VERSION 5.8 ;
BUSBITCHARS "[]" ;
DIVIDERCHAR "/" ;
UNITS
    DATABASE MICRONS 1000 ;
END UNITS

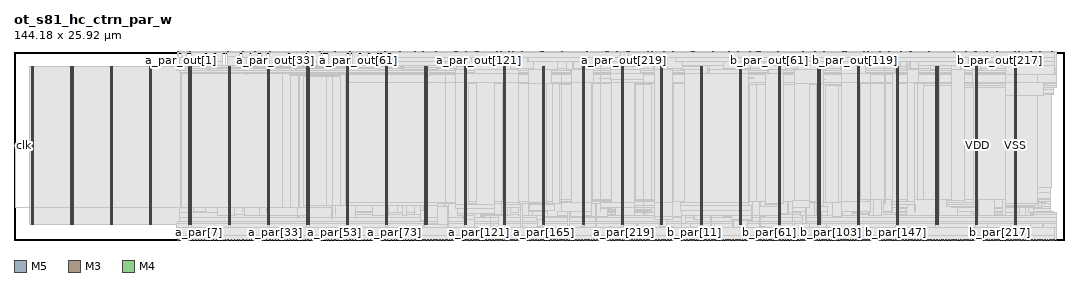
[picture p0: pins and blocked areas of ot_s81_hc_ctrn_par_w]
MACRO ot_s81_hc_ctrn_par_w
  FOREIGN ot_s81_hc_ctrn_par_w 0 0 ;
  CLASS BLOCK ;
  SIZE 144.18 BY 25.92 ;
  PIN a_par[0]
    DIRECTION INPUT ;
    USE SIGNAL ;
    PORT
      LAYER M5 ;
        RECT  22.512 0 22.536 0.084 ;
    END
  END a_par[0]
  PIN a_par[100]
    DIRECTION INPUT ;
    USE SIGNAL ;
    PORT
      LAYER M5 ;
        RECT  59.568 0 59.592 0.084 ;
    END
  END a_par[100]
  PIN a_par[101]
    DIRECTION INPUT ;
    USE SIGNAL ;
    PORT
      LAYER M3 ;
        RECT  59.796 0 59.814 0.038 ;
    END
  END a_par[101]
  PIN a_par[102]
    DIRECTION INPUT ;
    USE SIGNAL ;
    PORT
      LAYER M5 ;
        RECT  60.048 0 60.072 0.084 ;
    END
  END a_par[102]
  PIN a_par[103]
    DIRECTION INPUT ;
    USE SIGNAL ;
    PORT
      LAYER M3 ;
        RECT  60.192 0 60.21 0.038 ;
    END
  END a_par[103]
  PIN a_par[104]
    DIRECTION INPUT ;
    USE SIGNAL ;
    PORT
      LAYER M5 ;
        RECT  60.432 0 60.456 0.084 ;
    END
  END a_par[104]
  PIN a_par[105]
    DIRECTION INPUT ;
    USE SIGNAL ;
    PORT
      LAYER M3 ;
        RECT  60.552 0 60.57 0.038 ;
    END
  END a_par[105]
  PIN a_par[106]
    DIRECTION INPUT ;
    USE SIGNAL ;
    PORT
      LAYER M5 ;
        RECT  60.816 0 60.84 0.084 ;
    END
  END a_par[106]
  PIN a_par[107]
    DIRECTION INPUT ;
    USE SIGNAL ;
    PORT
      LAYER M3 ;
        RECT  61.056 0 61.074 0.038 ;
    END
  END a_par[107]
  PIN a_par[108]
    DIRECTION INPUT ;
    USE SIGNAL ;
    PORT
      LAYER M5 ;
        RECT  61.2 0 61.224 0.084 ;
    END
  END a_par[108]
  PIN a_par[109]
    DIRECTION INPUT ;
    USE SIGNAL ;
    PORT
      LAYER M3 ;
        RECT  61.416 0 61.434 0.038 ;
    END
  END a_par[109]
  PIN a_par[10]
    DIRECTION INPUT ;
    USE SIGNAL ;
    PORT
      LAYER M5 ;
        RECT  26.544 0 26.568 0.084 ;
    END
  END a_par[10]
  PIN a_par[110]
    DIRECTION INPUT ;
    USE SIGNAL ;
    PORT
      LAYER M5 ;
        RECT  61.584 0 61.608 0.084 ;
    END
  END a_par[110]
  PIN a_par[111]
    DIRECTION INPUT ;
    USE SIGNAL ;
    PORT
      LAYER M3 ;
        RECT  61.812 0 61.83 0.038 ;
    END
  END a_par[111]
  PIN a_par[112]
    DIRECTION INPUT ;
    USE SIGNAL ;
    PORT
      LAYER M5 ;
        RECT  62.064 0 62.088 0.084 ;
    END
  END a_par[112]
  PIN a_par[113]
    DIRECTION INPUT ;
    USE SIGNAL ;
    PORT
      LAYER M3 ;
        RECT  62.208 0 62.226 0.038 ;
    END
  END a_par[113]
  PIN a_par[114]
    DIRECTION INPUT ;
    USE SIGNAL ;
    PORT
      LAYER M5 ;
        RECT  62.448 0 62.472 0.084 ;
    END
  END a_par[114]
  PIN a_par[115]
    DIRECTION INPUT ;
    USE SIGNAL ;
    PORT
      LAYER M3 ;
        RECT  62.676 0 62.694 0.038 ;
    END
  END a_par[115]
  PIN a_par[116]
    DIRECTION INPUT ;
    USE SIGNAL ;
    PORT
      LAYER M5 ;
        RECT  62.832 0 62.856 0.084 ;
    END
  END a_par[116]
  PIN a_par[117]
    DIRECTION INPUT ;
    USE SIGNAL ;
    PORT
      LAYER M3 ;
        RECT  63.072 0 63.09 0.038 ;
    END
  END a_par[117]
  PIN a_par[118]
    DIRECTION INPUT ;
    USE SIGNAL ;
    PORT
      LAYER M5 ;
        RECT  63.216 0 63.24 0.084 ;
    END
  END a_par[118]
  PIN a_par[119]
    DIRECTION INPUT ;
    USE SIGNAL ;
    PORT
      LAYER M3 ;
        RECT  63.432 0 63.45 0.038 ;
    END
  END a_par[119]
  PIN a_par[11]
    DIRECTION INPUT ;
    USE SIGNAL ;
    PORT
      LAYER M3 ;
        RECT  26.964 0 26.982 0.038 ;
    END
  END a_par[11]
  PIN a_par[120]
    DIRECTION INPUT ;
    USE SIGNAL ;
    PORT
      LAYER M5 ;
        RECT  63.696 0 63.72 0.084 ;
    END
  END a_par[120]
  PIN a_par[121]
    DIRECTION INPUT ;
    USE SIGNAL ;
    PORT
      LAYER M3 ;
        RECT  63.828 0 63.846 0.038 ;
    END
  END a_par[121]
  PIN a_par[122]
    DIRECTION INPUT ;
    USE SIGNAL ;
    PORT
      LAYER M5 ;
        RECT  64.08 0 64.104 0.084 ;
    END
  END a_par[122]
  PIN a_par[123]
    DIRECTION INPUT ;
    USE SIGNAL ;
    PORT
      LAYER M3 ;
        RECT  64.224 0 64.242 0.038 ;
    END
  END a_par[123]
  PIN a_par[124]
    DIRECTION INPUT ;
    USE SIGNAL ;
    PORT
      LAYER M5 ;
        RECT  64.464 0 64.488 0.084 ;
    END
  END a_par[124]
  PIN a_par[125]
    DIRECTION INPUT ;
    USE SIGNAL ;
    PORT
      LAYER M3 ;
        RECT  64.692 0 64.71 0.038 ;
    END
  END a_par[125]
  PIN a_par[126]
    DIRECTION INPUT ;
    USE SIGNAL ;
    PORT
      LAYER M5 ;
        RECT  64.848 0 64.872 0.084 ;
    END
  END a_par[126]
  PIN a_par[127]
    DIRECTION INPUT ;
    USE SIGNAL ;
    PORT
      LAYER M3 ;
        RECT  65.088 0 65.106 0.038 ;
    END
  END a_par[127]
  PIN a_par[128]
    DIRECTION INPUT ;
    USE SIGNAL ;
    PORT
      LAYER M5 ;
        RECT  65.328 0 65.352 0.084 ;
    END
  END a_par[128]
  PIN a_par[129]
    DIRECTION INPUT ;
    USE SIGNAL ;
    PORT
      LAYER M3 ;
        RECT  65.448 0 65.466 0.038 ;
    END
  END a_par[129]
  PIN a_par[12]
    DIRECTION INPUT ;
    USE SIGNAL ;
    PORT
      LAYER M5 ;
        RECT  27.408 0 27.432 0.084 ;
    END
  END a_par[12]
  PIN a_par[130]
    DIRECTION INPUT ;
    USE SIGNAL ;
    PORT
      LAYER M5 ;
        RECT  65.712 0 65.736 0.084 ;
    END
  END a_par[130]
  PIN a_par[131]
    DIRECTION INPUT ;
    USE SIGNAL ;
    PORT
      LAYER M3 ;
        RECT  65.844 0 65.862 0.038 ;
    END
  END a_par[131]
  PIN a_par[132]
    DIRECTION INPUT ;
    USE SIGNAL ;
    PORT
      LAYER M5 ;
        RECT  66.096 0 66.12 0.084 ;
    END
  END a_par[132]
  PIN a_par[133]
    DIRECTION INPUT ;
    USE SIGNAL ;
    PORT
      LAYER M3 ;
        RECT  66.312 0 66.33 0.038 ;
    END
  END a_par[133]
  PIN a_par[134]
    DIRECTION INPUT ;
    USE SIGNAL ;
    PORT
      LAYER M5 ;
        RECT  66.48 0 66.504 0.084 ;
    END
  END a_par[134]
  PIN a_par[135]
    DIRECTION INPUT ;
    USE SIGNAL ;
    PORT
      LAYER M3 ;
        RECT  66.708 0 66.726 0.038 ;
    END
  END a_par[135]
  PIN a_par[136]
    DIRECTION INPUT ;
    USE SIGNAL ;
    PORT
      LAYER M5 ;
        RECT  66.864 0 66.888 0.084 ;
    END
  END a_par[136]
  PIN a_par[137]
    DIRECTION INPUT ;
    USE SIGNAL ;
    PORT
      LAYER M3 ;
        RECT  67.104 0 67.122 0.038 ;
    END
  END a_par[137]
  PIN a_par[138]
    DIRECTION INPUT ;
    USE SIGNAL ;
    PORT
      LAYER M5 ;
        RECT  67.344 0 67.368 0.084 ;
    END
  END a_par[138]
  PIN a_par[139]
    DIRECTION INPUT ;
    USE SIGNAL ;
    PORT
      LAYER M3 ;
        RECT  67.464 0 67.482 0.038 ;
    END
  END a_par[139]
  PIN a_par[13]
    DIRECTION INPUT ;
    USE SIGNAL ;
    PORT
      LAYER M3 ;
        RECT  27.828 0 27.846 0.038 ;
    END
  END a_par[13]
  PIN a_par[140]
    DIRECTION INPUT ;
    USE SIGNAL ;
    PORT
      LAYER M5 ;
        RECT  67.728 0 67.752 0.084 ;
    END
  END a_par[140]
  PIN a_par[141]
    DIRECTION INPUT ;
    USE SIGNAL ;
    PORT
      LAYER M3 ;
        RECT  67.968 0 67.986 0.038 ;
    END
  END a_par[141]
  PIN a_par[142]
    DIRECTION INPUT ;
    USE SIGNAL ;
    PORT
      LAYER M5 ;
        RECT  68.112 0 68.136 0.084 ;
    END
  END a_par[142]
  PIN a_par[143]
    DIRECTION INPUT ;
    USE SIGNAL ;
    PORT
      LAYER M3 ;
        RECT  68.328 0 68.346 0.038 ;
    END
  END a_par[143]
  PIN a_par[144]
    DIRECTION INPUT ;
    USE SIGNAL ;
    PORT
      LAYER M5 ;
        RECT  68.496 0 68.52 0.084 ;
    END
  END a_par[144]
  PIN a_par[145]
    DIRECTION INPUT ;
    USE SIGNAL ;
    PORT
      LAYER M3 ;
        RECT  68.724 0 68.742 0.038 ;
    END
  END a_par[145]
  PIN a_par[146]
    DIRECTION INPUT ;
    USE SIGNAL ;
    PORT
      LAYER M5 ;
        RECT  68.976 0 69 0.084 ;
    END
  END a_par[146]
  PIN a_par[147]
    DIRECTION INPUT ;
    USE SIGNAL ;
    PORT
      LAYER M3 ;
        RECT  69.12 0 69.138 0.038 ;
    END
  END a_par[147]
  PIN a_par[148]
    DIRECTION INPUT ;
    USE SIGNAL ;
    PORT
      LAYER M5 ;
        RECT  69.36 0 69.384 0.084 ;
    END
  END a_par[148]
  PIN a_par[149]
    DIRECTION INPUT ;
    USE SIGNAL ;
    PORT
      LAYER M3 ;
        RECT  69.588 0 69.606 0.038 ;
    END
  END a_par[149]
  PIN a_par[14]
    DIRECTION INPUT ;
    USE SIGNAL ;
    PORT
      LAYER M5 ;
        RECT  28.176 0 28.2 0.084 ;
    END
  END a_par[14]
  PIN a_par[150]
    DIRECTION INPUT ;
    USE SIGNAL ;
    PORT
      LAYER M5 ;
        RECT  69.744 0 69.768 0.084 ;
    END
  END a_par[150]
  PIN a_par[151]
    DIRECTION INPUT ;
    USE SIGNAL ;
    PORT
      LAYER M3 ;
        RECT  69.984 0 70.002 0.038 ;
    END
  END a_par[151]
  PIN a_par[152]
    DIRECTION INPUT ;
    USE SIGNAL ;
    PORT
      LAYER M5 ;
        RECT  70.128 0 70.152 0.084 ;
    END
  END a_par[152]
  PIN a_par[153]
    DIRECTION INPUT ;
    USE SIGNAL ;
    PORT
      LAYER M3 ;
        RECT  70.344 0 70.362 0.038 ;
    END
  END a_par[153]
  PIN a_par[154]
    DIRECTION INPUT ;
    USE SIGNAL ;
    PORT
      LAYER M5 ;
        RECT  70.608 0 70.632 0.084 ;
    END
  END a_par[154]
  PIN a_par[155]
    DIRECTION INPUT ;
    USE SIGNAL ;
    PORT
      LAYER M3 ;
        RECT  70.74 0 70.758 0.038 ;
    END
  END a_par[155]
  PIN a_par[156]
    DIRECTION INPUT ;
    USE SIGNAL ;
    PORT
      LAYER M5 ;
        RECT  70.992 0 71.016 0.084 ;
    END
  END a_par[156]
  PIN a_par[157]
    DIRECTION INPUT ;
    USE SIGNAL ;
    PORT
      LAYER M3 ;
        RECT  71.136 0 71.154 0.038 ;
    END
  END a_par[157]
  PIN a_par[158]
    DIRECTION INPUT ;
    USE SIGNAL ;
    PORT
      LAYER M5 ;
        RECT  71.376 0 71.4 0.084 ;
    END
  END a_par[158]
  PIN a_par[159]
    DIRECTION INPUT ;
    USE SIGNAL ;
    PORT
      LAYER M3 ;
        RECT  71.604 0 71.622 0.038 ;
    END
  END a_par[159]
  PIN a_par[15]
    DIRECTION INPUT ;
    USE SIGNAL ;
    PORT
      LAYER M3 ;
        RECT  28.584 0 28.602 0.038 ;
    END
  END a_par[15]
  PIN a_par[160]
    DIRECTION INPUT ;
    USE SIGNAL ;
    PORT
      LAYER M5 ;
        RECT  71.76 0 71.784 0.084 ;
    END
  END a_par[160]
  PIN a_par[161]
    DIRECTION INPUT ;
    USE SIGNAL ;
    PORT
      LAYER M3 ;
        RECT  72 0 72.018 0.038 ;
    END
  END a_par[161]
  PIN a_par[162]
    DIRECTION INPUT ;
    USE SIGNAL ;
    PORT
      LAYER M5 ;
        RECT  72.24 0 72.264 0.084 ;
    END
  END a_par[162]
  PIN a_par[163]
    DIRECTION INPUT ;
    USE SIGNAL ;
    PORT
      LAYER M3 ;
        RECT  72.36 0 72.378 0.038 ;
    END
  END a_par[163]
  PIN a_par[164]
    DIRECTION INPUT ;
    USE SIGNAL ;
    PORT
      LAYER M5 ;
        RECT  72.624 0 72.648 0.084 ;
    END
  END a_par[164]
  PIN a_par[165]
    DIRECTION INPUT ;
    USE SIGNAL ;
    PORT
      LAYER M3 ;
        RECT  72.756 0 72.774 0.038 ;
    END
  END a_par[165]
  PIN a_par[166]
    DIRECTION INPUT ;
    USE SIGNAL ;
    PORT
      LAYER M5 ;
        RECT  73.008 0 73.032 0.084 ;
    END
  END a_par[166]
  PIN a_par[167]
    DIRECTION INPUT ;
    USE SIGNAL ;
    PORT
      LAYER M3 ;
        RECT  73.224 0 73.242 0.038 ;
    END
  END a_par[167]
  PIN a_par[168]
    DIRECTION INPUT ;
    USE SIGNAL ;
    PORT
      LAYER M5 ;
        RECT  73.392 0 73.416 0.084 ;
    END
  END a_par[168]
  PIN a_par[169]
    DIRECTION INPUT ;
    USE SIGNAL ;
    PORT
      LAYER M3 ;
        RECT  73.62 0 73.638 0.038 ;
    END
  END a_par[169]
  PIN a_par[16]
    DIRECTION INPUT ;
    USE SIGNAL ;
    PORT
      LAYER M5 ;
        RECT  29.04 0 29.064 0.084 ;
    END
  END a_par[16]
  PIN a_par[170]
    DIRECTION INPUT ;
    USE SIGNAL ;
    PORT
      LAYER M5 ;
        RECT  73.776 0 73.8 0.084 ;
    END
  END a_par[170]
  PIN a_par[171]
    DIRECTION INPUT ;
    USE SIGNAL ;
    PORT
      LAYER M3 ;
        RECT  74.016 0 74.034 0.038 ;
    END
  END a_par[171]
  PIN a_par[172]
    DIRECTION INPUT ;
    USE SIGNAL ;
    PORT
      LAYER M5 ;
        RECT  74.256 0 74.28 0.084 ;
    END
  END a_par[172]
  PIN a_par[173]
    DIRECTION INPUT ;
    USE SIGNAL ;
    PORT
      LAYER M3 ;
        RECT  74.376 0 74.394 0.038 ;
    END
  END a_par[173]
  PIN a_par[174]
    DIRECTION INPUT ;
    USE SIGNAL ;
    PORT
      LAYER M5 ;
        RECT  74.64 0 74.664 0.084 ;
    END
  END a_par[174]
  PIN a_par[175]
    DIRECTION INPUT ;
    USE SIGNAL ;
    PORT
      LAYER M3 ;
        RECT  74.88 0 74.898 0.038 ;
    END
  END a_par[175]
  PIN a_par[176]
    DIRECTION INPUT ;
    USE SIGNAL ;
    PORT
      LAYER M5 ;
        RECT  75.024 0 75.048 0.084 ;
    END
  END a_par[176]
  PIN a_par[177]
    DIRECTION INPUT ;
    USE SIGNAL ;
    PORT
      LAYER M3 ;
        RECT  75.24 0 75.258 0.038 ;
    END
  END a_par[177]
  PIN a_par[178]
    DIRECTION INPUT ;
    USE SIGNAL ;
    PORT
      LAYER M5 ;
        RECT  75.408 0 75.432 0.084 ;
    END
  END a_par[178]
  PIN a_par[179]
    DIRECTION INPUT ;
    USE SIGNAL ;
    PORT
      LAYER M3 ;
        RECT  75.636 0 75.654 0.038 ;
    END
  END a_par[179]
  PIN a_par[17]
    DIRECTION INPUT ;
    USE SIGNAL ;
    PORT
      LAYER M3 ;
        RECT  29.376 0 29.394 0.038 ;
    END
  END a_par[17]
  PIN a_par[180]
    DIRECTION INPUT ;
    USE SIGNAL ;
    PORT
      LAYER M5 ;
        RECT  75.888 0 75.912 0.084 ;
    END
  END a_par[180]
  PIN a_par[181]
    DIRECTION INPUT ;
    USE SIGNAL ;
    PORT
      LAYER M3 ;
        RECT  76.032 0 76.05 0.038 ;
    END
  END a_par[181]
  PIN a_par[182]
    DIRECTION INPUT ;
    USE SIGNAL ;
    PORT
      LAYER M5 ;
        RECT  76.272 0 76.296 0.084 ;
    END
  END a_par[182]
  PIN a_par[183]
    DIRECTION INPUT ;
    USE SIGNAL ;
    PORT
      LAYER M3 ;
        RECT  76.392 0 76.41 0.038 ;
    END
  END a_par[183]
  PIN a_par[184]
    DIRECTION INPUT ;
    USE SIGNAL ;
    PORT
      LAYER M5 ;
        RECT  76.656 0 76.68 0.084 ;
    END
  END a_par[184]
  PIN a_par[185]
    DIRECTION INPUT ;
    USE SIGNAL ;
    PORT
      LAYER M3 ;
        RECT  76.896 0 76.914 0.038 ;
    END
  END a_par[185]
  PIN a_par[186]
    DIRECTION INPUT ;
    USE SIGNAL ;
    PORT
      LAYER M5 ;
        RECT  77.04 0 77.064 0.084 ;
    END
  END a_par[186]
  PIN a_par[187]
    DIRECTION INPUT ;
    USE SIGNAL ;
    PORT
      LAYER M3 ;
        RECT  77.256 0 77.274 0.038 ;
    END
  END a_par[187]
  PIN a_par[188]
    DIRECTION INPUT ;
    USE SIGNAL ;
    PORT
      LAYER M5 ;
        RECT  77.52 0 77.544 0.084 ;
    END
  END a_par[188]
  PIN a_par[189]
    DIRECTION INPUT ;
    USE SIGNAL ;
    PORT
      LAYER M3 ;
        RECT  77.652 0 77.67 0.038 ;
    END
  END a_par[189]
  PIN a_par[18]
    DIRECTION INPUT ;
    USE SIGNAL ;
    PORT
      LAYER M5 ;
        RECT  29.808 0 29.832 0.084 ;
    END
  END a_par[18]
  PIN a_par[190]
    DIRECTION INPUT ;
    USE SIGNAL ;
    PORT
      LAYER M5 ;
        RECT  77.904 0 77.928 0.084 ;
    END
  END a_par[190]
  PIN a_par[191]
    DIRECTION INPUT ;
    USE SIGNAL ;
    PORT
      LAYER M3 ;
        RECT  78.048 0 78.066 0.038 ;
    END
  END a_par[191]
  PIN a_par[192]
    DIRECTION INPUT ;
    USE SIGNAL ;
    PORT
      LAYER M5 ;
        RECT  78.288 0 78.312 0.084 ;
    END
  END a_par[192]
  PIN a_par[193]
    DIRECTION INPUT ;
    USE SIGNAL ;
    PORT
      LAYER M3 ;
        RECT  78.516 0 78.534 0.038 ;
    END
  END a_par[193]
  PIN a_par[194]
    DIRECTION INPUT ;
    USE SIGNAL ;
    PORT
      LAYER M5 ;
        RECT  78.672 0 78.696 0.084 ;
    END
  END a_par[194]
  PIN a_par[195]
    DIRECTION INPUT ;
    USE SIGNAL ;
    PORT
      LAYER M3 ;
        RECT  78.912 0 78.93 0.038 ;
    END
  END a_par[195]
  PIN a_par[196]
    DIRECTION INPUT ;
    USE SIGNAL ;
    PORT
      LAYER M5 ;
        RECT  79.056 0 79.08 0.084 ;
    END
  END a_par[196]
  PIN a_par[197]
    DIRECTION INPUT ;
    USE SIGNAL ;
    PORT
      LAYER M3 ;
        RECT  79.272 0 79.29 0.038 ;
    END
  END a_par[197]
  PIN a_par[198]
    DIRECTION INPUT ;
    USE SIGNAL ;
    PORT
      LAYER M5 ;
        RECT  79.536 0 79.56 0.084 ;
    END
  END a_par[198]
  PIN a_par[199]
    DIRECTION INPUT ;
    USE SIGNAL ;
    PORT
      LAYER M3 ;
        RECT  79.668 0 79.686 0.038 ;
    END
  END a_par[199]
  PIN a_par[19]
    DIRECTION INPUT ;
    USE SIGNAL ;
    PORT
      LAYER M3 ;
        RECT  30.24 0 30.258 0.038 ;
    END
  END a_par[19]
  PIN a_par[1]
    DIRECTION INPUT ;
    USE SIGNAL ;
    PORT
      LAYER M3 ;
        RECT  22.932 0 22.95 0.038 ;
    END
  END a_par[1]
  PIN a_par[200]
    DIRECTION INPUT ;
    USE SIGNAL ;
    PORT
      LAYER M5 ;
        RECT  79.92 0 79.944 0.084 ;
    END
  END a_par[200]
  PIN a_par[201]
    DIRECTION INPUT ;
    USE SIGNAL ;
    PORT
      LAYER M3 ;
        RECT  80.136 0 80.154 0.038 ;
    END
  END a_par[201]
  PIN a_par[202]
    DIRECTION INPUT ;
    USE SIGNAL ;
    PORT
      LAYER M5 ;
        RECT  80.304 0 80.328 0.084 ;
    END
  END a_par[202]
  PIN a_par[203]
    DIRECTION INPUT ;
    USE SIGNAL ;
    PORT
      LAYER M3 ;
        RECT  80.532 0 80.55 0.038 ;
    END
  END a_par[203]
  PIN a_par[204]
    DIRECTION INPUT ;
    USE SIGNAL ;
    PORT
      LAYER M5 ;
        RECT  80.688 0 80.712 0.084 ;
    END
  END a_par[204]
  PIN a_par[205]
    DIRECTION INPUT ;
    USE SIGNAL ;
    PORT
      LAYER M3 ;
        RECT  80.928 0 80.946 0.038 ;
    END
  END a_par[205]
  PIN a_par[206]
    DIRECTION INPUT ;
    USE SIGNAL ;
    PORT
      LAYER M5 ;
        RECT  81.168 0 81.192 0.084 ;
    END
  END a_par[206]
  PIN a_par[207]
    DIRECTION INPUT ;
    USE SIGNAL ;
    PORT
      LAYER M3 ;
        RECT  81.288 0 81.306 0.038 ;
    END
  END a_par[207]
  PIN a_par[208]
    DIRECTION INPUT ;
    USE SIGNAL ;
    PORT
      LAYER M5 ;
        RECT  81.552 0 81.576 0.084 ;
    END
  END a_par[208]
  PIN a_par[209]
    DIRECTION INPUT ;
    USE SIGNAL ;
    PORT
      LAYER M3 ;
        RECT  81.792 0 81.81 0.038 ;
    END
  END a_par[209]
  PIN a_par[20]
    DIRECTION INPUT ;
    USE SIGNAL ;
    PORT
      LAYER M5 ;
        RECT  30.672 0 30.696 0.084 ;
    END
  END a_par[20]
  PIN a_par[210]
    DIRECTION INPUT ;
    USE SIGNAL ;
    PORT
      LAYER M5 ;
        RECT  81.936 0 81.96 0.084 ;
    END
  END a_par[210]
  PIN a_par[211]
    DIRECTION INPUT ;
    USE SIGNAL ;
    PORT
      LAYER M3 ;
        RECT  82.152 0 82.17 0.038 ;
    END
  END a_par[211]
  PIN a_par[212]
    DIRECTION INPUT ;
    USE SIGNAL ;
    PORT
      LAYER M5 ;
        RECT  82.32 0 82.344 0.084 ;
    END
  END a_par[212]
  PIN a_par[213]
    DIRECTION INPUT ;
    USE SIGNAL ;
    PORT
      LAYER M3 ;
        RECT  82.548 0 82.566 0.038 ;
    END
  END a_par[213]
  PIN a_par[214]
    DIRECTION INPUT ;
    USE SIGNAL ;
    PORT
      LAYER M5 ;
        RECT  82.8 0 82.824 0.084 ;
    END
  END a_par[214]
  PIN a_par[215]
    DIRECTION INPUT ;
    USE SIGNAL ;
    PORT
      LAYER M3 ;
        RECT  82.944 0 82.962 0.038 ;
    END
  END a_par[215]
  PIN a_par[216]
    DIRECTION INPUT ;
    USE SIGNAL ;
    PORT
      LAYER M5 ;
        RECT  83.184 0 83.208 0.084 ;
    END
  END a_par[216]
  PIN a_par[217]
    DIRECTION INPUT ;
    USE SIGNAL ;
    PORT
      LAYER M3 ;
        RECT  83.304 0 83.322 0.038 ;
    END
  END a_par[217]
  PIN a_par[218]
    DIRECTION INPUT ;
    USE SIGNAL ;
    PORT
      LAYER M5 ;
        RECT  83.568 0 83.592 0.084 ;
    END
  END a_par[218]
  PIN a_par[219]
    DIRECTION INPUT ;
    USE SIGNAL ;
    PORT
      LAYER M3 ;
        RECT  83.808 0 83.826 0.038 ;
    END
  END a_par[219]
  PIN a_par[21]
    DIRECTION INPUT ;
    USE SIGNAL ;
    PORT
      LAYER M3 ;
        RECT  30.996 0 31.014 0.038 ;
    END
  END a_par[21]
  PIN a_par[220]
    DIRECTION INPUT ;
    USE SIGNAL ;
    PORT
      LAYER M5 ;
        RECT  83.952 0 83.976 0.084 ;
    END
  END a_par[220]
  PIN a_par[221]
    DIRECTION INPUT ;
    USE SIGNAL ;
    PORT
      LAYER M3 ;
        RECT  84.168 0 84.186 0.038 ;
    END
  END a_par[221]
  PIN a_par[222]
    DIRECTION INPUT ;
    USE SIGNAL ;
    PORT
      LAYER M5 ;
        RECT  84.432 0 84.456 0.084 ;
    END
  END a_par[222]
  PIN a_par[223]
    DIRECTION INPUT ;
    USE SIGNAL ;
    PORT
      LAYER M3 ;
        RECT  84.564 0 84.582 0.038 ;
    END
  END a_par[223]
  PIN a_par[224]
    DIRECTION INPUT ;
    USE SIGNAL ;
    PORT
      LAYER M5 ;
        RECT  84.816 0 84.84 0.084 ;
    END
  END a_par[224]
  PIN a_par[225]
    DIRECTION INPUT ;
    USE SIGNAL ;
    PORT
      LAYER M3 ;
        RECT  84.96 0 84.978 0.038 ;
    END
  END a_par[225]
  PIN a_par[226]
    DIRECTION INPUT ;
    USE SIGNAL ;
    PORT
      LAYER M5 ;
        RECT  85.2 0 85.224 0.084 ;
    END
  END a_par[226]
  PIN a_par[227]
    DIRECTION INPUT ;
    USE SIGNAL ;
    PORT
      LAYER M3 ;
        RECT  85.428 0 85.446 0.038 ;
    END
  END a_par[227]
  PIN a_par[228]
    DIRECTION INPUT ;
    USE SIGNAL ;
    PORT
      LAYER M5 ;
        RECT  85.584 0 85.608 0.084 ;
    END
  END a_par[228]
  PIN a_par[229]
    DIRECTION INPUT ;
    USE SIGNAL ;
    PORT
      LAYER M3 ;
        RECT  85.824 0 85.842 0.038 ;
    END
  END a_par[229]
  PIN a_par[22]
    DIRECTION INPUT ;
    USE SIGNAL ;
    PORT
      LAYER M5 ;
        RECT  31.44 0 31.464 0.084 ;
    END
  END a_par[22]
  PIN a_par[230]
    DIRECTION INPUT ;
    USE SIGNAL ;
    PORT
      LAYER M5 ;
        RECT  85.968 0 85.992 0.084 ;
    END
  END a_par[230]
  PIN a_par[231]
    DIRECTION INPUT ;
    USE SIGNAL ;
    PORT
      LAYER M3 ;
        RECT  86.184 0 86.202 0.038 ;
    END
  END a_par[231]
  PIN a_par[232]
    DIRECTION INPUT ;
    USE SIGNAL ;
    PORT
      LAYER M5 ;
        RECT  86.448 0 86.472 0.084 ;
    END
  END a_par[232]
  PIN a_par[233]
    DIRECTION INPUT ;
    USE SIGNAL ;
    PORT
      LAYER M3 ;
        RECT  86.58 0 86.598 0.038 ;
    END
  END a_par[233]
  PIN a_par[234]
    DIRECTION INPUT ;
    USE SIGNAL ;
    PORT
      LAYER M5 ;
        RECT  86.832 0 86.856 0.084 ;
    END
  END a_par[234]
  PIN a_par[235]
    DIRECTION INPUT ;
    USE SIGNAL ;
    PORT
      LAYER M3 ;
        RECT  87.048 0 87.066 0.038 ;
    END
  END a_par[235]
  PIN a_par[236]
    DIRECTION INPUT ;
    USE SIGNAL ;
    PORT
      LAYER M5 ;
        RECT  87.216 0 87.24 0.084 ;
    END
  END a_par[236]
  PIN a_par[237]
    DIRECTION INPUT ;
    USE SIGNAL ;
    PORT
      LAYER M3 ;
        RECT  87.444 0 87.462 0.038 ;
    END
  END a_par[237]
  PIN a_par[238]
    DIRECTION INPUT ;
    USE SIGNAL ;
    PORT
      LAYER M5 ;
        RECT  87.6 0 87.624 0.084 ;
    END
  END a_par[238]
  PIN a_par[239]
    DIRECTION INPUT ;
    USE SIGNAL ;
    PORT
      LAYER M3 ;
        RECT  87.84 0 87.858 0.038 ;
    END
  END a_par[239]
  PIN a_par[23]
    DIRECTION INPUT ;
    USE SIGNAL ;
    PORT
      LAYER M3 ;
        RECT  31.86 0 31.878 0.038 ;
    END
  END a_par[23]
  PIN a_par[240]
    DIRECTION INPUT ;
    USE SIGNAL ;
    PORT
      LAYER M5 ;
        RECT  88.08 0 88.104 0.084 ;
    END
  END a_par[240]
  PIN a_par[241]
    DIRECTION INPUT ;
    USE SIGNAL ;
    PORT
      LAYER M3 ;
        RECT  88.2 0 88.218 0.038 ;
    END
  END a_par[241]
  PIN a_par[242]
    DIRECTION INPUT ;
    USE SIGNAL ;
    PORT
      LAYER M5 ;
        RECT  88.464 0 88.488 0.084 ;
    END
  END a_par[242]
  PIN a_par[243]
    DIRECTION INPUT ;
    USE SIGNAL ;
    PORT
      LAYER M3 ;
        RECT  88.596 0 88.614 0.038 ;
    END
  END a_par[243]
  PIN a_par[244]
    DIRECTION INPUT ;
    USE SIGNAL ;
    PORT
      LAYER M5 ;
        RECT  88.848 0 88.872 0.084 ;
    END
  END a_par[244]
  PIN a_par[245]
    DIRECTION INPUT ;
    USE SIGNAL ;
    PORT
      LAYER M3 ;
        RECT  89.064 0 89.082 0.038 ;
    END
  END a_par[245]
  PIN a_par[246]
    DIRECTION INPUT ;
    USE SIGNAL ;
    PORT
      LAYER M5 ;
        RECT  89.232 0 89.256 0.084 ;
    END
  END a_par[246]
  PIN a_par[247]
    DIRECTION INPUT ;
    USE SIGNAL ;
    PORT
      LAYER M3 ;
        RECT  89.46 0 89.478 0.038 ;
    END
  END a_par[247]
  PIN a_par[248]
    DIRECTION INPUT ;
    USE SIGNAL ;
    PORT
      LAYER M5 ;
        RECT  89.712 0 89.736 0.084 ;
    END
  END a_par[248]
  PIN a_par[249]
    DIRECTION INPUT ;
    USE SIGNAL ;
    PORT
      LAYER M3 ;
        RECT  89.856 0 89.874 0.038 ;
    END
  END a_par[249]
  PIN a_par[24]
    DIRECTION INPUT ;
    USE SIGNAL ;
    PORT
      LAYER M5 ;
        RECT  32.304 0 32.328 0.084 ;
    END
  END a_par[24]
  PIN a_par[250]
    DIRECTION INPUT ;
    USE SIGNAL ;
    PORT
      LAYER M5 ;
        RECT  90.096 0 90.12 0.084 ;
    END
  END a_par[250]
  PIN a_par[251]
    DIRECTION INPUT ;
    USE SIGNAL ;
    PORT
      LAYER M3 ;
        RECT  90.216 0 90.234 0.038 ;
    END
  END a_par[251]
  PIN a_par[252]
    DIRECTION INPUT ;
    USE SIGNAL ;
    PORT
      LAYER M5 ;
        RECT  90.48 0 90.504 0.084 ;
    END
  END a_par[252]
  PIN a_par[253]
    DIRECTION INPUT ;
    USE SIGNAL ;
    PORT
      LAYER M3 ;
        RECT  90.72 0 90.738 0.038 ;
    END
  END a_par[253]
  PIN a_par[254]
    DIRECTION INPUT ;
    USE SIGNAL ;
    PORT
      LAYER M5 ;
        RECT  90.864 0 90.888 0.084 ;
    END
  END a_par[254]
  PIN a_par[255]
    DIRECTION INPUT ;
    USE SIGNAL ;
    PORT
      LAYER M3 ;
        RECT  91.08 0 91.098 0.038 ;
    END
  END a_par[255]
  PIN a_par[25]
    DIRECTION INPUT ;
    USE SIGNAL ;
    PORT
      LAYER M3 ;
        RECT  32.616 0 32.634 0.038 ;
    END
  END a_par[25]
  PIN a_par[26]
    DIRECTION INPUT ;
    USE SIGNAL ;
    PORT
      LAYER M5 ;
        RECT  33.072 0 33.096 0.084 ;
    END
  END a_par[26]
  PIN a_par[27]
    DIRECTION INPUT ;
    USE SIGNAL ;
    PORT
      LAYER M3 ;
        RECT  33.48 0 33.498 0.038 ;
    END
  END a_par[27]
  PIN a_par[28]
    DIRECTION INPUT ;
    USE SIGNAL ;
    PORT
      LAYER M5 ;
        RECT  33.936 0 33.96 0.084 ;
    END
  END a_par[28]
  PIN a_par[29]
    DIRECTION INPUT ;
    USE SIGNAL ;
    PORT
      LAYER M3 ;
        RECT  34.272 0 34.29 0.038 ;
    END
  END a_par[29]
  PIN a_par[2]
    DIRECTION INPUT ;
    USE SIGNAL ;
    PORT
      LAYER M5 ;
        RECT  23.28 0 23.304 0.084 ;
    END
  END a_par[2]
  PIN a_par[30]
    DIRECTION INPUT ;
    USE SIGNAL ;
    PORT
      LAYER M5 ;
        RECT  34.704 0 34.728 0.084 ;
    END
  END a_par[30]
  PIN a_par[31]
    DIRECTION INPUT ;
    USE SIGNAL ;
    PORT
      LAYER M3 ;
        RECT  35.136 0 35.154 0.038 ;
    END
  END a_par[31]
  PIN a_par[32]
    DIRECTION INPUT ;
    USE SIGNAL ;
    PORT
      LAYER M5 ;
        RECT  35.472 0 35.496 0.084 ;
    END
  END a_par[32]
  PIN a_par[33]
    DIRECTION INPUT ;
    USE SIGNAL ;
    PORT
      LAYER M3 ;
        RECT  35.892 0 35.91 0.038 ;
    END
  END a_par[33]
  PIN a_par[34]
    DIRECTION INPUT ;
    USE SIGNAL ;
    PORT
      LAYER M5 ;
        RECT  36.336 0 36.36 0.084 ;
    END
  END a_par[34]
  PIN a_par[35]
    DIRECTION INPUT ;
    USE SIGNAL ;
    PORT
      LAYER M3 ;
        RECT  36.756 0 36.774 0.038 ;
    END
  END a_par[35]
  PIN a_par[36]
    DIRECTION INPUT ;
    USE SIGNAL ;
    PORT
      LAYER M5 ;
        RECT  37.104 0 37.128 0.084 ;
    END
  END a_par[36]
  PIN a_par[37]
    DIRECTION INPUT ;
    USE SIGNAL ;
    PORT
      LAYER M3 ;
        RECT  37.512 0 37.53 0.038 ;
    END
  END a_par[37]
  PIN a_par[38]
    DIRECTION INPUT ;
    USE SIGNAL ;
    PORT
      LAYER M5 ;
        RECT  37.968 0 37.992 0.084 ;
    END
  END a_par[38]
  PIN a_par[39]
    DIRECTION INPUT ;
    USE SIGNAL ;
    PORT
      LAYER M3 ;
        RECT  38.376 0 38.394 0.038 ;
    END
  END a_par[39]
  PIN a_par[3]
    DIRECTION INPUT ;
    USE SIGNAL ;
    PORT
      LAYER M3 ;
        RECT  23.688 0 23.706 0.038 ;
    END
  END a_par[3]
  PIN a_par[40]
    DIRECTION INPUT ;
    USE SIGNAL ;
    PORT
      LAYER M5 ;
        RECT  38.736 0 38.76 0.084 ;
    END
  END a_par[40]
  PIN a_par[41]
    DIRECTION INPUT ;
    USE SIGNAL ;
    PORT
      LAYER M3 ;
        RECT  39.168 0 39.186 0.038 ;
    END
  END a_par[41]
  PIN a_par[42]
    DIRECTION INPUT ;
    USE SIGNAL ;
    PORT
      LAYER M5 ;
        RECT  39.6 0 39.624 0.084 ;
    END
  END a_par[42]
  PIN a_par[43]
    DIRECTION INPUT ;
    USE SIGNAL ;
    PORT
      LAYER M3 ;
        RECT  40.032 0 40.05 0.038 ;
    END
  END a_par[43]
  PIN a_par[44]
    DIRECTION INPUT ;
    USE SIGNAL ;
    PORT
      LAYER M5 ;
        RECT  40.368 0 40.392 0.084 ;
    END
  END a_par[44]
  PIN a_par[45]
    DIRECTION INPUT ;
    USE SIGNAL ;
    PORT
      LAYER M3 ;
        RECT  40.788 0 40.806 0.038 ;
    END
  END a_par[45]
  PIN a_par[46]
    DIRECTION INPUT ;
    USE SIGNAL ;
    PORT
      LAYER M5 ;
        RECT  41.232 0 41.256 0.084 ;
    END
  END a_par[46]
  PIN a_par[47]
    DIRECTION INPUT ;
    USE SIGNAL ;
    PORT
      LAYER M3 ;
        RECT  41.544 0 41.562 0.038 ;
    END
  END a_par[47]
  PIN a_par[48]
    DIRECTION INPUT ;
    USE SIGNAL ;
    PORT
      LAYER M5 ;
        RECT  42 0 42.024 0.084 ;
    END
  END a_par[48]
  PIN a_par[49]
    DIRECTION INPUT ;
    USE SIGNAL ;
    PORT
      LAYER M3 ;
        RECT  42.408 0 42.426 0.038 ;
    END
  END a_par[49]
  PIN a_par[4]
    DIRECTION INPUT ;
    USE SIGNAL ;
    PORT
      LAYER M5 ;
        RECT  24.144 0 24.168 0.084 ;
    END
  END a_par[4]
  PIN a_par[50]
    DIRECTION INPUT ;
    USE SIGNAL ;
    PORT
      LAYER M5 ;
        RECT  42.864 0 42.888 0.084 ;
    END
  END a_par[50]
  PIN a_par[51]
    DIRECTION INPUT ;
    USE SIGNAL ;
    PORT
      LAYER M3 ;
        RECT  43.2 0 43.218 0.038 ;
    END
  END a_par[51]
  PIN a_par[52]
    DIRECTION INPUT ;
    USE SIGNAL ;
    PORT
      LAYER M5 ;
        RECT  43.632 0 43.656 0.084 ;
    END
  END a_par[52]
  PIN a_par[53]
    DIRECTION INPUT ;
    USE SIGNAL ;
    PORT
      LAYER M3 ;
        RECT  44.064 0 44.082 0.038 ;
    END
  END a_par[53]
  PIN a_par[54]
    DIRECTION INPUT ;
    USE SIGNAL ;
    PORT
      LAYER M5 ;
        RECT  44.496 0 44.52 0.084 ;
    END
  END a_par[54]
  PIN a_par[55]
    DIRECTION INPUT ;
    USE SIGNAL ;
    PORT
      LAYER M3 ;
        RECT  44.82 0 44.838 0.038 ;
    END
  END a_par[55]
  PIN a_par[56]
    DIRECTION INPUT ;
    USE SIGNAL ;
    PORT
      LAYER M5 ;
        RECT  45.264 0 45.288 0.084 ;
    END
  END a_par[56]
  PIN a_par[57]
    DIRECTION INPUT ;
    USE SIGNAL ;
    PORT
      LAYER M3 ;
        RECT  45.684 0 45.702 0.038 ;
    END
  END a_par[57]
  PIN a_par[58]
    DIRECTION INPUT ;
    USE SIGNAL ;
    PORT
      LAYER M5 ;
        RECT  46.128 0 46.152 0.084 ;
    END
  END a_par[58]
  PIN a_par[59]
    DIRECTION INPUT ;
    USE SIGNAL ;
    PORT
      LAYER M3 ;
        RECT  46.44 0 46.458 0.038 ;
    END
  END a_par[59]
  PIN a_par[5]
    DIRECTION INPUT ;
    USE SIGNAL ;
    PORT
      LAYER M3 ;
        RECT  24.552 0 24.57 0.038 ;
    END
  END a_par[5]
  PIN a_par[60]
    DIRECTION INPUT ;
    USE SIGNAL ;
    PORT
      LAYER M5 ;
        RECT  46.896 0 46.92 0.084 ;
    END
  END a_par[60]
  PIN a_par[61]
    DIRECTION INPUT ;
    USE SIGNAL ;
    PORT
      LAYER M3 ;
        RECT  47.304 0 47.322 0.038 ;
    END
  END a_par[61]
  PIN a_par[62]
    DIRECTION INPUT ;
    USE SIGNAL ;
    PORT
      LAYER M5 ;
        RECT  47.664 0 47.688 0.084 ;
    END
  END a_par[62]
  PIN a_par[63]
    DIRECTION INPUT ;
    USE SIGNAL ;
    PORT
      LAYER M3 ;
        RECT  48.096 0 48.114 0.038 ;
    END
  END a_par[63]
  PIN a_par[64]
    DIRECTION INPUT ;
    USE SIGNAL ;
    PORT
      LAYER M5 ;
        RECT  48.528 0 48.552 0.084 ;
    END
  END a_par[64]
  PIN a_par[65]
    DIRECTION INPUT ;
    USE SIGNAL ;
    PORT
      LAYER M3 ;
        RECT  48.96 0 48.978 0.038 ;
    END
  END a_par[65]
  PIN a_par[66]
    DIRECTION INPUT ;
    USE SIGNAL ;
    PORT
      LAYER M5 ;
        RECT  49.296 0 49.32 0.084 ;
    END
  END a_par[66]
  PIN a_par[67]
    DIRECTION INPUT ;
    USE SIGNAL ;
    PORT
      LAYER M3 ;
        RECT  49.716 0 49.734 0.038 ;
    END
  END a_par[67]
  PIN a_par[68]
    DIRECTION INPUT ;
    USE SIGNAL ;
    PORT
      LAYER M5 ;
        RECT  50.16 0 50.184 0.084 ;
    END
  END a_par[68]
  PIN a_par[69]
    DIRECTION INPUT ;
    USE SIGNAL ;
    PORT
      LAYER M3 ;
        RECT  50.58 0 50.598 0.038 ;
    END
  END a_par[69]
  PIN a_par[6]
    DIRECTION INPUT ;
    USE SIGNAL ;
    PORT
      LAYER M5 ;
        RECT  24.912 0 24.936 0.084 ;
    END
  END a_par[6]
  PIN a_par[70]
    DIRECTION INPUT ;
    USE SIGNAL ;
    PORT
      LAYER M5 ;
        RECT  50.928 0 50.952 0.084 ;
    END
  END a_par[70]
  PIN a_par[71]
    DIRECTION INPUT ;
    USE SIGNAL ;
    PORT
      LAYER M3 ;
        RECT  51.336 0 51.354 0.038 ;
    END
  END a_par[71]
  PIN a_par[72]
    DIRECTION INPUT ;
    USE SIGNAL ;
    PORT
      LAYER M5 ;
        RECT  51.792 0 51.816 0.084 ;
    END
  END a_par[72]
  PIN a_par[73]
    DIRECTION INPUT ;
    USE SIGNAL ;
    PORT
      LAYER M3 ;
        RECT  52.2 0 52.218 0.038 ;
    END
  END a_par[73]
  PIN a_par[74]
    DIRECTION INPUT ;
    USE SIGNAL ;
    PORT
      LAYER M5 ;
        RECT  52.56 0 52.584 0.084 ;
    END
  END a_par[74]
  PIN a_par[75]
    DIRECTION INPUT ;
    USE SIGNAL ;
    PORT
      LAYER M3 ;
        RECT  52.992 0 53.01 0.038 ;
    END
  END a_par[75]
  PIN a_par[76]
    DIRECTION INPUT ;
    USE SIGNAL ;
    PORT
      LAYER M5 ;
        RECT  53.424 0 53.448 0.084 ;
    END
  END a_par[76]
  PIN a_par[77]
    DIRECTION INPUT ;
    USE SIGNAL ;
    PORT
      LAYER M3 ;
        RECT  53.748 0 53.766 0.038 ;
    END
  END a_par[77]
  PIN a_par[78]
    DIRECTION INPUT ;
    USE SIGNAL ;
    PORT
      LAYER M5 ;
        RECT  54.192 0 54.216 0.084 ;
    END
  END a_par[78]
  PIN a_par[79]
    DIRECTION INPUT ;
    USE SIGNAL ;
    PORT
      LAYER M3 ;
        RECT  54.612 0 54.63 0.038 ;
    END
  END a_par[79]
  PIN a_par[7]
    DIRECTION INPUT ;
    USE SIGNAL ;
    PORT
      LAYER M3 ;
        RECT  25.344 0 25.362 0.038 ;
    END
  END a_par[7]
  PIN a_par[80]
    DIRECTION INPUT ;
    USE SIGNAL ;
    PORT
      LAYER M5 ;
        RECT  55.056 0 55.08 0.084 ;
    END
  END a_par[80]
  PIN a_par[81]
    DIRECTION INPUT ;
    USE SIGNAL ;
    PORT
      LAYER M3 ;
        RECT  55.368 0 55.386 0.038 ;
    END
  END a_par[81]
  PIN a_par[82]
    DIRECTION INPUT ;
    USE SIGNAL ;
    PORT
      LAYER M5 ;
        RECT  55.824 0 55.848 0.084 ;
    END
  END a_par[82]
  PIN a_par[83]
    DIRECTION INPUT ;
    USE SIGNAL ;
    PORT
      LAYER M3 ;
        RECT  56.16 0 56.178 0.038 ;
    END
  END a_par[83]
  PIN a_par[84]
    DIRECTION INPUT ;
    USE SIGNAL ;
    PORT
      LAYER M5 ;
        RECT  56.304 0 56.328 0.084 ;
    END
  END a_par[84]
  PIN a_par[85]
    DIRECTION INPUT ;
    USE SIGNAL ;
    PORT
      LAYER M3 ;
        RECT  56.52 0 56.538 0.038 ;
    END
  END a_par[85]
  PIN a_par[86]
    DIRECTION INPUT ;
    USE SIGNAL ;
    PORT
      LAYER M5 ;
        RECT  56.784 0 56.808 0.084 ;
    END
  END a_par[86]
  PIN a_par[87]
    DIRECTION INPUT ;
    USE SIGNAL ;
    PORT
      LAYER M3 ;
        RECT  56.916 0 56.934 0.038 ;
    END
  END a_par[87]
  PIN a_par[88]
    DIRECTION INPUT ;
    USE SIGNAL ;
    PORT
      LAYER M5 ;
        RECT  57.168 0 57.192 0.084 ;
    END
  END a_par[88]
  PIN a_par[89]
    DIRECTION INPUT ;
    USE SIGNAL ;
    PORT
      LAYER M3 ;
        RECT  57.312 0 57.33 0.038 ;
    END
  END a_par[89]
  PIN a_par[8]
    DIRECTION INPUT ;
    USE SIGNAL ;
    PORT
      LAYER M5 ;
        RECT  25.776 0 25.8 0.084 ;
    END
  END a_par[8]
  PIN a_par[90]
    DIRECTION INPUT ;
    USE SIGNAL ;
    PORT
      LAYER M5 ;
        RECT  57.552 0 57.576 0.084 ;
    END
  END a_par[90]
  PIN a_par[91]
    DIRECTION INPUT ;
    USE SIGNAL ;
    PORT
      LAYER M3 ;
        RECT  57.78 0 57.798 0.038 ;
    END
  END a_par[91]
  PIN a_par[92]
    DIRECTION INPUT ;
    USE SIGNAL ;
    PORT
      LAYER M5 ;
        RECT  57.936 0 57.96 0.084 ;
    END
  END a_par[92]
  PIN a_par[93]
    DIRECTION INPUT ;
    USE SIGNAL ;
    PORT
      LAYER M3 ;
        RECT  58.176 0 58.194 0.038 ;
    END
  END a_par[93]
  PIN a_par[94]
    DIRECTION INPUT ;
    USE SIGNAL ;
    PORT
      LAYER M5 ;
        RECT  58.416 0 58.44 0.084 ;
    END
  END a_par[94]
  PIN a_par[95]
    DIRECTION INPUT ;
    USE SIGNAL ;
    PORT
      LAYER M3 ;
        RECT  58.536 0 58.554 0.038 ;
    END
  END a_par[95]
  PIN a_par[96]
    DIRECTION INPUT ;
    USE SIGNAL ;
    PORT
      LAYER M5 ;
        RECT  58.8 0 58.824 0.084 ;
    END
  END a_par[96]
  PIN a_par[97]
    DIRECTION INPUT ;
    USE SIGNAL ;
    PORT
      LAYER M3 ;
        RECT  58.932 0 58.95 0.038 ;
    END
  END a_par[97]
  PIN a_par[98]
    DIRECTION INPUT ;
    USE SIGNAL ;
    PORT
      LAYER M5 ;
        RECT  59.184 0 59.208 0.084 ;
    END
  END a_par[98]
  PIN a_par[99]
    DIRECTION INPUT ;
    USE SIGNAL ;
    PORT
      LAYER M3 ;
        RECT  59.4 0 59.418 0.038 ;
    END
  END a_par[99]
  PIN a_par[9]
    DIRECTION INPUT ;
    USE SIGNAL ;
    PORT
      LAYER M3 ;
        RECT  26.208 0 26.226 0.038 ;
    END
  END a_par[9]
  PIN a_par_out[0]
    DIRECTION OUTPUT ;
    USE SIGNAL ;
    PORT
      LAYER M5 ;
        RECT  22.512 25.836 22.536 25.92 ;
    END
  END a_par_out[0]
  PIN a_par_out[100]
    DIRECTION OUTPUT ;
    USE SIGNAL ;
    PORT
      LAYER M5 ;
        RECT  59.568 25.836 59.592 25.92 ;
    END
  END a_par_out[100]
  PIN a_par_out[101]
    DIRECTION OUTPUT ;
    USE SIGNAL ;
    PORT
      LAYER M3 ;
        RECT  59.796 25.882 59.814 25.92 ;
    END
  END a_par_out[101]
  PIN a_par_out[102]
    DIRECTION OUTPUT ;
    USE SIGNAL ;
    PORT
      LAYER M5 ;
        RECT  60.048 25.836 60.072 25.92 ;
    END
  END a_par_out[102]
  PIN a_par_out[103]
    DIRECTION OUTPUT ;
    USE SIGNAL ;
    PORT
      LAYER M3 ;
        RECT  60.192 25.882 60.21 25.92 ;
    END
  END a_par_out[103]
  PIN a_par_out[104]
    DIRECTION OUTPUT ;
    USE SIGNAL ;
    PORT
      LAYER M5 ;
        RECT  60.432 25.836 60.456 25.92 ;
    END
  END a_par_out[104]
  PIN a_par_out[105]
    DIRECTION OUTPUT ;
    USE SIGNAL ;
    PORT
      LAYER M3 ;
        RECT  60.552 25.882 60.57 25.92 ;
    END
  END a_par_out[105]
  PIN a_par_out[106]
    DIRECTION OUTPUT ;
    USE SIGNAL ;
    PORT
      LAYER M5 ;
        RECT  60.816 25.836 60.84 25.92 ;
    END
  END a_par_out[106]
  PIN a_par_out[107]
    DIRECTION OUTPUT ;
    USE SIGNAL ;
    PORT
      LAYER M3 ;
        RECT  61.056 25.882 61.074 25.92 ;
    END
  END a_par_out[107]
  PIN a_par_out[108]
    DIRECTION OUTPUT ;
    USE SIGNAL ;
    PORT
      LAYER M5 ;
        RECT  61.2 25.836 61.224 25.92 ;
    END
  END a_par_out[108]
  PIN a_par_out[109]
    DIRECTION OUTPUT ;
    USE SIGNAL ;
    PORT
      LAYER M3 ;
        RECT  61.416 25.882 61.434 25.92 ;
    END
  END a_par_out[109]
  PIN a_par_out[10]
    DIRECTION OUTPUT ;
    USE SIGNAL ;
    PORT
      LAYER M5 ;
        RECT  26.544 25.836 26.568 25.92 ;
    END
  END a_par_out[10]
  PIN a_par_out[110]
    DIRECTION OUTPUT ;
    USE SIGNAL ;
    PORT
      LAYER M5 ;
        RECT  61.584 25.836 61.608 25.92 ;
    END
  END a_par_out[110]
  PIN a_par_out[111]
    DIRECTION OUTPUT ;
    USE SIGNAL ;
    PORT
      LAYER M3 ;
        RECT  61.812 25.882 61.83 25.92 ;
    END
  END a_par_out[111]
  PIN a_par_out[112]
    DIRECTION OUTPUT ;
    USE SIGNAL ;
    PORT
      LAYER M5 ;
        RECT  62.064 25.836 62.088 25.92 ;
    END
  END a_par_out[112]
  PIN a_par_out[113]
    DIRECTION OUTPUT ;
    USE SIGNAL ;
    PORT
      LAYER M3 ;
        RECT  62.208 25.882 62.226 25.92 ;
    END
  END a_par_out[113]
  PIN a_par_out[114]
    DIRECTION OUTPUT ;
    USE SIGNAL ;
    PORT
      LAYER M5 ;
        RECT  62.448 25.836 62.472 25.92 ;
    END
  END a_par_out[114]
  PIN a_par_out[115]
    DIRECTION OUTPUT ;
    USE SIGNAL ;
    PORT
      LAYER M3 ;
        RECT  62.676 25.882 62.694 25.92 ;
    END
  END a_par_out[115]
  PIN a_par_out[116]
    DIRECTION OUTPUT ;
    USE SIGNAL ;
    PORT
      LAYER M5 ;
        RECT  62.832 25.836 62.856 25.92 ;
    END
  END a_par_out[116]
  PIN a_par_out[117]
    DIRECTION OUTPUT ;
    USE SIGNAL ;
    PORT
      LAYER M3 ;
        RECT  63.072 25.882 63.09 25.92 ;
    END
  END a_par_out[117]
  PIN a_par_out[118]
    DIRECTION OUTPUT ;
    USE SIGNAL ;
    PORT
      LAYER M5 ;
        RECT  63.216 25.836 63.24 25.92 ;
    END
  END a_par_out[118]
  PIN a_par_out[119]
    DIRECTION OUTPUT ;
    USE SIGNAL ;
    PORT
      LAYER M3 ;
        RECT  63.432 25.882 63.45 25.92 ;
    END
  END a_par_out[119]
  PIN a_par_out[11]
    DIRECTION OUTPUT ;
    USE SIGNAL ;
    PORT
      LAYER M3 ;
        RECT  26.964 25.882 26.982 25.92 ;
    END
  END a_par_out[11]
  PIN a_par_out[120]
    DIRECTION OUTPUT ;
    USE SIGNAL ;
    PORT
      LAYER M5 ;
        RECT  63.696 25.836 63.72 25.92 ;
    END
  END a_par_out[120]
  PIN a_par_out[121]
    DIRECTION OUTPUT ;
    USE SIGNAL ;
    PORT
      LAYER M3 ;
        RECT  63.828 25.882 63.846 25.92 ;
    END
  END a_par_out[121]
  PIN a_par_out[122]
    DIRECTION OUTPUT ;
    USE SIGNAL ;
    PORT
      LAYER M5 ;
        RECT  64.08 25.836 64.104 25.92 ;
    END
  END a_par_out[122]
  PIN a_par_out[123]
    DIRECTION OUTPUT ;
    USE SIGNAL ;
    PORT
      LAYER M3 ;
        RECT  64.224 25.882 64.242 25.92 ;
    END
  END a_par_out[123]
  PIN a_par_out[124]
    DIRECTION OUTPUT ;
    USE SIGNAL ;
    PORT
      LAYER M5 ;
        RECT  64.464 25.836 64.488 25.92 ;
    END
  END a_par_out[124]
  PIN a_par_out[125]
    DIRECTION OUTPUT ;
    USE SIGNAL ;
    PORT
      LAYER M3 ;
        RECT  64.692 25.882 64.71 25.92 ;
    END
  END a_par_out[125]
  PIN a_par_out[126]
    DIRECTION OUTPUT ;
    USE SIGNAL ;
    PORT
      LAYER M5 ;
        RECT  64.848 25.836 64.872 25.92 ;
    END
  END a_par_out[126]
  PIN a_par_out[127]
    DIRECTION OUTPUT ;
    USE SIGNAL ;
    PORT
      LAYER M3 ;
        RECT  65.088 25.882 65.106 25.92 ;
    END
  END a_par_out[127]
  PIN a_par_out[128]
    DIRECTION OUTPUT ;
    USE SIGNAL ;
    PORT
      LAYER M5 ;
        RECT  65.328 25.836 65.352 25.92 ;
    END
  END a_par_out[128]
  PIN a_par_out[129]
    DIRECTION OUTPUT ;
    USE SIGNAL ;
    PORT
      LAYER M3 ;
        RECT  65.448 25.882 65.466 25.92 ;
    END
  END a_par_out[129]
  PIN a_par_out[12]
    DIRECTION OUTPUT ;
    USE SIGNAL ;
    PORT
      LAYER M5 ;
        RECT  27.408 25.836 27.432 25.92 ;
    END
  END a_par_out[12]
  PIN a_par_out[130]
    DIRECTION OUTPUT ;
    USE SIGNAL ;
    PORT
      LAYER M5 ;
        RECT  65.712 25.836 65.736 25.92 ;
    END
  END a_par_out[130]
  PIN a_par_out[131]
    DIRECTION OUTPUT ;
    USE SIGNAL ;
    PORT
      LAYER M3 ;
        RECT  65.844 25.882 65.862 25.92 ;
    END
  END a_par_out[131]
  PIN a_par_out[132]
    DIRECTION OUTPUT ;
    USE SIGNAL ;
    PORT
      LAYER M5 ;
        RECT  66.096 25.836 66.12 25.92 ;
    END
  END a_par_out[132]
  PIN a_par_out[133]
    DIRECTION OUTPUT ;
    USE SIGNAL ;
    PORT
      LAYER M3 ;
        RECT  66.312 25.882 66.33 25.92 ;
    END
  END a_par_out[133]
  PIN a_par_out[134]
    DIRECTION OUTPUT ;
    USE SIGNAL ;
    PORT
      LAYER M5 ;
        RECT  66.48 25.836 66.504 25.92 ;
    END
  END a_par_out[134]
  PIN a_par_out[135]
    DIRECTION OUTPUT ;
    USE SIGNAL ;
    PORT
      LAYER M3 ;
        RECT  66.708 25.882 66.726 25.92 ;
    END
  END a_par_out[135]
  PIN a_par_out[136]
    DIRECTION OUTPUT ;
    USE SIGNAL ;
    PORT
      LAYER M5 ;
        RECT  66.864 25.836 66.888 25.92 ;
    END
  END a_par_out[136]
  PIN a_par_out[137]
    DIRECTION OUTPUT ;
    USE SIGNAL ;
    PORT
      LAYER M3 ;
        RECT  67.104 25.882 67.122 25.92 ;
    END
  END a_par_out[137]
  PIN a_par_out[138]
    DIRECTION OUTPUT ;
    USE SIGNAL ;
    PORT
      LAYER M5 ;
        RECT  67.344 25.836 67.368 25.92 ;
    END
  END a_par_out[138]
  PIN a_par_out[139]
    DIRECTION OUTPUT ;
    USE SIGNAL ;
    PORT
      LAYER M3 ;
        RECT  67.464 25.882 67.482 25.92 ;
    END
  END a_par_out[139]
  PIN a_par_out[13]
    DIRECTION OUTPUT ;
    USE SIGNAL ;
    PORT
      LAYER M3 ;
        RECT  27.828 25.882 27.846 25.92 ;
    END
  END a_par_out[13]
  PIN a_par_out[140]
    DIRECTION OUTPUT ;
    USE SIGNAL ;
    PORT
      LAYER M5 ;
        RECT  67.728 25.836 67.752 25.92 ;
    END
  END a_par_out[140]
  PIN a_par_out[141]
    DIRECTION OUTPUT ;
    USE SIGNAL ;
    PORT
      LAYER M3 ;
        RECT  67.968 25.882 67.986 25.92 ;
    END
  END a_par_out[141]
  PIN a_par_out[142]
    DIRECTION OUTPUT ;
    USE SIGNAL ;
    PORT
      LAYER M5 ;
        RECT  68.112 25.836 68.136 25.92 ;
    END
  END a_par_out[142]
  PIN a_par_out[143]
    DIRECTION OUTPUT ;
    USE SIGNAL ;
    PORT
      LAYER M3 ;
        RECT  68.328 25.882 68.346 25.92 ;
    END
  END a_par_out[143]
  PIN a_par_out[144]
    DIRECTION OUTPUT ;
    USE SIGNAL ;
    PORT
      LAYER M5 ;
        RECT  68.496 25.836 68.52 25.92 ;
    END
  END a_par_out[144]
  PIN a_par_out[145]
    DIRECTION OUTPUT ;
    USE SIGNAL ;
    PORT
      LAYER M3 ;
        RECT  68.724 25.882 68.742 25.92 ;
    END
  END a_par_out[145]
  PIN a_par_out[146]
    DIRECTION OUTPUT ;
    USE SIGNAL ;
    PORT
      LAYER M5 ;
        RECT  68.976 25.836 69 25.92 ;
    END
  END a_par_out[146]
  PIN a_par_out[147]
    DIRECTION OUTPUT ;
    USE SIGNAL ;
    PORT
      LAYER M3 ;
        RECT  69.12 25.882 69.138 25.92 ;
    END
  END a_par_out[147]
  PIN a_par_out[148]
    DIRECTION OUTPUT ;
    USE SIGNAL ;
    PORT
      LAYER M5 ;
        RECT  69.36 25.836 69.384 25.92 ;
    END
  END a_par_out[148]
  PIN a_par_out[149]
    DIRECTION OUTPUT ;
    USE SIGNAL ;
    PORT
      LAYER M3 ;
        RECT  69.588 25.882 69.606 25.92 ;
    END
  END a_par_out[149]
  PIN a_par_out[14]
    DIRECTION OUTPUT ;
    USE SIGNAL ;
    PORT
      LAYER M5 ;
        RECT  28.176 25.836 28.2 25.92 ;
    END
  END a_par_out[14]
  PIN a_par_out[150]
    DIRECTION OUTPUT ;
    USE SIGNAL ;
    PORT
      LAYER M5 ;
        RECT  69.744 25.836 69.768 25.92 ;
    END
  END a_par_out[150]
  PIN a_par_out[151]
    DIRECTION OUTPUT ;
    USE SIGNAL ;
    PORT
      LAYER M3 ;
        RECT  69.984 25.882 70.002 25.92 ;
    END
  END a_par_out[151]
  PIN a_par_out[152]
    DIRECTION OUTPUT ;
    USE SIGNAL ;
    PORT
      LAYER M5 ;
        RECT  70.128 25.836 70.152 25.92 ;
    END
  END a_par_out[152]
  PIN a_par_out[153]
    DIRECTION OUTPUT ;
    USE SIGNAL ;
    PORT
      LAYER M3 ;
        RECT  70.344 25.882 70.362 25.92 ;
    END
  END a_par_out[153]
  PIN a_par_out[154]
    DIRECTION OUTPUT ;
    USE SIGNAL ;
    PORT
      LAYER M5 ;
        RECT  70.608 25.836 70.632 25.92 ;
    END
  END a_par_out[154]
  PIN a_par_out[155]
    DIRECTION OUTPUT ;
    USE SIGNAL ;
    PORT
      LAYER M3 ;
        RECT  70.74 25.882 70.758 25.92 ;
    END
  END a_par_out[155]
  PIN a_par_out[156]
    DIRECTION OUTPUT ;
    USE SIGNAL ;
    PORT
      LAYER M5 ;
        RECT  70.992 25.836 71.016 25.92 ;
    END
  END a_par_out[156]
  PIN a_par_out[157]
    DIRECTION OUTPUT ;
    USE SIGNAL ;
    PORT
      LAYER M3 ;
        RECT  71.136 25.882 71.154 25.92 ;
    END
  END a_par_out[157]
  PIN a_par_out[158]
    DIRECTION OUTPUT ;
    USE SIGNAL ;
    PORT
      LAYER M5 ;
        RECT  71.376 25.836 71.4 25.92 ;
    END
  END a_par_out[158]
  PIN a_par_out[159]
    DIRECTION OUTPUT ;
    USE SIGNAL ;
    PORT
      LAYER M3 ;
        RECT  71.604 25.882 71.622 25.92 ;
    END
  END a_par_out[159]
  PIN a_par_out[15]
    DIRECTION OUTPUT ;
    USE SIGNAL ;
    PORT
      LAYER M3 ;
        RECT  28.584 25.882 28.602 25.92 ;
    END
  END a_par_out[15]
  PIN a_par_out[160]
    DIRECTION OUTPUT ;
    USE SIGNAL ;
    PORT
      LAYER M5 ;
        RECT  71.76 25.836 71.784 25.92 ;
    END
  END a_par_out[160]
  PIN a_par_out[161]
    DIRECTION OUTPUT ;
    USE SIGNAL ;
    PORT
      LAYER M3 ;
        RECT  72 25.882 72.018 25.92 ;
    END
  END a_par_out[161]
  PIN a_par_out[162]
    DIRECTION OUTPUT ;
    USE SIGNAL ;
    PORT
      LAYER M5 ;
        RECT  72.24 25.836 72.264 25.92 ;
    END
  END a_par_out[162]
  PIN a_par_out[163]
    DIRECTION OUTPUT ;
    USE SIGNAL ;
    PORT
      LAYER M3 ;
        RECT  72.36 25.882 72.378 25.92 ;
    END
  END a_par_out[163]
  PIN a_par_out[164]
    DIRECTION OUTPUT ;
    USE SIGNAL ;
    PORT
      LAYER M5 ;
        RECT  72.624 25.836 72.648 25.92 ;
    END
  END a_par_out[164]
  PIN a_par_out[165]
    DIRECTION OUTPUT ;
    USE SIGNAL ;
    PORT
      LAYER M3 ;
        RECT  72.756 25.882 72.774 25.92 ;
    END
  END a_par_out[165]
  PIN a_par_out[166]
    DIRECTION OUTPUT ;
    USE SIGNAL ;
    PORT
      LAYER M5 ;
        RECT  73.008 25.836 73.032 25.92 ;
    END
  END a_par_out[166]
  PIN a_par_out[167]
    DIRECTION OUTPUT ;
    USE SIGNAL ;
    PORT
      LAYER M3 ;
        RECT  73.224 25.882 73.242 25.92 ;
    END
  END a_par_out[167]
  PIN a_par_out[168]
    DIRECTION OUTPUT ;
    USE SIGNAL ;
    PORT
      LAYER M5 ;
        RECT  73.392 25.836 73.416 25.92 ;
    END
  END a_par_out[168]
  PIN a_par_out[169]
    DIRECTION OUTPUT ;
    USE SIGNAL ;
    PORT
      LAYER M3 ;
        RECT  73.62 25.882 73.638 25.92 ;
    END
  END a_par_out[169]
  PIN a_par_out[16]
    DIRECTION OUTPUT ;
    USE SIGNAL ;
    PORT
      LAYER M5 ;
        RECT  29.04 25.836 29.064 25.92 ;
    END
  END a_par_out[16]
  PIN a_par_out[170]
    DIRECTION OUTPUT ;
    USE SIGNAL ;
    PORT
      LAYER M5 ;
        RECT  73.776 25.836 73.8 25.92 ;
    END
  END a_par_out[170]
  PIN a_par_out[171]
    DIRECTION OUTPUT ;
    USE SIGNAL ;
    PORT
      LAYER M3 ;
        RECT  74.016 25.882 74.034 25.92 ;
    END
  END a_par_out[171]
  PIN a_par_out[172]
    DIRECTION OUTPUT ;
    USE SIGNAL ;
    PORT
      LAYER M5 ;
        RECT  74.256 25.836 74.28 25.92 ;
    END
  END a_par_out[172]
  PIN a_par_out[173]
    DIRECTION OUTPUT ;
    USE SIGNAL ;
    PORT
      LAYER M3 ;
        RECT  74.376 25.882 74.394 25.92 ;
    END
  END a_par_out[173]
  PIN a_par_out[174]
    DIRECTION OUTPUT ;
    USE SIGNAL ;
    PORT
      LAYER M5 ;
        RECT  74.64 25.836 74.664 25.92 ;
    END
  END a_par_out[174]
  PIN a_par_out[175]
    DIRECTION OUTPUT ;
    USE SIGNAL ;
    PORT
      LAYER M3 ;
        RECT  74.88 25.882 74.898 25.92 ;
    END
  END a_par_out[175]
  PIN a_par_out[176]
    DIRECTION OUTPUT ;
    USE SIGNAL ;
    PORT
      LAYER M5 ;
        RECT  75.024 25.836 75.048 25.92 ;
    END
  END a_par_out[176]
  PIN a_par_out[177]
    DIRECTION OUTPUT ;
    USE SIGNAL ;
    PORT
      LAYER M3 ;
        RECT  75.24 25.882 75.258 25.92 ;
    END
  END a_par_out[177]
  PIN a_par_out[178]
    DIRECTION OUTPUT ;
    USE SIGNAL ;
    PORT
      LAYER M5 ;
        RECT  75.408 25.836 75.432 25.92 ;
    END
  END a_par_out[178]
  PIN a_par_out[179]
    DIRECTION OUTPUT ;
    USE SIGNAL ;
    PORT
      LAYER M3 ;
        RECT  75.636 25.882 75.654 25.92 ;
    END
  END a_par_out[179]
  PIN a_par_out[17]
    DIRECTION OUTPUT ;
    USE SIGNAL ;
    PORT
      LAYER M3 ;
        RECT  29.376 25.882 29.394 25.92 ;
    END
  END a_par_out[17]
  PIN a_par_out[180]
    DIRECTION OUTPUT ;
    USE SIGNAL ;
    PORT
      LAYER M5 ;
        RECT  75.888 25.836 75.912 25.92 ;
    END
  END a_par_out[180]
  PIN a_par_out[181]
    DIRECTION OUTPUT ;
    USE SIGNAL ;
    PORT
      LAYER M3 ;
        RECT  76.032 25.882 76.05 25.92 ;
    END
  END a_par_out[181]
  PIN a_par_out[182]
    DIRECTION OUTPUT ;
    USE SIGNAL ;
    PORT
      LAYER M5 ;
        RECT  76.272 25.836 76.296 25.92 ;
    END
  END a_par_out[182]
  PIN a_par_out[183]
    DIRECTION OUTPUT ;
    USE SIGNAL ;
    PORT
      LAYER M3 ;
        RECT  76.392 25.882 76.41 25.92 ;
    END
  END a_par_out[183]
  PIN a_par_out[184]
    DIRECTION OUTPUT ;
    USE SIGNAL ;
    PORT
      LAYER M5 ;
        RECT  76.656 25.836 76.68 25.92 ;
    END
  END a_par_out[184]
  PIN a_par_out[185]
    DIRECTION OUTPUT ;
    USE SIGNAL ;
    PORT
      LAYER M3 ;
        RECT  76.896 25.882 76.914 25.92 ;
    END
  END a_par_out[185]
  PIN a_par_out[186]
    DIRECTION OUTPUT ;
    USE SIGNAL ;
    PORT
      LAYER M5 ;
        RECT  77.04 25.836 77.064 25.92 ;
    END
  END a_par_out[186]
  PIN a_par_out[187]
    DIRECTION OUTPUT ;
    USE SIGNAL ;
    PORT
      LAYER M3 ;
        RECT  77.256 25.882 77.274 25.92 ;
    END
  END a_par_out[187]
  PIN a_par_out[188]
    DIRECTION OUTPUT ;
    USE SIGNAL ;
    PORT
      LAYER M5 ;
        RECT  77.52 25.836 77.544 25.92 ;
    END
  END a_par_out[188]
  PIN a_par_out[189]
    DIRECTION OUTPUT ;
    USE SIGNAL ;
    PORT
      LAYER M3 ;
        RECT  77.652 25.882 77.67 25.92 ;
    END
  END a_par_out[189]
  PIN a_par_out[18]
    DIRECTION OUTPUT ;
    USE SIGNAL ;
    PORT
      LAYER M5 ;
        RECT  29.808 25.836 29.832 25.92 ;
    END
  END a_par_out[18]
  PIN a_par_out[190]
    DIRECTION OUTPUT ;
    USE SIGNAL ;
    PORT
      LAYER M5 ;
        RECT  77.904 25.836 77.928 25.92 ;
    END
  END a_par_out[190]
  PIN a_par_out[191]
    DIRECTION OUTPUT ;
    USE SIGNAL ;
    PORT
      LAYER M3 ;
        RECT  78.048 25.882 78.066 25.92 ;
    END
  END a_par_out[191]
  PIN a_par_out[192]
    DIRECTION OUTPUT ;
    USE SIGNAL ;
    PORT
      LAYER M5 ;
        RECT  78.288 25.836 78.312 25.92 ;
    END
  END a_par_out[192]
  PIN a_par_out[193]
    DIRECTION OUTPUT ;
    USE SIGNAL ;
    PORT
      LAYER M3 ;
        RECT  78.516 25.882 78.534 25.92 ;
    END
  END a_par_out[193]
  PIN a_par_out[194]
    DIRECTION OUTPUT ;
    USE SIGNAL ;
    PORT
      LAYER M5 ;
        RECT  78.672 25.836 78.696 25.92 ;
    END
  END a_par_out[194]
  PIN a_par_out[195]
    DIRECTION OUTPUT ;
    USE SIGNAL ;
    PORT
      LAYER M3 ;
        RECT  78.912 25.882 78.93 25.92 ;
    END
  END a_par_out[195]
  PIN a_par_out[196]
    DIRECTION OUTPUT ;
    USE SIGNAL ;
    PORT
      LAYER M5 ;
        RECT  79.056 25.836 79.08 25.92 ;
    END
  END a_par_out[196]
  PIN a_par_out[197]
    DIRECTION OUTPUT ;
    USE SIGNAL ;
    PORT
      LAYER M3 ;
        RECT  79.272 25.882 79.29 25.92 ;
    END
  END a_par_out[197]
  PIN a_par_out[198]
    DIRECTION OUTPUT ;
    USE SIGNAL ;
    PORT
      LAYER M5 ;
        RECT  79.536 25.836 79.56 25.92 ;
    END
  END a_par_out[198]
  PIN a_par_out[199]
    DIRECTION OUTPUT ;
    USE SIGNAL ;
    PORT
      LAYER M3 ;
        RECT  79.668 25.882 79.686 25.92 ;
    END
  END a_par_out[199]
  PIN a_par_out[19]
    DIRECTION OUTPUT ;
    USE SIGNAL ;
    PORT
      LAYER M3 ;
        RECT  30.24 25.882 30.258 25.92 ;
    END
  END a_par_out[19]
  PIN a_par_out[1]
    DIRECTION OUTPUT ;
    USE SIGNAL ;
    PORT
      LAYER M3 ;
        RECT  22.932 25.882 22.95 25.92 ;
    END
  END a_par_out[1]
  PIN a_par_out[200]
    DIRECTION OUTPUT ;
    USE SIGNAL ;
    PORT
      LAYER M5 ;
        RECT  79.92 25.836 79.944 25.92 ;
    END
  END a_par_out[200]
  PIN a_par_out[201]
    DIRECTION OUTPUT ;
    USE SIGNAL ;
    PORT
      LAYER M3 ;
        RECT  80.136 25.882 80.154 25.92 ;
    END
  END a_par_out[201]
  PIN a_par_out[202]
    DIRECTION OUTPUT ;
    USE SIGNAL ;
    PORT
      LAYER M5 ;
        RECT  80.304 25.836 80.328 25.92 ;
    END
  END a_par_out[202]
  PIN a_par_out[203]
    DIRECTION OUTPUT ;
    USE SIGNAL ;
    PORT
      LAYER M3 ;
        RECT  80.532 25.882 80.55 25.92 ;
    END
  END a_par_out[203]
  PIN a_par_out[204]
    DIRECTION OUTPUT ;
    USE SIGNAL ;
    PORT
      LAYER M5 ;
        RECT  80.688 25.836 80.712 25.92 ;
    END
  END a_par_out[204]
  PIN a_par_out[205]
    DIRECTION OUTPUT ;
    USE SIGNAL ;
    PORT
      LAYER M3 ;
        RECT  80.928 25.882 80.946 25.92 ;
    END
  END a_par_out[205]
  PIN a_par_out[206]
    DIRECTION OUTPUT ;
    USE SIGNAL ;
    PORT
      LAYER M5 ;
        RECT  81.168 25.836 81.192 25.92 ;
    END
  END a_par_out[206]
  PIN a_par_out[207]
    DIRECTION OUTPUT ;
    USE SIGNAL ;
    PORT
      LAYER M3 ;
        RECT  81.288 25.882 81.306 25.92 ;
    END
  END a_par_out[207]
  PIN a_par_out[208]
    DIRECTION OUTPUT ;
    USE SIGNAL ;
    PORT
      LAYER M5 ;
        RECT  81.552 25.836 81.576 25.92 ;
    END
  END a_par_out[208]
  PIN a_par_out[209]
    DIRECTION OUTPUT ;
    USE SIGNAL ;
    PORT
      LAYER M3 ;
        RECT  81.792 25.882 81.81 25.92 ;
    END
  END a_par_out[209]
  PIN a_par_out[20]
    DIRECTION OUTPUT ;
    USE SIGNAL ;
    PORT
      LAYER M5 ;
        RECT  30.672 25.836 30.696 25.92 ;
    END
  END a_par_out[20]
  PIN a_par_out[210]
    DIRECTION OUTPUT ;
    USE SIGNAL ;
    PORT
      LAYER M5 ;
        RECT  81.936 25.836 81.96 25.92 ;
    END
  END a_par_out[210]
  PIN a_par_out[211]
    DIRECTION OUTPUT ;
    USE SIGNAL ;
    PORT
      LAYER M3 ;
        RECT  82.152 25.882 82.17 25.92 ;
    END
  END a_par_out[211]
  PIN a_par_out[212]
    DIRECTION OUTPUT ;
    USE SIGNAL ;
    PORT
      LAYER M5 ;
        RECT  82.32 25.836 82.344 25.92 ;
    END
  END a_par_out[212]
  PIN a_par_out[213]
    DIRECTION OUTPUT ;
    USE SIGNAL ;
    PORT
      LAYER M3 ;
        RECT  82.548 25.882 82.566 25.92 ;
    END
  END a_par_out[213]
  PIN a_par_out[214]
    DIRECTION OUTPUT ;
    USE SIGNAL ;
    PORT
      LAYER M5 ;
        RECT  82.8 25.836 82.824 25.92 ;
    END
  END a_par_out[214]
  PIN a_par_out[215]
    DIRECTION OUTPUT ;
    USE SIGNAL ;
    PORT
      LAYER M3 ;
        RECT  82.944 25.882 82.962 25.92 ;
    END
  END a_par_out[215]
  PIN a_par_out[216]
    DIRECTION OUTPUT ;
    USE SIGNAL ;
    PORT
      LAYER M5 ;
        RECT  83.184 25.836 83.208 25.92 ;
    END
  END a_par_out[216]
  PIN a_par_out[217]
    DIRECTION OUTPUT ;
    USE SIGNAL ;
    PORT
      LAYER M3 ;
        RECT  83.304 25.882 83.322 25.92 ;
    END
  END a_par_out[217]
  PIN a_par_out[218]
    DIRECTION OUTPUT ;
    USE SIGNAL ;
    PORT
      LAYER M5 ;
        RECT  83.568 25.836 83.592 25.92 ;
    END
  END a_par_out[218]
  PIN a_par_out[219]
    DIRECTION OUTPUT ;
    USE SIGNAL ;
    PORT
      LAYER M3 ;
        RECT  83.808 25.882 83.826 25.92 ;
    END
  END a_par_out[219]
  PIN a_par_out[21]
    DIRECTION OUTPUT ;
    USE SIGNAL ;
    PORT
      LAYER M3 ;
        RECT  30.996 25.882 31.014 25.92 ;
    END
  END a_par_out[21]
  PIN a_par_out[220]
    DIRECTION OUTPUT ;
    USE SIGNAL ;
    PORT
      LAYER M5 ;
        RECT  83.952 25.836 83.976 25.92 ;
    END
  END a_par_out[220]
  PIN a_par_out[221]
    DIRECTION OUTPUT ;
    USE SIGNAL ;
    PORT
      LAYER M3 ;
        RECT  84.168 25.882 84.186 25.92 ;
    END
  END a_par_out[221]
  PIN a_par_out[222]
    DIRECTION OUTPUT ;
    USE SIGNAL ;
    PORT
      LAYER M5 ;
        RECT  84.432 25.836 84.456 25.92 ;
    END
  END a_par_out[222]
  PIN a_par_out[223]
    DIRECTION OUTPUT ;
    USE SIGNAL ;
    PORT
      LAYER M3 ;
        RECT  84.564 25.882 84.582 25.92 ;
    END
  END a_par_out[223]
  PIN a_par_out[224]
    DIRECTION OUTPUT ;
    USE SIGNAL ;
    PORT
      LAYER M5 ;
        RECT  84.816 25.836 84.84 25.92 ;
    END
  END a_par_out[224]
  PIN a_par_out[225]
    DIRECTION OUTPUT ;
    USE SIGNAL ;
    PORT
      LAYER M3 ;
        RECT  84.96 25.882 84.978 25.92 ;
    END
  END a_par_out[225]
  PIN a_par_out[226]
    DIRECTION OUTPUT ;
    USE SIGNAL ;
    PORT
      LAYER M5 ;
        RECT  85.2 25.836 85.224 25.92 ;
    END
  END a_par_out[226]
  PIN a_par_out[227]
    DIRECTION OUTPUT ;
    USE SIGNAL ;
    PORT
      LAYER M3 ;
        RECT  85.428 25.882 85.446 25.92 ;
    END
  END a_par_out[227]
  PIN a_par_out[228]
    DIRECTION OUTPUT ;
    USE SIGNAL ;
    PORT
      LAYER M5 ;
        RECT  85.584 25.836 85.608 25.92 ;
    END
  END a_par_out[228]
  PIN a_par_out[229]
    DIRECTION OUTPUT ;
    USE SIGNAL ;
    PORT
      LAYER M3 ;
        RECT  85.824 25.882 85.842 25.92 ;
    END
  END a_par_out[229]
  PIN a_par_out[22]
    DIRECTION OUTPUT ;
    USE SIGNAL ;
    PORT
      LAYER M5 ;
        RECT  31.44 25.836 31.464 25.92 ;
    END
  END a_par_out[22]
  PIN a_par_out[230]
    DIRECTION OUTPUT ;
    USE SIGNAL ;
    PORT
      LAYER M5 ;
        RECT  85.968 25.836 85.992 25.92 ;
    END
  END a_par_out[230]
  PIN a_par_out[231]
    DIRECTION OUTPUT ;
    USE SIGNAL ;
    PORT
      LAYER M3 ;
        RECT  86.184 25.882 86.202 25.92 ;
    END
  END a_par_out[231]
  PIN a_par_out[232]
    DIRECTION OUTPUT ;
    USE SIGNAL ;
    PORT
      LAYER M5 ;
        RECT  86.448 25.836 86.472 25.92 ;
    END
  END a_par_out[232]
  PIN a_par_out[233]
    DIRECTION OUTPUT ;
    USE SIGNAL ;
    PORT
      LAYER M3 ;
        RECT  86.58 25.882 86.598 25.92 ;
    END
  END a_par_out[233]
  PIN a_par_out[234]
    DIRECTION OUTPUT ;
    USE SIGNAL ;
    PORT
      LAYER M5 ;
        RECT  86.832 25.836 86.856 25.92 ;
    END
  END a_par_out[234]
  PIN a_par_out[235]
    DIRECTION OUTPUT ;
    USE SIGNAL ;
    PORT
      LAYER M3 ;
        RECT  87.048 25.882 87.066 25.92 ;
    END
  END a_par_out[235]
  PIN a_par_out[236]
    DIRECTION OUTPUT ;
    USE SIGNAL ;
    PORT
      LAYER M5 ;
        RECT  87.216 25.836 87.24 25.92 ;
    END
  END a_par_out[236]
  PIN a_par_out[237]
    DIRECTION OUTPUT ;
    USE SIGNAL ;
    PORT
      LAYER M3 ;
        RECT  87.444 25.882 87.462 25.92 ;
    END
  END a_par_out[237]
  PIN a_par_out[238]
    DIRECTION OUTPUT ;
    USE SIGNAL ;
    PORT
      LAYER M5 ;
        RECT  87.6 25.836 87.624 25.92 ;
    END
  END a_par_out[238]
  PIN a_par_out[239]
    DIRECTION OUTPUT ;
    USE SIGNAL ;
    PORT
      LAYER M3 ;
        RECT  87.84 25.882 87.858 25.92 ;
    END
  END a_par_out[239]
  PIN a_par_out[23]
    DIRECTION OUTPUT ;
    USE SIGNAL ;
    PORT
      LAYER M3 ;
        RECT  31.86 25.882 31.878 25.92 ;
    END
  END a_par_out[23]
  PIN a_par_out[240]
    DIRECTION OUTPUT ;
    USE SIGNAL ;
    PORT
      LAYER M5 ;
        RECT  88.08 25.836 88.104 25.92 ;
    END
  END a_par_out[240]
  PIN a_par_out[241]
    DIRECTION OUTPUT ;
    USE SIGNAL ;
    PORT
      LAYER M3 ;
        RECT  88.2 25.882 88.218 25.92 ;
    END
  END a_par_out[241]
  PIN a_par_out[242]
    DIRECTION OUTPUT ;
    USE SIGNAL ;
    PORT
      LAYER M5 ;
        RECT  88.464 25.836 88.488 25.92 ;
    END
  END a_par_out[242]
  PIN a_par_out[243]
    DIRECTION OUTPUT ;
    USE SIGNAL ;
    PORT
      LAYER M3 ;
        RECT  88.596 25.882 88.614 25.92 ;
    END
  END a_par_out[243]
  PIN a_par_out[244]
    DIRECTION OUTPUT ;
    USE SIGNAL ;
    PORT
      LAYER M5 ;
        RECT  88.848 25.836 88.872 25.92 ;
    END
  END a_par_out[244]
  PIN a_par_out[245]
    DIRECTION OUTPUT ;
    USE SIGNAL ;
    PORT
      LAYER M3 ;
        RECT  89.064 25.882 89.082 25.92 ;
    END
  END a_par_out[245]
  PIN a_par_out[246]
    DIRECTION OUTPUT ;
    USE SIGNAL ;
    PORT
      LAYER M5 ;
        RECT  89.232 25.836 89.256 25.92 ;
    END
  END a_par_out[246]
  PIN a_par_out[247]
    DIRECTION OUTPUT ;
    USE SIGNAL ;
    PORT
      LAYER M3 ;
        RECT  89.46 25.882 89.478 25.92 ;
    END
  END a_par_out[247]
  PIN a_par_out[248]
    DIRECTION OUTPUT ;
    USE SIGNAL ;
    PORT
      LAYER M5 ;
        RECT  89.712 25.836 89.736 25.92 ;
    END
  END a_par_out[248]
  PIN a_par_out[249]
    DIRECTION OUTPUT ;
    USE SIGNAL ;
    PORT
      LAYER M3 ;
        RECT  89.856 25.882 89.874 25.92 ;
    END
  END a_par_out[249]
  PIN a_par_out[24]
    DIRECTION OUTPUT ;
    USE SIGNAL ;
    PORT
      LAYER M5 ;
        RECT  32.304 25.836 32.328 25.92 ;
    END
  END a_par_out[24]
  PIN a_par_out[250]
    DIRECTION OUTPUT ;
    USE SIGNAL ;
    PORT
      LAYER M5 ;
        RECT  90.096 25.836 90.12 25.92 ;
    END
  END a_par_out[250]
  PIN a_par_out[251]
    DIRECTION OUTPUT ;
    USE SIGNAL ;
    PORT
      LAYER M3 ;
        RECT  90.216 25.882 90.234 25.92 ;
    END
  END a_par_out[251]
  PIN a_par_out[252]
    DIRECTION OUTPUT ;
    USE SIGNAL ;
    PORT
      LAYER M5 ;
        RECT  90.48 25.836 90.504 25.92 ;
    END
  END a_par_out[252]
  PIN a_par_out[253]
    DIRECTION OUTPUT ;
    USE SIGNAL ;
    PORT
      LAYER M3 ;
        RECT  90.72 25.882 90.738 25.92 ;
    END
  END a_par_out[253]
  PIN a_par_out[254]
    DIRECTION OUTPUT ;
    USE SIGNAL ;
    PORT
      LAYER M5 ;
        RECT  90.864 25.836 90.888 25.92 ;
    END
  END a_par_out[254]
  PIN a_par_out[255]
    DIRECTION OUTPUT ;
    USE SIGNAL ;
    PORT
      LAYER M3 ;
        RECT  91.08 25.882 91.098 25.92 ;
    END
  END a_par_out[255]
  PIN a_par_out[25]
    DIRECTION OUTPUT ;
    USE SIGNAL ;
    PORT
      LAYER M3 ;
        RECT  32.616 25.882 32.634 25.92 ;
    END
  END a_par_out[25]
  PIN a_par_out[26]
    DIRECTION OUTPUT ;
    USE SIGNAL ;
    PORT
      LAYER M5 ;
        RECT  33.072 25.836 33.096 25.92 ;
    END
  END a_par_out[26]
  PIN a_par_out[27]
    DIRECTION OUTPUT ;
    USE SIGNAL ;
    PORT
      LAYER M3 ;
        RECT  33.48 25.882 33.498 25.92 ;
    END
  END a_par_out[27]
  PIN a_par_out[28]
    DIRECTION OUTPUT ;
    USE SIGNAL ;
    PORT
      LAYER M5 ;
        RECT  33.936 25.836 33.96 25.92 ;
    END
  END a_par_out[28]
  PIN a_par_out[29]
    DIRECTION OUTPUT ;
    USE SIGNAL ;
    PORT
      LAYER M3 ;
        RECT  34.272 25.882 34.29 25.92 ;
    END
  END a_par_out[29]
  PIN a_par_out[2]
    DIRECTION OUTPUT ;
    USE SIGNAL ;
    PORT
      LAYER M5 ;
        RECT  23.28 25.836 23.304 25.92 ;
    END
  END a_par_out[2]
  PIN a_par_out[30]
    DIRECTION OUTPUT ;
    USE SIGNAL ;
    PORT
      LAYER M5 ;
        RECT  34.704 25.836 34.728 25.92 ;
    END
  END a_par_out[30]
  PIN a_par_out[31]
    DIRECTION OUTPUT ;
    USE SIGNAL ;
    PORT
      LAYER M3 ;
        RECT  35.136 25.882 35.154 25.92 ;
    END
  END a_par_out[31]
  PIN a_par_out[32]
    DIRECTION OUTPUT ;
    USE SIGNAL ;
    PORT
      LAYER M5 ;
        RECT  35.472 25.836 35.496 25.92 ;
    END
  END a_par_out[32]
  PIN a_par_out[33]
    DIRECTION OUTPUT ;
    USE SIGNAL ;
    PORT
      LAYER M3 ;
        RECT  35.892 25.882 35.91 25.92 ;
    END
  END a_par_out[33]
  PIN a_par_out[34]
    DIRECTION OUTPUT ;
    USE SIGNAL ;
    PORT
      LAYER M5 ;
        RECT  36.336 25.836 36.36 25.92 ;
    END
  END a_par_out[34]
  PIN a_par_out[35]
    DIRECTION OUTPUT ;
    USE SIGNAL ;
    PORT
      LAYER M3 ;
        RECT  36.756 25.882 36.774 25.92 ;
    END
  END a_par_out[35]
  PIN a_par_out[36]
    DIRECTION OUTPUT ;
    USE SIGNAL ;
    PORT
      LAYER M5 ;
        RECT  37.104 25.836 37.128 25.92 ;
    END
  END a_par_out[36]
  PIN a_par_out[37]
    DIRECTION OUTPUT ;
    USE SIGNAL ;
    PORT
      LAYER M3 ;
        RECT  37.512 25.882 37.53 25.92 ;
    END
  END a_par_out[37]
  PIN a_par_out[38]
    DIRECTION OUTPUT ;
    USE SIGNAL ;
    PORT
      LAYER M5 ;
        RECT  37.968 25.836 37.992 25.92 ;
    END
  END a_par_out[38]
  PIN a_par_out[39]
    DIRECTION OUTPUT ;
    USE SIGNAL ;
    PORT
      LAYER M3 ;
        RECT  38.376 25.882 38.394 25.92 ;
    END
  END a_par_out[39]
  PIN a_par_out[3]
    DIRECTION OUTPUT ;
    USE SIGNAL ;
    PORT
      LAYER M3 ;
        RECT  23.688 25.882 23.706 25.92 ;
    END
  END a_par_out[3]
  PIN a_par_out[40]
    DIRECTION OUTPUT ;
    USE SIGNAL ;
    PORT
      LAYER M5 ;
        RECT  38.736 25.836 38.76 25.92 ;
    END
  END a_par_out[40]
  PIN a_par_out[41]
    DIRECTION OUTPUT ;
    USE SIGNAL ;
    PORT
      LAYER M3 ;
        RECT  39.168 25.882 39.186 25.92 ;
    END
  END a_par_out[41]
  PIN a_par_out[42]
    DIRECTION OUTPUT ;
    USE SIGNAL ;
    PORT
      LAYER M5 ;
        RECT  39.6 25.836 39.624 25.92 ;
    END
  END a_par_out[42]
  PIN a_par_out[43]
    DIRECTION OUTPUT ;
    USE SIGNAL ;
    PORT
      LAYER M3 ;
        RECT  40.032 25.882 40.05 25.92 ;
    END
  END a_par_out[43]
  PIN a_par_out[44]
    DIRECTION OUTPUT ;
    USE SIGNAL ;
    PORT
      LAYER M5 ;
        RECT  40.368 25.836 40.392 25.92 ;
    END
  END a_par_out[44]
  PIN a_par_out[45]
    DIRECTION OUTPUT ;
    USE SIGNAL ;
    PORT
      LAYER M3 ;
        RECT  40.788 25.882 40.806 25.92 ;
    END
  END a_par_out[45]
  PIN a_par_out[46]
    DIRECTION OUTPUT ;
    USE SIGNAL ;
    PORT
      LAYER M5 ;
        RECT  41.232 25.836 41.256 25.92 ;
    END
  END a_par_out[46]
  PIN a_par_out[47]
    DIRECTION OUTPUT ;
    USE SIGNAL ;
    PORT
      LAYER M3 ;
        RECT  41.544 25.882 41.562 25.92 ;
    END
  END a_par_out[47]
  PIN a_par_out[48]
    DIRECTION OUTPUT ;
    USE SIGNAL ;
    PORT
      LAYER M5 ;
        RECT  42 25.836 42.024 25.92 ;
    END
  END a_par_out[48]
  PIN a_par_out[49]
    DIRECTION OUTPUT ;
    USE SIGNAL ;
    PORT
      LAYER M3 ;
        RECT  42.408 25.882 42.426 25.92 ;
    END
  END a_par_out[49]
  PIN a_par_out[4]
    DIRECTION OUTPUT ;
    USE SIGNAL ;
    PORT
      LAYER M5 ;
        RECT  24.144 25.836 24.168 25.92 ;
    END
  END a_par_out[4]
  PIN a_par_out[50]
    DIRECTION OUTPUT ;
    USE SIGNAL ;
    PORT
      LAYER M5 ;
        RECT  42.864 25.836 42.888 25.92 ;
    END
  END a_par_out[50]
  PIN a_par_out[51]
    DIRECTION OUTPUT ;
    USE SIGNAL ;
    PORT
      LAYER M3 ;
        RECT  43.2 25.882 43.218 25.92 ;
    END
  END a_par_out[51]
  PIN a_par_out[52]
    DIRECTION OUTPUT ;
    USE SIGNAL ;
    PORT
      LAYER M5 ;
        RECT  43.632 25.836 43.656 25.92 ;
    END
  END a_par_out[52]
  PIN a_par_out[53]
    DIRECTION OUTPUT ;
    USE SIGNAL ;
    PORT
      LAYER M3 ;
        RECT  44.064 25.882 44.082 25.92 ;
    END
  END a_par_out[53]
  PIN a_par_out[54]
    DIRECTION OUTPUT ;
    USE SIGNAL ;
    PORT
      LAYER M5 ;
        RECT  44.496 25.836 44.52 25.92 ;
    END
  END a_par_out[54]
  PIN a_par_out[55]
    DIRECTION OUTPUT ;
    USE SIGNAL ;
    PORT
      LAYER M3 ;
        RECT  44.82 25.882 44.838 25.92 ;
    END
  END a_par_out[55]
  PIN a_par_out[56]
    DIRECTION OUTPUT ;
    USE SIGNAL ;
    PORT
      LAYER M5 ;
        RECT  45.264 25.836 45.288 25.92 ;
    END
  END a_par_out[56]
  PIN a_par_out[57]
    DIRECTION OUTPUT ;
    USE SIGNAL ;
    PORT
      LAYER M3 ;
        RECT  45.684 25.882 45.702 25.92 ;
    END
  END a_par_out[57]
  PIN a_par_out[58]
    DIRECTION OUTPUT ;
    USE SIGNAL ;
    PORT
      LAYER M5 ;
        RECT  46.128 25.836 46.152 25.92 ;
    END
  END a_par_out[58]
  PIN a_par_out[59]
    DIRECTION OUTPUT ;
    USE SIGNAL ;
    PORT
      LAYER M3 ;
        RECT  46.44 25.882 46.458 25.92 ;
    END
  END a_par_out[59]
  PIN a_par_out[5]
    DIRECTION OUTPUT ;
    USE SIGNAL ;
    PORT
      LAYER M3 ;
        RECT  24.552 25.882 24.57 25.92 ;
    END
  END a_par_out[5]
  PIN a_par_out[60]
    DIRECTION OUTPUT ;
    USE SIGNAL ;
    PORT
      LAYER M5 ;
        RECT  46.896 25.836 46.92 25.92 ;
    END
  END a_par_out[60]
  PIN a_par_out[61]
    DIRECTION OUTPUT ;
    USE SIGNAL ;
    PORT
      LAYER M3 ;
        RECT  47.304 25.882 47.322 25.92 ;
    END
  END a_par_out[61]
  PIN a_par_out[62]
    DIRECTION OUTPUT ;
    USE SIGNAL ;
    PORT
      LAYER M5 ;
        RECT  47.664 25.836 47.688 25.92 ;
    END
  END a_par_out[62]
  PIN a_par_out[63]
    DIRECTION OUTPUT ;
    USE SIGNAL ;
    PORT
      LAYER M3 ;
        RECT  48.096 25.882 48.114 25.92 ;
    END
  END a_par_out[63]
  PIN a_par_out[64]
    DIRECTION OUTPUT ;
    USE SIGNAL ;
    PORT
      LAYER M5 ;
        RECT  48.528 25.836 48.552 25.92 ;
    END
  END a_par_out[64]
  PIN a_par_out[65]
    DIRECTION OUTPUT ;
    USE SIGNAL ;
    PORT
      LAYER M3 ;
        RECT  48.96 25.882 48.978 25.92 ;
    END
  END a_par_out[65]
  PIN a_par_out[66]
    DIRECTION OUTPUT ;
    USE SIGNAL ;
    PORT
      LAYER M5 ;
        RECT  49.296 25.836 49.32 25.92 ;
    END
  END a_par_out[66]
  PIN a_par_out[67]
    DIRECTION OUTPUT ;
    USE SIGNAL ;
    PORT
      LAYER M3 ;
        RECT  49.716 25.882 49.734 25.92 ;
    END
  END a_par_out[67]
  PIN a_par_out[68]
    DIRECTION OUTPUT ;
    USE SIGNAL ;
    PORT
      LAYER M5 ;
        RECT  50.16 25.836 50.184 25.92 ;
    END
  END a_par_out[68]
  PIN a_par_out[69]
    DIRECTION OUTPUT ;
    USE SIGNAL ;
    PORT
      LAYER M3 ;
        RECT  50.58 25.882 50.598 25.92 ;
    END
  END a_par_out[69]
  PIN a_par_out[6]
    DIRECTION OUTPUT ;
    USE SIGNAL ;
    PORT
      LAYER M5 ;
        RECT  24.912 25.836 24.936 25.92 ;
    END
  END a_par_out[6]
  PIN a_par_out[70]
    DIRECTION OUTPUT ;
    USE SIGNAL ;
    PORT
      LAYER M5 ;
        RECT  50.928 25.836 50.952 25.92 ;
    END
  END a_par_out[70]
  PIN a_par_out[71]
    DIRECTION OUTPUT ;
    USE SIGNAL ;
    PORT
      LAYER M3 ;
        RECT  51.336 25.882 51.354 25.92 ;
    END
  END a_par_out[71]
  PIN a_par_out[72]
    DIRECTION OUTPUT ;
    USE SIGNAL ;
    PORT
      LAYER M5 ;
        RECT  51.792 25.836 51.816 25.92 ;
    END
  END a_par_out[72]
  PIN a_par_out[73]
    DIRECTION OUTPUT ;
    USE SIGNAL ;
    PORT
      LAYER M3 ;
        RECT  52.2 25.882 52.218 25.92 ;
    END
  END a_par_out[73]
  PIN a_par_out[74]
    DIRECTION OUTPUT ;
    USE SIGNAL ;
    PORT
      LAYER M5 ;
        RECT  52.56 25.836 52.584 25.92 ;
    END
  END a_par_out[74]
  PIN a_par_out[75]
    DIRECTION OUTPUT ;
    USE SIGNAL ;
    PORT
      LAYER M3 ;
        RECT  52.992 25.882 53.01 25.92 ;
    END
  END a_par_out[75]
  PIN a_par_out[76]
    DIRECTION OUTPUT ;
    USE SIGNAL ;
    PORT
      LAYER M5 ;
        RECT  53.424 25.836 53.448 25.92 ;
    END
  END a_par_out[76]
  PIN a_par_out[77]
    DIRECTION OUTPUT ;
    USE SIGNAL ;
    PORT
      LAYER M3 ;
        RECT  53.748 25.882 53.766 25.92 ;
    END
  END a_par_out[77]
  PIN a_par_out[78]
    DIRECTION OUTPUT ;
    USE SIGNAL ;
    PORT
      LAYER M5 ;
        RECT  54.192 25.836 54.216 25.92 ;
    END
  END a_par_out[78]
  PIN a_par_out[79]
    DIRECTION OUTPUT ;
    USE SIGNAL ;
    PORT
      LAYER M3 ;
        RECT  54.612 25.882 54.63 25.92 ;
    END
  END a_par_out[79]
  PIN a_par_out[7]
    DIRECTION OUTPUT ;
    USE SIGNAL ;
    PORT
      LAYER M3 ;
        RECT  25.344 25.882 25.362 25.92 ;
    END
  END a_par_out[7]
  PIN a_par_out[80]
    DIRECTION OUTPUT ;
    USE SIGNAL ;
    PORT
      LAYER M5 ;
        RECT  55.056 25.836 55.08 25.92 ;
    END
  END a_par_out[80]
  PIN a_par_out[81]
    DIRECTION OUTPUT ;
    USE SIGNAL ;
    PORT
      LAYER M3 ;
        RECT  55.368 25.882 55.386 25.92 ;
    END
  END a_par_out[81]
  PIN a_par_out[82]
    DIRECTION OUTPUT ;
    USE SIGNAL ;
    PORT
      LAYER M5 ;
        RECT  55.824 25.836 55.848 25.92 ;
    END
  END a_par_out[82]
  PIN a_par_out[83]
    DIRECTION OUTPUT ;
    USE SIGNAL ;
    PORT
      LAYER M3 ;
        RECT  56.16 25.882 56.178 25.92 ;
    END
  END a_par_out[83]
  PIN a_par_out[84]
    DIRECTION OUTPUT ;
    USE SIGNAL ;
    PORT
      LAYER M5 ;
        RECT  56.304 25.836 56.328 25.92 ;
    END
  END a_par_out[84]
  PIN a_par_out[85]
    DIRECTION OUTPUT ;
    USE SIGNAL ;
    PORT
      LAYER M3 ;
        RECT  56.52 25.882 56.538 25.92 ;
    END
  END a_par_out[85]
  PIN a_par_out[86]
    DIRECTION OUTPUT ;
    USE SIGNAL ;
    PORT
      LAYER M5 ;
        RECT  56.784 25.836 56.808 25.92 ;
    END
  END a_par_out[86]
  PIN a_par_out[87]
    DIRECTION OUTPUT ;
    USE SIGNAL ;
    PORT
      LAYER M3 ;
        RECT  56.916 25.882 56.934 25.92 ;
    END
  END a_par_out[87]
  PIN a_par_out[88]
    DIRECTION OUTPUT ;
    USE SIGNAL ;
    PORT
      LAYER M5 ;
        RECT  57.168 25.836 57.192 25.92 ;
    END
  END a_par_out[88]
  PIN a_par_out[89]
    DIRECTION OUTPUT ;
    USE SIGNAL ;
    PORT
      LAYER M3 ;
        RECT  57.312 25.882 57.33 25.92 ;
    END
  END a_par_out[89]
  PIN a_par_out[8]
    DIRECTION OUTPUT ;
    USE SIGNAL ;
    PORT
      LAYER M5 ;
        RECT  25.776 25.836 25.8 25.92 ;
    END
  END a_par_out[8]
  PIN a_par_out[90]
    DIRECTION OUTPUT ;
    USE SIGNAL ;
    PORT
      LAYER M5 ;
        RECT  57.552 25.836 57.576 25.92 ;
    END
  END a_par_out[90]
  PIN a_par_out[91]
    DIRECTION OUTPUT ;
    USE SIGNAL ;
    PORT
      LAYER M3 ;
        RECT  57.78 25.882 57.798 25.92 ;
    END
  END a_par_out[91]
  PIN a_par_out[92]
    DIRECTION OUTPUT ;
    USE SIGNAL ;
    PORT
      LAYER M5 ;
        RECT  57.936 25.836 57.96 25.92 ;
    END
  END a_par_out[92]
  PIN a_par_out[93]
    DIRECTION OUTPUT ;
    USE SIGNAL ;
    PORT
      LAYER M3 ;
        RECT  58.176 25.882 58.194 25.92 ;
    END
  END a_par_out[93]
  PIN a_par_out[94]
    DIRECTION OUTPUT ;
    USE SIGNAL ;
    PORT
      LAYER M5 ;
        RECT  58.416 25.836 58.44 25.92 ;
    END
  END a_par_out[94]
  PIN a_par_out[95]
    DIRECTION OUTPUT ;
    USE SIGNAL ;
    PORT
      LAYER M3 ;
        RECT  58.536 25.882 58.554 25.92 ;
    END
  END a_par_out[95]
  PIN a_par_out[96]
    DIRECTION OUTPUT ;
    USE SIGNAL ;
    PORT
      LAYER M5 ;
        RECT  58.8 25.836 58.824 25.92 ;
    END
  END a_par_out[96]
  PIN a_par_out[97]
    DIRECTION OUTPUT ;
    USE SIGNAL ;
    PORT
      LAYER M3 ;
        RECT  58.932 25.882 58.95 25.92 ;
    END
  END a_par_out[97]
  PIN a_par_out[98]
    DIRECTION OUTPUT ;
    USE SIGNAL ;
    PORT
      LAYER M5 ;
        RECT  59.184 25.836 59.208 25.92 ;
    END
  END a_par_out[98]
  PIN a_par_out[99]
    DIRECTION OUTPUT ;
    USE SIGNAL ;
    PORT
      LAYER M3 ;
        RECT  59.4 25.882 59.418 25.92 ;
    END
  END a_par_out[99]
  PIN a_par_out[9]
    DIRECTION OUTPUT ;
    USE SIGNAL ;
    PORT
      LAYER M3 ;
        RECT  26.208 25.882 26.226 25.92 ;
    END
  END a_par_out[9]
  PIN b_par[0]
    DIRECTION INPUT ;
    USE SIGNAL ;
    PORT
      LAYER M5 ;
        RECT  91.248 0 91.272 0.084 ;
    END
  END b_par[0]
  PIN b_par[100]
    DIRECTION INPUT ;
    USE SIGNAL ;
    PORT
      LAYER M5 ;
        RECT  111.6 0 111.624 0.084 ;
    END
  END b_par[100]
  PIN b_par[101]
    DIRECTION INPUT ;
    USE SIGNAL ;
    PORT
      LAYER M3 ;
        RECT  111.816 0 111.834 0.038 ;
    END
  END b_par[101]
  PIN b_par[102]
    DIRECTION INPUT ;
    USE SIGNAL ;
    PORT
      LAYER M5 ;
        RECT  111.984 0 112.008 0.084 ;
    END
  END b_par[102]
  PIN b_par[103]
    DIRECTION INPUT ;
    USE SIGNAL ;
    PORT
      LAYER M3 ;
        RECT  112.212 0 112.23 0.038 ;
    END
  END b_par[103]
  PIN b_par[104]
    DIRECTION INPUT ;
    USE SIGNAL ;
    PORT
      LAYER M5 ;
        RECT  112.464 0 112.488 0.084 ;
    END
  END b_par[104]
  PIN b_par[105]
    DIRECTION INPUT ;
    USE SIGNAL ;
    PORT
      LAYER M3 ;
        RECT  112.608 0 112.626 0.038 ;
    END
  END b_par[105]
  PIN b_par[106]
    DIRECTION INPUT ;
    USE SIGNAL ;
    PORT
      LAYER M5 ;
        RECT  112.848 0 112.872 0.084 ;
    END
  END b_par[106]
  PIN b_par[107]
    DIRECTION INPUT ;
    USE SIGNAL ;
    PORT
      LAYER M3 ;
        RECT  112.968 0 112.986 0.038 ;
    END
  END b_par[107]
  PIN b_par[108]
    DIRECTION INPUT ;
    USE SIGNAL ;
    PORT
      LAYER M5 ;
        RECT  113.232 0 113.256 0.084 ;
    END
  END b_par[108]
  PIN b_par[109]
    DIRECTION INPUT ;
    USE SIGNAL ;
    PORT
      LAYER M3 ;
        RECT  113.472 0 113.49 0.038 ;
    END
  END b_par[109]
  PIN b_par[10]
    DIRECTION INPUT ;
    USE SIGNAL ;
    PORT
      LAYER M5 ;
        RECT  93.36 0 93.384 0.084 ;
    END
  END b_par[10]
  PIN b_par[110]
    DIRECTION INPUT ;
    USE SIGNAL ;
    PORT
      LAYER M5 ;
        RECT  113.616 0 113.64 0.084 ;
    END
  END b_par[110]
  PIN b_par[111]
    DIRECTION INPUT ;
    USE SIGNAL ;
    PORT
      LAYER M3 ;
        RECT  113.832 0 113.85 0.038 ;
    END
  END b_par[111]
  PIN b_par[112]
    DIRECTION INPUT ;
    USE SIGNAL ;
    PORT
      LAYER M5 ;
        RECT  114.096 0 114.12 0.084 ;
    END
  END b_par[112]
  PIN b_par[113]
    DIRECTION INPUT ;
    USE SIGNAL ;
    PORT
      LAYER M3 ;
        RECT  114.228 0 114.246 0.038 ;
    END
  END b_par[113]
  PIN b_par[114]
    DIRECTION INPUT ;
    USE SIGNAL ;
    PORT
      LAYER M5 ;
        RECT  114.48 0 114.504 0.084 ;
    END
  END b_par[114]
  PIN b_par[115]
    DIRECTION INPUT ;
    USE SIGNAL ;
    PORT
      LAYER M3 ;
        RECT  114.624 0 114.642 0.038 ;
    END
  END b_par[115]
  PIN b_par[116]
    DIRECTION INPUT ;
    USE SIGNAL ;
    PORT
      LAYER M5 ;
        RECT  114.864 0 114.888 0.084 ;
    END
  END b_par[116]
  PIN b_par[117]
    DIRECTION INPUT ;
    USE SIGNAL ;
    PORT
      LAYER M3 ;
        RECT  115.092 0 115.11 0.038 ;
    END
  END b_par[117]
  PIN b_par[118]
    DIRECTION INPUT ;
    USE SIGNAL ;
    PORT
      LAYER M5 ;
        RECT  115.248 0 115.272 0.084 ;
    END
  END b_par[118]
  PIN b_par[119]
    DIRECTION INPUT ;
    USE SIGNAL ;
    PORT
      LAYER M3 ;
        RECT  115.488 0 115.506 0.038 ;
    END
  END b_par[119]
  PIN b_par[11]
    DIRECTION INPUT ;
    USE SIGNAL ;
    PORT
      LAYER M3 ;
        RECT  93.492 0 93.51 0.038 ;
    END
  END b_par[11]
  PIN b_par[120]
    DIRECTION INPUT ;
    USE SIGNAL ;
    PORT
      LAYER M5 ;
        RECT  115.728 0 115.752 0.084 ;
    END
  END b_par[120]
  PIN b_par[121]
    DIRECTION INPUT ;
    USE SIGNAL ;
    PORT
      LAYER M3 ;
        RECT  115.848 0 115.866 0.038 ;
    END
  END b_par[121]
  PIN b_par[122]
    DIRECTION INPUT ;
    USE SIGNAL ;
    PORT
      LAYER M5 ;
        RECT  116.112 0 116.136 0.084 ;
    END
  END b_par[122]
  PIN b_par[123]
    DIRECTION INPUT ;
    USE SIGNAL ;
    PORT
      LAYER M3 ;
        RECT  116.244 0 116.262 0.038 ;
    END
  END b_par[123]
  PIN b_par[124]
    DIRECTION INPUT ;
    USE SIGNAL ;
    PORT
      LAYER M5 ;
        RECT  116.496 0 116.52 0.084 ;
    END
  END b_par[124]
  PIN b_par[125]
    DIRECTION INPUT ;
    USE SIGNAL ;
    PORT
      LAYER M3 ;
        RECT  116.712 0 116.73 0.038 ;
    END
  END b_par[125]
  PIN b_par[126]
    DIRECTION INPUT ;
    USE SIGNAL ;
    PORT
      LAYER M5 ;
        RECT  116.88 0 116.904 0.084 ;
    END
  END b_par[126]
  PIN b_par[127]
    DIRECTION INPUT ;
    USE SIGNAL ;
    PORT
      LAYER M3 ;
        RECT  117.108 0 117.126 0.038 ;
    END
  END b_par[127]
  PIN b_par[128]
    DIRECTION INPUT ;
    USE SIGNAL ;
    PORT
      LAYER M5 ;
        RECT  117.264 0 117.288 0.084 ;
    END
  END b_par[128]
  PIN b_par[129]
    DIRECTION INPUT ;
    USE SIGNAL ;
    PORT
      LAYER M3 ;
        RECT  117.504 0 117.522 0.038 ;
    END
  END b_par[129]
  PIN b_par[12]
    DIRECTION INPUT ;
    USE SIGNAL ;
    PORT
      LAYER M5 ;
        RECT  93.744 0 93.768 0.084 ;
    END
  END b_par[12]
  PIN b_par[130]
    DIRECTION INPUT ;
    USE SIGNAL ;
    PORT
      LAYER M5 ;
        RECT  117.744 0 117.768 0.084 ;
    END
  END b_par[130]
  PIN b_par[131]
    DIRECTION INPUT ;
    USE SIGNAL ;
    PORT
      LAYER M3 ;
        RECT  117.864 0 117.882 0.038 ;
    END
  END b_par[131]
  PIN b_par[132]
    DIRECTION INPUT ;
    USE SIGNAL ;
    PORT
      LAYER M5 ;
        RECT  118.128 0 118.152 0.084 ;
    END
  END b_par[132]
  PIN b_par[133]
    DIRECTION INPUT ;
    USE SIGNAL ;
    PORT
      LAYER M3 ;
        RECT  118.368 0 118.386 0.038 ;
    END
  END b_par[133]
  PIN b_par[134]
    DIRECTION INPUT ;
    USE SIGNAL ;
    PORT
      LAYER M5 ;
        RECT  118.512 0 118.536 0.084 ;
    END
  END b_par[134]
  PIN b_par[135]
    DIRECTION INPUT ;
    USE SIGNAL ;
    PORT
      LAYER M3 ;
        RECT  118.728 0 118.746 0.038 ;
    END
  END b_par[135]
  PIN b_par[136]
    DIRECTION INPUT ;
    USE SIGNAL ;
    PORT
      LAYER M5 ;
        RECT  118.896 0 118.92 0.084 ;
    END
  END b_par[136]
  PIN b_par[137]
    DIRECTION INPUT ;
    USE SIGNAL ;
    PORT
      LAYER M3 ;
        RECT  119.124 0 119.142 0.038 ;
    END
  END b_par[137]
  PIN b_par[138]
    DIRECTION INPUT ;
    USE SIGNAL ;
    PORT
      LAYER M5 ;
        RECT  119.376 0 119.4 0.084 ;
    END
  END b_par[138]
  PIN b_par[139]
    DIRECTION INPUT ;
    USE SIGNAL ;
    PORT
      LAYER M3 ;
        RECT  119.52 0 119.538 0.038 ;
    END
  END b_par[139]
  PIN b_par[13]
    DIRECTION INPUT ;
    USE SIGNAL ;
    PORT
      LAYER M3 ;
        RECT  93.96 0 93.978 0.038 ;
    END
  END b_par[13]
  PIN b_par[140]
    DIRECTION INPUT ;
    USE SIGNAL ;
    PORT
      LAYER M5 ;
        RECT  119.76 0 119.784 0.084 ;
    END
  END b_par[140]
  PIN b_par[141]
    DIRECTION INPUT ;
    USE SIGNAL ;
    PORT
      LAYER M3 ;
        RECT  119.88 0 119.898 0.038 ;
    END
  END b_par[141]
  PIN b_par[142]
    DIRECTION INPUT ;
    USE SIGNAL ;
    PORT
      LAYER M5 ;
        RECT  120.144 0 120.168 0.084 ;
    END
  END b_par[142]
  PIN b_par[143]
    DIRECTION INPUT ;
    USE SIGNAL ;
    PORT
      LAYER M3 ;
        RECT  120.384 0 120.402 0.038 ;
    END
  END b_par[143]
  PIN b_par[144]
    DIRECTION INPUT ;
    USE SIGNAL ;
    PORT
      LAYER M5 ;
        RECT  120.528 0 120.552 0.084 ;
    END
  END b_par[144]
  PIN b_par[145]
    DIRECTION INPUT ;
    USE SIGNAL ;
    PORT
      LAYER M3 ;
        RECT  120.744 0 120.762 0.038 ;
    END
  END b_par[145]
  PIN b_par[146]
    DIRECTION INPUT ;
    USE SIGNAL ;
    PORT
      LAYER M5 ;
        RECT  121.008 0 121.032 0.084 ;
    END
  END b_par[146]
  PIN b_par[147]
    DIRECTION INPUT ;
    USE SIGNAL ;
    PORT
      LAYER M3 ;
        RECT  121.14 0 121.158 0.038 ;
    END
  END b_par[147]
  PIN b_par[148]
    DIRECTION INPUT ;
    USE SIGNAL ;
    PORT
      LAYER M5 ;
        RECT  121.392 0 121.416 0.084 ;
    END
  END b_par[148]
  PIN b_par[149]
    DIRECTION INPUT ;
    USE SIGNAL ;
    PORT
      LAYER M3 ;
        RECT  121.536 0 121.554 0.038 ;
    END
  END b_par[149]
  PIN b_par[14]
    DIRECTION INPUT ;
    USE SIGNAL ;
    PORT
      LAYER M5 ;
        RECT  94.128 0 94.152 0.084 ;
    END
  END b_par[14]
  PIN b_par[150]
    DIRECTION INPUT ;
    USE SIGNAL ;
    PORT
      LAYER M5 ;
        RECT  121.776 0 121.8 0.084 ;
    END
  END b_par[150]
  PIN b_par[151]
    DIRECTION INPUT ;
    USE SIGNAL ;
    PORT
      LAYER M3 ;
        RECT  122.004 0 122.022 0.038 ;
    END
  END b_par[151]
  PIN b_par[152]
    DIRECTION INPUT ;
    USE SIGNAL ;
    PORT
      LAYER M5 ;
        RECT  122.16 0 122.184 0.084 ;
    END
  END b_par[152]
  PIN b_par[153]
    DIRECTION INPUT ;
    USE SIGNAL ;
    PORT
      LAYER M3 ;
        RECT  122.4 0 122.418 0.038 ;
    END
  END b_par[153]
  PIN b_par[154]
    DIRECTION INPUT ;
    USE SIGNAL ;
    PORT
      LAYER M5 ;
        RECT  122.544 0 122.568 0.084 ;
    END
  END b_par[154]
  PIN b_par[155]
    DIRECTION INPUT ;
    USE SIGNAL ;
    PORT
      LAYER M3 ;
        RECT  122.76 0 122.778 0.038 ;
    END
  END b_par[155]
  PIN b_par[156]
    DIRECTION INPUT ;
    USE SIGNAL ;
    PORT
      LAYER M5 ;
        RECT  123.024 0 123.048 0.084 ;
    END
  END b_par[156]
  PIN b_par[157]
    DIRECTION INPUT ;
    USE SIGNAL ;
    PORT
      LAYER M3 ;
        RECT  123.156 0 123.174 0.038 ;
    END
  END b_par[157]
  PIN b_par[158]
    DIRECTION INPUT ;
    USE SIGNAL ;
    PORT
      LAYER M5 ;
        RECT  123.408 0 123.432 0.084 ;
    END
  END b_par[158]
  PIN b_par[159]
    DIRECTION INPUT ;
    USE SIGNAL ;
    PORT
      LAYER M3 ;
        RECT  123.624 0 123.642 0.038 ;
    END
  END b_par[159]
  PIN b_par[15]
    DIRECTION INPUT ;
    USE SIGNAL ;
    PORT
      LAYER M3 ;
        RECT  94.356 0 94.374 0.038 ;
    END
  END b_par[15]
  PIN b_par[160]
    DIRECTION INPUT ;
    USE SIGNAL ;
    PORT
      LAYER M5 ;
        RECT  123.792 0 123.816 0.084 ;
    END
  END b_par[160]
  PIN b_par[161]
    DIRECTION INPUT ;
    USE SIGNAL ;
    PORT
      LAYER M3 ;
        RECT  124.02 0 124.038 0.038 ;
    END
  END b_par[161]
  PIN b_par[162]
    DIRECTION INPUT ;
    USE SIGNAL ;
    PORT
      LAYER M5 ;
        RECT  124.176 0 124.2 0.084 ;
    END
  END b_par[162]
  PIN b_par[163]
    DIRECTION INPUT ;
    USE SIGNAL ;
    PORT
      LAYER M3 ;
        RECT  124.416 0 124.434 0.038 ;
    END
  END b_par[163]
  PIN b_par[164]
    DIRECTION INPUT ;
    USE SIGNAL ;
    PORT
      LAYER M5 ;
        RECT  124.656 0 124.68 0.084 ;
    END
  END b_par[164]
  PIN b_par[165]
    DIRECTION INPUT ;
    USE SIGNAL ;
    PORT
      LAYER M3 ;
        RECT  124.776 0 124.794 0.038 ;
    END
  END b_par[165]
  PIN b_par[166]
    DIRECTION INPUT ;
    USE SIGNAL ;
    PORT
      LAYER M5 ;
        RECT  125.04 0 125.064 0.084 ;
    END
  END b_par[166]
  PIN b_par[167]
    DIRECTION INPUT ;
    USE SIGNAL ;
    PORT
      LAYER M3 ;
        RECT  125.172 0 125.19 0.038 ;
    END
  END b_par[167]
  PIN b_par[168]
    DIRECTION INPUT ;
    USE SIGNAL ;
    PORT
      LAYER M5 ;
        RECT  125.424 0 125.448 0.084 ;
    END
  END b_par[168]
  PIN b_par[169]
    DIRECTION INPUT ;
    USE SIGNAL ;
    PORT
      LAYER M3 ;
        RECT  125.64 0 125.658 0.038 ;
    END
  END b_par[169]
  PIN b_par[16]
    DIRECTION INPUT ;
    USE SIGNAL ;
    PORT
      LAYER M5 ;
        RECT  94.512 0 94.536 0.084 ;
    END
  END b_par[16]
  PIN b_par[170]
    DIRECTION INPUT ;
    USE SIGNAL ;
    PORT
      LAYER M5 ;
        RECT  125.808 0 125.832 0.084 ;
    END
  END b_par[170]
  PIN b_par[171]
    DIRECTION INPUT ;
    USE SIGNAL ;
    PORT
      LAYER M3 ;
        RECT  126.036 0 126.054 0.038 ;
    END
  END b_par[171]
  PIN b_par[172]
    DIRECTION INPUT ;
    USE SIGNAL ;
    PORT
      LAYER M5 ;
        RECT  126.288 0 126.312 0.084 ;
    END
  END b_par[172]
  PIN b_par[173]
    DIRECTION INPUT ;
    USE SIGNAL ;
    PORT
      LAYER M3 ;
        RECT  126.432 0 126.45 0.038 ;
    END
  END b_par[173]
  PIN b_par[174]
    DIRECTION INPUT ;
    USE SIGNAL ;
    PORT
      LAYER M5 ;
        RECT  126.672 0 126.696 0.084 ;
    END
  END b_par[174]
  PIN b_par[175]
    DIRECTION INPUT ;
    USE SIGNAL ;
    PORT
      LAYER M3 ;
        RECT  126.792 0 126.81 0.038 ;
    END
  END b_par[175]
  PIN b_par[176]
    DIRECTION INPUT ;
    USE SIGNAL ;
    PORT
      LAYER M5 ;
        RECT  127.056 0 127.08 0.084 ;
    END
  END b_par[176]
  PIN b_par[177]
    DIRECTION INPUT ;
    USE SIGNAL ;
    PORT
      LAYER M3 ;
        RECT  127.296 0 127.314 0.038 ;
    END
  END b_par[177]
  PIN b_par[178]
    DIRECTION INPUT ;
    USE SIGNAL ;
    PORT
      LAYER M5 ;
        RECT  127.44 0 127.464 0.084 ;
    END
  END b_par[178]
  PIN b_par[179]
    DIRECTION INPUT ;
    USE SIGNAL ;
    PORT
      LAYER M3 ;
        RECT  127.656 0 127.674 0.038 ;
    END
  END b_par[179]
  PIN b_par[17]
    DIRECTION INPUT ;
    USE SIGNAL ;
    PORT
      LAYER M3 ;
        RECT  94.752 0 94.77 0.038 ;
    END
  END b_par[17]
  PIN b_par[180]
    DIRECTION INPUT ;
    USE SIGNAL ;
    PORT
      LAYER M5 ;
        RECT  127.92 0 127.944 0.084 ;
    END
  END b_par[180]
  PIN b_par[181]
    DIRECTION INPUT ;
    USE SIGNAL ;
    PORT
      LAYER M3 ;
        RECT  128.052 0 128.07 0.038 ;
    END
  END b_par[181]
  PIN b_par[182]
    DIRECTION INPUT ;
    USE SIGNAL ;
    PORT
      LAYER M5 ;
        RECT  128.304 0 128.328 0.084 ;
    END
  END b_par[182]
  PIN b_par[183]
    DIRECTION INPUT ;
    USE SIGNAL ;
    PORT
      LAYER M3 ;
        RECT  128.448 0 128.466 0.038 ;
    END
  END b_par[183]
  PIN b_par[184]
    DIRECTION INPUT ;
    USE SIGNAL ;
    PORT
      LAYER M5 ;
        RECT  128.688 0 128.712 0.084 ;
    END
  END b_par[184]
  PIN b_par[185]
    DIRECTION INPUT ;
    USE SIGNAL ;
    PORT
      LAYER M3 ;
        RECT  128.916 0 128.934 0.038 ;
    END
  END b_par[185]
  PIN b_par[186]
    DIRECTION INPUT ;
    USE SIGNAL ;
    PORT
      LAYER M5 ;
        RECT  129.072 0 129.096 0.084 ;
    END
  END b_par[186]
  PIN b_par[187]
    DIRECTION INPUT ;
    USE SIGNAL ;
    PORT
      LAYER M3 ;
        RECT  129.312 0 129.33 0.038 ;
    END
  END b_par[187]
  PIN b_par[188]
    DIRECTION INPUT ;
    USE SIGNAL ;
    PORT
      LAYER M5 ;
        RECT  129.456 0 129.48 0.084 ;
    END
  END b_par[188]
  PIN b_par[189]
    DIRECTION INPUT ;
    USE SIGNAL ;
    PORT
      LAYER M3 ;
        RECT  129.672 0 129.69 0.038 ;
    END
  END b_par[189]
  PIN b_par[18]
    DIRECTION INPUT ;
    USE SIGNAL ;
    PORT
      LAYER M5 ;
        RECT  94.992 0 95.016 0.084 ;
    END
  END b_par[18]
  PIN b_par[190]
    DIRECTION INPUT ;
    USE SIGNAL ;
    PORT
      LAYER M5 ;
        RECT  129.936 0 129.96 0.084 ;
    END
  END b_par[190]
  PIN b_par[191]
    DIRECTION INPUT ;
    USE SIGNAL ;
    PORT
      LAYER M3 ;
        RECT  130.068 0 130.086 0.038 ;
    END
  END b_par[191]
  PIN b_par[192]
    DIRECTION INPUT ;
    USE SIGNAL ;
    PORT
      LAYER M5 ;
        RECT  130.32 0 130.344 0.084 ;
    END
  END b_par[192]
  PIN b_par[193]
    DIRECTION INPUT ;
    USE SIGNAL ;
    PORT
      LAYER M3 ;
        RECT  130.536 0 130.554 0.038 ;
    END
  END b_par[193]
  PIN b_par[194]
    DIRECTION INPUT ;
    USE SIGNAL ;
    PORT
      LAYER M5 ;
        RECT  130.704 0 130.728 0.084 ;
    END
  END b_par[194]
  PIN b_par[195]
    DIRECTION INPUT ;
    USE SIGNAL ;
    PORT
      LAYER M3 ;
        RECT  130.932 0 130.95 0.038 ;
    END
  END b_par[195]
  PIN b_par[196]
    DIRECTION INPUT ;
    USE SIGNAL ;
    PORT
      LAYER M5 ;
        RECT  131.088 0 131.112 0.084 ;
    END
  END b_par[196]
  PIN b_par[197]
    DIRECTION INPUT ;
    USE SIGNAL ;
    PORT
      LAYER M3 ;
        RECT  131.328 0 131.346 0.038 ;
    END
  END b_par[197]
  PIN b_par[198]
    DIRECTION INPUT ;
    USE SIGNAL ;
    PORT
      LAYER M5 ;
        RECT  131.568 0 131.592 0.084 ;
    END
  END b_par[198]
  PIN b_par[199]
    DIRECTION INPUT ;
    USE SIGNAL ;
    PORT
      LAYER M3 ;
        RECT  131.688 0 131.706 0.038 ;
    END
  END b_par[199]
  PIN b_par[19]
    DIRECTION INPUT ;
    USE SIGNAL ;
    PORT
      LAYER M3 ;
        RECT  95.112 0 95.13 0.038 ;
    END
  END b_par[19]
  PIN b_par[1]
    DIRECTION INPUT ;
    USE SIGNAL ;
    PORT
      LAYER M3 ;
        RECT  91.476 0 91.494 0.038 ;
    END
  END b_par[1]
  PIN b_par[200]
    DIRECTION INPUT ;
    USE SIGNAL ;
    PORT
      LAYER M5 ;
        RECT  131.952 0 131.976 0.084 ;
    END
  END b_par[200]
  PIN b_par[201]
    DIRECTION INPUT ;
    USE SIGNAL ;
    PORT
      LAYER M3 ;
        RECT  132.084 0 132.102 0.038 ;
    END
  END b_par[201]
  PIN b_par[202]
    DIRECTION INPUT ;
    USE SIGNAL ;
    PORT
      LAYER M5 ;
        RECT  132.336 0 132.36 0.084 ;
    END
  END b_par[202]
  PIN b_par[203]
    DIRECTION INPUT ;
    USE SIGNAL ;
    PORT
      LAYER M3 ;
        RECT  132.552 0 132.57 0.038 ;
    END
  END b_par[203]
  PIN b_par[204]
    DIRECTION INPUT ;
    USE SIGNAL ;
    PORT
      LAYER M5 ;
        RECT  132.72 0 132.744 0.084 ;
    END
  END b_par[204]
  PIN b_par[205]
    DIRECTION INPUT ;
    USE SIGNAL ;
    PORT
      LAYER M3 ;
        RECT  132.948 0 132.966 0.038 ;
    END
  END b_par[205]
  PIN b_par[206]
    DIRECTION INPUT ;
    USE SIGNAL ;
    PORT
      LAYER M5 ;
        RECT  133.2 0 133.224 0.084 ;
    END
  END b_par[206]
  PIN b_par[207]
    DIRECTION INPUT ;
    USE SIGNAL ;
    PORT
      LAYER M3 ;
        RECT  133.344 0 133.362 0.038 ;
    END
  END b_par[207]
  PIN b_par[208]
    DIRECTION INPUT ;
    USE SIGNAL ;
    PORT
      LAYER M5 ;
        RECT  133.584 0 133.608 0.084 ;
    END
  END b_par[208]
  PIN b_par[209]
    DIRECTION INPUT ;
    USE SIGNAL ;
    PORT
      LAYER M3 ;
        RECT  133.704 0 133.722 0.038 ;
    END
  END b_par[209]
  PIN b_par[20]
    DIRECTION INPUT ;
    USE SIGNAL ;
    PORT
      LAYER M5 ;
        RECT  95.376 0 95.4 0.084 ;
    END
  END b_par[20]
  PIN b_par[210]
    DIRECTION INPUT ;
    USE SIGNAL ;
    PORT
      LAYER M5 ;
        RECT  133.968 0 133.992 0.084 ;
    END
  END b_par[210]
  PIN b_par[211]
    DIRECTION INPUT ;
    USE SIGNAL ;
    PORT
      LAYER M3 ;
        RECT  134.208 0 134.226 0.038 ;
    END
  END b_par[211]
  PIN b_par[212]
    DIRECTION INPUT ;
    USE SIGNAL ;
    PORT
      LAYER M5 ;
        RECT  134.352 0 134.376 0.084 ;
    END
  END b_par[212]
  PIN b_par[213]
    DIRECTION INPUT ;
    USE SIGNAL ;
    PORT
      LAYER M3 ;
        RECT  134.568 0 134.586 0.038 ;
    END
  END b_par[213]
  PIN b_par[214]
    DIRECTION INPUT ;
    USE SIGNAL ;
    PORT
      LAYER M5 ;
        RECT  134.736 0 134.76 0.084 ;
    END
  END b_par[214]
  PIN b_par[215]
    DIRECTION INPUT ;
    USE SIGNAL ;
    PORT
      LAYER M3 ;
        RECT  134.964 0 134.982 0.038 ;
    END
  END b_par[215]
  PIN b_par[216]
    DIRECTION INPUT ;
    USE SIGNAL ;
    PORT
      LAYER M5 ;
        RECT  135.216 0 135.24 0.084 ;
    END
  END b_par[216]
  PIN b_par[217]
    DIRECTION INPUT ;
    USE SIGNAL ;
    PORT
      LAYER M3 ;
        RECT  135.36 0 135.378 0.038 ;
    END
  END b_par[217]
  PIN b_par[218]
    DIRECTION INPUT ;
    USE SIGNAL ;
    PORT
      LAYER M5 ;
        RECT  135.6 0 135.624 0.084 ;
    END
  END b_par[218]
  PIN b_par[219]
    DIRECTION INPUT ;
    USE SIGNAL ;
    PORT
      LAYER M3 ;
        RECT  135.828 0 135.846 0.038 ;
    END
  END b_par[219]
  PIN b_par[21]
    DIRECTION INPUT ;
    USE SIGNAL ;
    PORT
      LAYER M3 ;
        RECT  95.508 0 95.526 0.038 ;
    END
  END b_par[21]
  PIN b_par[220]
    DIRECTION INPUT ;
    USE SIGNAL ;
    PORT
      LAYER M5 ;
        RECT  135.984 0 136.008 0.084 ;
    END
  END b_par[220]
  PIN b_par[221]
    DIRECTION INPUT ;
    USE SIGNAL ;
    PORT
      LAYER M3 ;
        RECT  136.224 0 136.242 0.038 ;
    END
  END b_par[221]
  PIN b_par[222]
    DIRECTION INPUT ;
    USE SIGNAL ;
    PORT
      LAYER M5 ;
        RECT  136.368 0 136.392 0.084 ;
    END
  END b_par[222]
  PIN b_par[223]
    DIRECTION INPUT ;
    USE SIGNAL ;
    PORT
      LAYER M3 ;
        RECT  136.584 0 136.602 0.038 ;
    END
  END b_par[223]
  PIN b_par[224]
    DIRECTION INPUT ;
    USE SIGNAL ;
    PORT
      LAYER M5 ;
        RECT  136.848 0 136.872 0.084 ;
    END
  END b_par[224]
  PIN b_par[225]
    DIRECTION INPUT ;
    USE SIGNAL ;
    PORT
      LAYER M3 ;
        RECT  136.98 0 136.998 0.038 ;
    END
  END b_par[225]
  PIN b_par[226]
    DIRECTION INPUT ;
    USE SIGNAL ;
    PORT
      LAYER M5 ;
        RECT  137.232 0 137.256 0.084 ;
    END
  END b_par[226]
  PIN b_par[227]
    DIRECTION INPUT ;
    USE SIGNAL ;
    PORT
      LAYER M3 ;
        RECT  137.448 0 137.466 0.038 ;
    END
  END b_par[227]
  PIN b_par[228]
    DIRECTION INPUT ;
    USE SIGNAL ;
    PORT
      LAYER M5 ;
        RECT  137.616 0 137.64 0.084 ;
    END
  END b_par[228]
  PIN b_par[229]
    DIRECTION INPUT ;
    USE SIGNAL ;
    PORT
      LAYER M3 ;
        RECT  137.844 0 137.862 0.038 ;
    END
  END b_par[229]
  PIN b_par[22]
    DIRECTION INPUT ;
    USE SIGNAL ;
    PORT
      LAYER M5 ;
        RECT  95.76 0 95.784 0.084 ;
    END
  END b_par[22]
  PIN b_par[230]
    DIRECTION INPUT ;
    USE SIGNAL ;
    PORT
      LAYER M5 ;
        RECT  138 0 138.024 0.084 ;
    END
  END b_par[230]
  PIN b_par[231]
    DIRECTION INPUT ;
    USE SIGNAL ;
    PORT
      LAYER M3 ;
        RECT  138.24 0 138.258 0.038 ;
    END
  END b_par[231]
  PIN b_par[232]
    DIRECTION INPUT ;
    USE SIGNAL ;
    PORT
      LAYER M5 ;
        RECT  138.48 0 138.504 0.084 ;
    END
  END b_par[232]
  PIN b_par[233]
    DIRECTION INPUT ;
    USE SIGNAL ;
    PORT
      LAYER M3 ;
        RECT  138.6 0 138.618 0.038 ;
    END
  END b_par[233]
  PIN b_par[234]
    DIRECTION INPUT ;
    USE SIGNAL ;
    PORT
      LAYER M5 ;
        RECT  138.864 0 138.888 0.084 ;
    END
  END b_par[234]
  PIN b_par[235]
    DIRECTION INPUT ;
    USE SIGNAL ;
    PORT
      LAYER M3 ;
        RECT  138.996 0 139.014 0.038 ;
    END
  END b_par[235]
  PIN b_par[236]
    DIRECTION INPUT ;
    USE SIGNAL ;
    PORT
      LAYER M5 ;
        RECT  139.248 0 139.272 0.084 ;
    END
  END b_par[236]
  PIN b_par[237]
    DIRECTION INPUT ;
    USE SIGNAL ;
    PORT
      LAYER M3 ;
        RECT  139.464 0 139.482 0.038 ;
    END
  END b_par[237]
  PIN b_par[238]
    DIRECTION INPUT ;
    USE SIGNAL ;
    PORT
      LAYER M5 ;
        RECT  139.632 0 139.656 0.084 ;
    END
  END b_par[238]
  PIN b_par[239]
    DIRECTION INPUT ;
    USE SIGNAL ;
    PORT
      LAYER M3 ;
        RECT  139.86 0 139.878 0.038 ;
    END
  END b_par[239]
  PIN b_par[23]
    DIRECTION INPUT ;
    USE SIGNAL ;
    PORT
      LAYER M3 ;
        RECT  95.976 0 95.994 0.038 ;
    END
  END b_par[23]
  PIN b_par[240]
    DIRECTION INPUT ;
    USE SIGNAL ;
    PORT
      LAYER M5 ;
        RECT  140.112 0 140.136 0.084 ;
    END
  END b_par[240]
  PIN b_par[241]
    DIRECTION INPUT ;
    USE SIGNAL ;
    PORT
      LAYER M3 ;
        RECT  140.256 0 140.274 0.038 ;
    END
  END b_par[241]
  PIN b_par[242]
    DIRECTION INPUT ;
    USE SIGNAL ;
    PORT
      LAYER M5 ;
        RECT  140.496 0 140.52 0.084 ;
    END
  END b_par[242]
  PIN b_par[243]
    DIRECTION INPUT ;
    USE SIGNAL ;
    PORT
      LAYER M3 ;
        RECT  140.616 0 140.634 0.038 ;
    END
  END b_par[243]
  PIN b_par[244]
    DIRECTION INPUT ;
    USE SIGNAL ;
    PORT
      LAYER M5 ;
        RECT  140.88 0 140.904 0.084 ;
    END
  END b_par[244]
  PIN b_par[245]
    DIRECTION INPUT ;
    USE SIGNAL ;
    PORT
      LAYER M3 ;
        RECT  141.12 0 141.138 0.038 ;
    END
  END b_par[245]
  PIN b_par[246]
    DIRECTION INPUT ;
    USE SIGNAL ;
    PORT
      LAYER M5 ;
        RECT  141.264 0 141.288 0.084 ;
    END
  END b_par[246]
  PIN b_par[247]
    DIRECTION INPUT ;
    USE SIGNAL ;
    PORT
      LAYER M3 ;
        RECT  141.48 0 141.498 0.038 ;
    END
  END b_par[247]
  PIN b_par[248]
    DIRECTION INPUT ;
    USE SIGNAL ;
    PORT
      LAYER M5 ;
        RECT  141.648 0 141.672 0.084 ;
    END
  END b_par[248]
  PIN b_par[249]
    DIRECTION INPUT ;
    USE SIGNAL ;
    PORT
      LAYER M3 ;
        RECT  141.876 0 141.894 0.038 ;
    END
  END b_par[249]
  PIN b_par[24]
    DIRECTION INPUT ;
    USE SIGNAL ;
    PORT
      LAYER M5 ;
        RECT  96.144 0 96.168 0.084 ;
    END
  END b_par[24]
  PIN b_par[250]
    DIRECTION INPUT ;
    USE SIGNAL ;
    PORT
      LAYER M5 ;
        RECT  142.128 0 142.152 0.084 ;
    END
  END b_par[250]
  PIN b_par[251]
    DIRECTION INPUT ;
    USE SIGNAL ;
    PORT
      LAYER M3 ;
        RECT  142.272 0 142.29 0.038 ;
    END
  END b_par[251]
  PIN b_par[252]
    DIRECTION INPUT ;
    USE SIGNAL ;
    PORT
      LAYER M5 ;
        RECT  142.512 0 142.536 0.084 ;
    END
  END b_par[252]
  PIN b_par[253]
    DIRECTION INPUT ;
    USE SIGNAL ;
    PORT
      LAYER M3 ;
        RECT  142.74 0 142.758 0.038 ;
    END
  END b_par[253]
  PIN b_par[254]
    DIRECTION INPUT ;
    USE SIGNAL ;
    PORT
      LAYER M5 ;
        RECT  142.896 0 142.92 0.084 ;
    END
  END b_par[254]
  PIN b_par[255]
    DIRECTION INPUT ;
    USE SIGNAL ;
    PORT
      LAYER M3 ;
        RECT  143.136 0 143.154 0.038 ;
    END
  END b_par[255]
  PIN b_par[25]
    DIRECTION INPUT ;
    USE SIGNAL ;
    PORT
      LAYER M3 ;
        RECT  96.372 0 96.39 0.038 ;
    END
  END b_par[25]
  PIN b_par[26]
    DIRECTION INPUT ;
    USE SIGNAL ;
    PORT
      LAYER M5 ;
        RECT  96.624 0 96.648 0.084 ;
    END
  END b_par[26]
  PIN b_par[27]
    DIRECTION INPUT ;
    USE SIGNAL ;
    PORT
      LAYER M3 ;
        RECT  96.768 0 96.786 0.038 ;
    END
  END b_par[27]
  PIN b_par[28]
    DIRECTION INPUT ;
    USE SIGNAL ;
    PORT
      LAYER M5 ;
        RECT  97.008 0 97.032 0.084 ;
    END
  END b_par[28]
  PIN b_par[29]
    DIRECTION INPUT ;
    USE SIGNAL ;
    PORT
      LAYER M3 ;
        RECT  97.128 0 97.146 0.038 ;
    END
  END b_par[29]
  PIN b_par[2]
    DIRECTION INPUT ;
    USE SIGNAL ;
    PORT
      LAYER M5 ;
        RECT  91.728 0 91.752 0.084 ;
    END
  END b_par[2]
  PIN b_par[30]
    DIRECTION INPUT ;
    USE SIGNAL ;
    PORT
      LAYER M5 ;
        RECT  97.392 0 97.416 0.084 ;
    END
  END b_par[30]
  PIN b_par[31]
    DIRECTION INPUT ;
    USE SIGNAL ;
    PORT
      LAYER M3 ;
        RECT  97.632 0 97.65 0.038 ;
    END
  END b_par[31]
  PIN b_par[32]
    DIRECTION INPUT ;
    USE SIGNAL ;
    PORT
      LAYER M5 ;
        RECT  97.776 0 97.8 0.084 ;
    END
  END b_par[32]
  PIN b_par[33]
    DIRECTION INPUT ;
    USE SIGNAL ;
    PORT
      LAYER M3 ;
        RECT  97.992 0 98.01 0.038 ;
    END
  END b_par[33]
  PIN b_par[34]
    DIRECTION INPUT ;
    USE SIGNAL ;
    PORT
      LAYER M5 ;
        RECT  98.16 0 98.184 0.084 ;
    END
  END b_par[34]
  PIN b_par[35]
    DIRECTION INPUT ;
    USE SIGNAL ;
    PORT
      LAYER M3 ;
        RECT  98.388 0 98.406 0.038 ;
    END
  END b_par[35]
  PIN b_par[36]
    DIRECTION INPUT ;
    USE SIGNAL ;
    PORT
      LAYER M5 ;
        RECT  98.64 0 98.664 0.084 ;
    END
  END b_par[36]
  PIN b_par[37]
    DIRECTION INPUT ;
    USE SIGNAL ;
    PORT
      LAYER M3 ;
        RECT  98.784 0 98.802 0.038 ;
    END
  END b_par[37]
  PIN b_par[38]
    DIRECTION INPUT ;
    USE SIGNAL ;
    PORT
      LAYER M5 ;
        RECT  99.024 0 99.048 0.084 ;
    END
  END b_par[38]
  PIN b_par[39]
    DIRECTION INPUT ;
    USE SIGNAL ;
    PORT
      LAYER M3 ;
        RECT  99.252 0 99.27 0.038 ;
    END
  END b_par[39]
  PIN b_par[3]
    DIRECTION INPUT ;
    USE SIGNAL ;
    PORT
      LAYER M3 ;
        RECT  91.872 0 91.89 0.038 ;
    END
  END b_par[3]
  PIN b_par[40]
    DIRECTION INPUT ;
    USE SIGNAL ;
    PORT
      LAYER M5 ;
        RECT  99.408 0 99.432 0.084 ;
    END
  END b_par[40]
  PIN b_par[41]
    DIRECTION INPUT ;
    USE SIGNAL ;
    PORT
      LAYER M3 ;
        RECT  99.648 0 99.666 0.038 ;
    END
  END b_par[41]
  PIN b_par[42]
    DIRECTION INPUT ;
    USE SIGNAL ;
    PORT
      LAYER M5 ;
        RECT  99.792 0 99.816 0.084 ;
    END
  END b_par[42]
  PIN b_par[43]
    DIRECTION INPUT ;
    USE SIGNAL ;
    PORT
      LAYER M3 ;
        RECT  100.008 0 100.026 0.038 ;
    END
  END b_par[43]
  PIN b_par[44]
    DIRECTION INPUT ;
    USE SIGNAL ;
    PORT
      LAYER M5 ;
        RECT  100.272 0 100.296 0.084 ;
    END
  END b_par[44]
  PIN b_par[45]
    DIRECTION INPUT ;
    USE SIGNAL ;
    PORT
      LAYER M3 ;
        RECT  100.404 0 100.422 0.038 ;
    END
  END b_par[45]
  PIN b_par[46]
    DIRECTION INPUT ;
    USE SIGNAL ;
    PORT
      LAYER M5 ;
        RECT  100.656 0 100.68 0.084 ;
    END
  END b_par[46]
  PIN b_par[47]
    DIRECTION INPUT ;
    USE SIGNAL ;
    PORT
      LAYER M3 ;
        RECT  100.8 0 100.818 0.038 ;
    END
  END b_par[47]
  PIN b_par[48]
    DIRECTION INPUT ;
    USE SIGNAL ;
    PORT
      LAYER M5 ;
        RECT  101.04 0 101.064 0.084 ;
    END
  END b_par[48]
  PIN b_par[49]
    DIRECTION INPUT ;
    USE SIGNAL ;
    PORT
      LAYER M3 ;
        RECT  101.268 0 101.286 0.038 ;
    END
  END b_par[49]
  PIN b_par[4]
    DIRECTION INPUT ;
    USE SIGNAL ;
    PORT
      LAYER M5 ;
        RECT  92.112 0 92.136 0.084 ;
    END
  END b_par[4]
  PIN b_par[50]
    DIRECTION INPUT ;
    USE SIGNAL ;
    PORT
      LAYER M5 ;
        RECT  101.424 0 101.448 0.084 ;
    END
  END b_par[50]
  PIN b_par[51]
    DIRECTION INPUT ;
    USE SIGNAL ;
    PORT
      LAYER M3 ;
        RECT  101.664 0 101.682 0.038 ;
    END
  END b_par[51]
  PIN b_par[52]
    DIRECTION INPUT ;
    USE SIGNAL ;
    PORT
      LAYER M5 ;
        RECT  101.904 0 101.928 0.084 ;
    END
  END b_par[52]
  PIN b_par[53]
    DIRECTION INPUT ;
    USE SIGNAL ;
    PORT
      LAYER M3 ;
        RECT  102.024 0 102.042 0.038 ;
    END
  END b_par[53]
  PIN b_par[54]
    DIRECTION INPUT ;
    USE SIGNAL ;
    PORT
      LAYER M5 ;
        RECT  102.288 0 102.312 0.084 ;
    END
  END b_par[54]
  PIN b_par[55]
    DIRECTION INPUT ;
    USE SIGNAL ;
    PORT
      LAYER M3 ;
        RECT  102.42 0 102.438 0.038 ;
    END
  END b_par[55]
  PIN b_par[56]
    DIRECTION INPUT ;
    USE SIGNAL ;
    PORT
      LAYER M5 ;
        RECT  102.672 0 102.696 0.084 ;
    END
  END b_par[56]
  PIN b_par[57]
    DIRECTION INPUT ;
    USE SIGNAL ;
    PORT
      LAYER M3 ;
        RECT  102.888 0 102.906 0.038 ;
    END
  END b_par[57]
  PIN b_par[58]
    DIRECTION INPUT ;
    USE SIGNAL ;
    PORT
      LAYER M5 ;
        RECT  103.056 0 103.08 0.084 ;
    END
  END b_par[58]
  PIN b_par[59]
    DIRECTION INPUT ;
    USE SIGNAL ;
    PORT
      LAYER M3 ;
        RECT  103.284 0 103.302 0.038 ;
    END
  END b_par[59]
  PIN b_par[5]
    DIRECTION INPUT ;
    USE SIGNAL ;
    PORT
      LAYER M3 ;
        RECT  92.34 0 92.358 0.038 ;
    END
  END b_par[5]
  PIN b_par[60]
    DIRECTION INPUT ;
    USE SIGNAL ;
    PORT
      LAYER M5 ;
        RECT  103.536 0 103.56 0.084 ;
    END
  END b_par[60]
  PIN b_par[61]
    DIRECTION INPUT ;
    USE SIGNAL ;
    PORT
      LAYER M3 ;
        RECT  103.68 0 103.698 0.038 ;
    END
  END b_par[61]
  PIN b_par[62]
    DIRECTION INPUT ;
    USE SIGNAL ;
    PORT
      LAYER M5 ;
        RECT  103.92 0 103.944 0.084 ;
    END
  END b_par[62]
  PIN b_par[63]
    DIRECTION INPUT ;
    USE SIGNAL ;
    PORT
      LAYER M3 ;
        RECT  104.04 0 104.058 0.038 ;
    END
  END b_par[63]
  PIN b_par[64]
    DIRECTION INPUT ;
    USE SIGNAL ;
    PORT
      LAYER M5 ;
        RECT  104.304 0 104.328 0.084 ;
    END
  END b_par[64]
  PIN b_par[65]
    DIRECTION INPUT ;
    USE SIGNAL ;
    PORT
      LAYER M3 ;
        RECT  104.544 0 104.562 0.038 ;
    END
  END b_par[65]
  PIN b_par[66]
    DIRECTION INPUT ;
    USE SIGNAL ;
    PORT
      LAYER M5 ;
        RECT  104.688 0 104.712 0.084 ;
    END
  END b_par[66]
  PIN b_par[67]
    DIRECTION INPUT ;
    USE SIGNAL ;
    PORT
      LAYER M3 ;
        RECT  104.904 0 104.922 0.038 ;
    END
  END b_par[67]
  PIN b_par[68]
    DIRECTION INPUT ;
    USE SIGNAL ;
    PORT
      LAYER M5 ;
        RECT  105.072 0 105.096 0.084 ;
    END
  END b_par[68]
  PIN b_par[69]
    DIRECTION INPUT ;
    USE SIGNAL ;
    PORT
      LAYER M3 ;
        RECT  105.3 0 105.318 0.038 ;
    END
  END b_par[69]
  PIN b_par[6]
    DIRECTION INPUT ;
    USE SIGNAL ;
    PORT
      LAYER M5 ;
        RECT  92.496 0 92.52 0.084 ;
    END
  END b_par[6]
  PIN b_par[70]
    DIRECTION INPUT ;
    USE SIGNAL ;
    PORT
      LAYER M5 ;
        RECT  105.552 0 105.576 0.084 ;
    END
  END b_par[70]
  PIN b_par[71]
    DIRECTION INPUT ;
    USE SIGNAL ;
    PORT
      LAYER M3 ;
        RECT  105.696 0 105.714 0.038 ;
    END
  END b_par[71]
  PIN b_par[72]
    DIRECTION INPUT ;
    USE SIGNAL ;
    PORT
      LAYER M5 ;
        RECT  105.936 0 105.96 0.084 ;
    END
  END b_par[72]
  PIN b_par[73]
    DIRECTION INPUT ;
    USE SIGNAL ;
    PORT
      LAYER M3 ;
        RECT  106.164 0 106.182 0.038 ;
    END
  END b_par[73]
  PIN b_par[74]
    DIRECTION INPUT ;
    USE SIGNAL ;
    PORT
      LAYER M5 ;
        RECT  106.32 0 106.344 0.084 ;
    END
  END b_par[74]
  PIN b_par[75]
    DIRECTION INPUT ;
    USE SIGNAL ;
    PORT
      LAYER M3 ;
        RECT  106.56 0 106.578 0.038 ;
    END
  END b_par[75]
  PIN b_par[76]
    DIRECTION INPUT ;
    USE SIGNAL ;
    PORT
      LAYER M5 ;
        RECT  106.704 0 106.728 0.084 ;
    END
  END b_par[76]
  PIN b_par[77]
    DIRECTION INPUT ;
    USE SIGNAL ;
    PORT
      LAYER M3 ;
        RECT  106.92 0 106.938 0.038 ;
    END
  END b_par[77]
  PIN b_par[78]
    DIRECTION INPUT ;
    USE SIGNAL ;
    PORT
      LAYER M5 ;
        RECT  107.184 0 107.208 0.084 ;
    END
  END b_par[78]
  PIN b_par[79]
    DIRECTION INPUT ;
    USE SIGNAL ;
    PORT
      LAYER M3 ;
        RECT  107.316 0 107.334 0.038 ;
    END
  END b_par[79]
  PIN b_par[7]
    DIRECTION INPUT ;
    USE SIGNAL ;
    PORT
      LAYER M3 ;
        RECT  92.736 0 92.754 0.038 ;
    END
  END b_par[7]
  PIN b_par[80]
    DIRECTION INPUT ;
    USE SIGNAL ;
    PORT
      LAYER M5 ;
        RECT  107.568 0 107.592 0.084 ;
    END
  END b_par[80]
  PIN b_par[81]
    DIRECTION INPUT ;
    USE SIGNAL ;
    PORT
      LAYER M3 ;
        RECT  107.712 0 107.73 0.038 ;
    END
  END b_par[81]
  PIN b_par[82]
    DIRECTION INPUT ;
    USE SIGNAL ;
    PORT
      LAYER M5 ;
        RECT  107.952 0 107.976 0.084 ;
    END
  END b_par[82]
  PIN b_par[83]
    DIRECTION INPUT ;
    USE SIGNAL ;
    PORT
      LAYER M3 ;
        RECT  108.18 0 108.198 0.038 ;
    END
  END b_par[83]
  PIN b_par[84]
    DIRECTION INPUT ;
    USE SIGNAL ;
    PORT
      LAYER M5 ;
        RECT  108.336 0 108.36 0.084 ;
    END
  END b_par[84]
  PIN b_par[85]
    DIRECTION INPUT ;
    USE SIGNAL ;
    PORT
      LAYER M3 ;
        RECT  108.576 0 108.594 0.038 ;
    END
  END b_par[85]
  PIN b_par[86]
    DIRECTION INPUT ;
    USE SIGNAL ;
    PORT
      LAYER M5 ;
        RECT  108.816 0 108.84 0.084 ;
    END
  END b_par[86]
  PIN b_par[87]
    DIRECTION INPUT ;
    USE SIGNAL ;
    PORT
      LAYER M3 ;
        RECT  108.936 0 108.954 0.038 ;
    END
  END b_par[87]
  PIN b_par[88]
    DIRECTION INPUT ;
    USE SIGNAL ;
    PORT
      LAYER M5 ;
        RECT  109.2 0 109.224 0.084 ;
    END
  END b_par[88]
  PIN b_par[89]
    DIRECTION INPUT ;
    USE SIGNAL ;
    PORT
      LAYER M3 ;
        RECT  109.332 0 109.35 0.038 ;
    END
  END b_par[89]
  PIN b_par[8]
    DIRECTION INPUT ;
    USE SIGNAL ;
    PORT
      LAYER M5 ;
        RECT  92.88 0 92.904 0.084 ;
    END
  END b_par[8]
  PIN b_par[90]
    DIRECTION INPUT ;
    USE SIGNAL ;
    PORT
      LAYER M5 ;
        RECT  109.584 0 109.608 0.084 ;
    END
  END b_par[90]
  PIN b_par[91]
    DIRECTION INPUT ;
    USE SIGNAL ;
    PORT
      LAYER M3 ;
        RECT  109.8 0 109.818 0.038 ;
    END
  END b_par[91]
  PIN b_par[92]
    DIRECTION INPUT ;
    USE SIGNAL ;
    PORT
      LAYER M5 ;
        RECT  109.968 0 109.992 0.084 ;
    END
  END b_par[92]
  PIN b_par[93]
    DIRECTION INPUT ;
    USE SIGNAL ;
    PORT
      LAYER M3 ;
        RECT  110.196 0 110.214 0.038 ;
    END
  END b_par[93]
  PIN b_par[94]
    DIRECTION INPUT ;
    USE SIGNAL ;
    PORT
      LAYER M5 ;
        RECT  110.352 0 110.376 0.084 ;
    END
  END b_par[94]
  PIN b_par[95]
    DIRECTION INPUT ;
    USE SIGNAL ;
    PORT
      LAYER M3 ;
        RECT  110.592 0 110.61 0.038 ;
    END
  END b_par[95]
  PIN b_par[96]
    DIRECTION INPUT ;
    USE SIGNAL ;
    PORT
      LAYER M5 ;
        RECT  110.832 0 110.856 0.084 ;
    END
  END b_par[96]
  PIN b_par[97]
    DIRECTION INPUT ;
    USE SIGNAL ;
    PORT
      LAYER M3 ;
        RECT  110.952 0 110.97 0.038 ;
    END
  END b_par[97]
  PIN b_par[98]
    DIRECTION INPUT ;
    USE SIGNAL ;
    PORT
      LAYER M5 ;
        RECT  111.216 0 111.24 0.084 ;
    END
  END b_par[98]
  PIN b_par[99]
    DIRECTION INPUT ;
    USE SIGNAL ;
    PORT
      LAYER M3 ;
        RECT  111.456 0 111.474 0.038 ;
    END
  END b_par[99]
  PIN b_par[9]
    DIRECTION INPUT ;
    USE SIGNAL ;
    PORT
      LAYER M3 ;
        RECT  93.096 0 93.114 0.038 ;
    END
  END b_par[9]
  PIN b_par_out[0]
    DIRECTION OUTPUT ;
    USE SIGNAL ;
    PORT
      LAYER M5 ;
        RECT  91.248 25.836 91.272 25.92 ;
    END
  END b_par_out[0]
  PIN b_par_out[100]
    DIRECTION OUTPUT ;
    USE SIGNAL ;
    PORT
      LAYER M5 ;
        RECT  111.6 25.836 111.624 25.92 ;
    END
  END b_par_out[100]
  PIN b_par_out[101]
    DIRECTION OUTPUT ;
    USE SIGNAL ;
    PORT
      LAYER M3 ;
        RECT  111.816 25.882 111.834 25.92 ;
    END
  END b_par_out[101]
  PIN b_par_out[102]
    DIRECTION OUTPUT ;
    USE SIGNAL ;
    PORT
      LAYER M5 ;
        RECT  111.984 25.836 112.008 25.92 ;
    END
  END b_par_out[102]
  PIN b_par_out[103]
    DIRECTION OUTPUT ;
    USE SIGNAL ;
    PORT
      LAYER M3 ;
        RECT  112.212 25.882 112.23 25.92 ;
    END
  END b_par_out[103]
  PIN b_par_out[104]
    DIRECTION OUTPUT ;
    USE SIGNAL ;
    PORT
      LAYER M5 ;
        RECT  112.464 25.836 112.488 25.92 ;
    END
  END b_par_out[104]
  PIN b_par_out[105]
    DIRECTION OUTPUT ;
    USE SIGNAL ;
    PORT
      LAYER M3 ;
        RECT  112.608 25.882 112.626 25.92 ;
    END
  END b_par_out[105]
  PIN b_par_out[106]
    DIRECTION OUTPUT ;
    USE SIGNAL ;
    PORT
      LAYER M5 ;
        RECT  112.848 25.836 112.872 25.92 ;
    END
  END b_par_out[106]
  PIN b_par_out[107]
    DIRECTION OUTPUT ;
    USE SIGNAL ;
    PORT
      LAYER M3 ;
        RECT  112.968 25.882 112.986 25.92 ;
    END
  END b_par_out[107]
  PIN b_par_out[108]
    DIRECTION OUTPUT ;
    USE SIGNAL ;
    PORT
      LAYER M5 ;
        RECT  113.232 25.836 113.256 25.92 ;
    END
  END b_par_out[108]
  PIN b_par_out[109]
    DIRECTION OUTPUT ;
    USE SIGNAL ;
    PORT
      LAYER M3 ;
        RECT  113.472 25.882 113.49 25.92 ;
    END
  END b_par_out[109]
  PIN b_par_out[10]
    DIRECTION OUTPUT ;
    USE SIGNAL ;
    PORT
      LAYER M5 ;
        RECT  93.36 25.836 93.384 25.92 ;
    END
  END b_par_out[10]
  PIN b_par_out[110]
    DIRECTION OUTPUT ;
    USE SIGNAL ;
    PORT
      LAYER M5 ;
        RECT  113.616 25.836 113.64 25.92 ;
    END
  END b_par_out[110]
  PIN b_par_out[111]
    DIRECTION OUTPUT ;
    USE SIGNAL ;
    PORT
      LAYER M3 ;
        RECT  113.832 25.882 113.85 25.92 ;
    END
  END b_par_out[111]
  PIN b_par_out[112]
    DIRECTION OUTPUT ;
    USE SIGNAL ;
    PORT
      LAYER M5 ;
        RECT  114.096 25.836 114.12 25.92 ;
    END
  END b_par_out[112]
  PIN b_par_out[113]
    DIRECTION OUTPUT ;
    USE SIGNAL ;
    PORT
      LAYER M3 ;
        RECT  114.228 25.882 114.246 25.92 ;
    END
  END b_par_out[113]
  PIN b_par_out[114]
    DIRECTION OUTPUT ;
    USE SIGNAL ;
    PORT
      LAYER M5 ;
        RECT  114.48 25.836 114.504 25.92 ;
    END
  END b_par_out[114]
  PIN b_par_out[115]
    DIRECTION OUTPUT ;
    USE SIGNAL ;
    PORT
      LAYER M3 ;
        RECT  114.624 25.882 114.642 25.92 ;
    END
  END b_par_out[115]
  PIN b_par_out[116]
    DIRECTION OUTPUT ;
    USE SIGNAL ;
    PORT
      LAYER M5 ;
        RECT  114.864 25.836 114.888 25.92 ;
    END
  END b_par_out[116]
  PIN b_par_out[117]
    DIRECTION OUTPUT ;
    USE SIGNAL ;
    PORT
      LAYER M3 ;
        RECT  115.092 25.882 115.11 25.92 ;
    END
  END b_par_out[117]
  PIN b_par_out[118]
    DIRECTION OUTPUT ;
    USE SIGNAL ;
    PORT
      LAYER M5 ;
        RECT  115.248 25.836 115.272 25.92 ;
    END
  END b_par_out[118]
  PIN b_par_out[119]
    DIRECTION OUTPUT ;
    USE SIGNAL ;
    PORT
      LAYER M3 ;
        RECT  115.488 25.882 115.506 25.92 ;
    END
  END b_par_out[119]
  PIN b_par_out[11]
    DIRECTION OUTPUT ;
    USE SIGNAL ;
    PORT
      LAYER M3 ;
        RECT  93.492 25.882 93.51 25.92 ;
    END
  END b_par_out[11]
  PIN b_par_out[120]
    DIRECTION OUTPUT ;
    USE SIGNAL ;
    PORT
      LAYER M5 ;
        RECT  115.728 25.836 115.752 25.92 ;
    END
  END b_par_out[120]
  PIN b_par_out[121]
    DIRECTION OUTPUT ;
    USE SIGNAL ;
    PORT
      LAYER M3 ;
        RECT  115.848 25.882 115.866 25.92 ;
    END
  END b_par_out[121]
  PIN b_par_out[122]
    DIRECTION OUTPUT ;
    USE SIGNAL ;
    PORT
      LAYER M5 ;
        RECT  116.112 25.836 116.136 25.92 ;
    END
  END b_par_out[122]
  PIN b_par_out[123]
    DIRECTION OUTPUT ;
    USE SIGNAL ;
    PORT
      LAYER M3 ;
        RECT  116.244 25.882 116.262 25.92 ;
    END
  END b_par_out[123]
  PIN b_par_out[124]
    DIRECTION OUTPUT ;
    USE SIGNAL ;
    PORT
      LAYER M5 ;
        RECT  116.496 25.836 116.52 25.92 ;
    END
  END b_par_out[124]
  PIN b_par_out[125]
    DIRECTION OUTPUT ;
    USE SIGNAL ;
    PORT
      LAYER M3 ;
        RECT  116.712 25.882 116.73 25.92 ;
    END
  END b_par_out[125]
  PIN b_par_out[126]
    DIRECTION OUTPUT ;
    USE SIGNAL ;
    PORT
      LAYER M5 ;
        RECT  116.88 25.836 116.904 25.92 ;
    END
  END b_par_out[126]
  PIN b_par_out[127]
    DIRECTION OUTPUT ;
    USE SIGNAL ;
    PORT
      LAYER M3 ;
        RECT  117.108 25.882 117.126 25.92 ;
    END
  END b_par_out[127]
  PIN b_par_out[128]
    DIRECTION OUTPUT ;
    USE SIGNAL ;
    PORT
      LAYER M5 ;
        RECT  117.264 25.836 117.288 25.92 ;
    END
  END b_par_out[128]
  PIN b_par_out[129]
    DIRECTION OUTPUT ;
    USE SIGNAL ;
    PORT
      LAYER M3 ;
        RECT  117.504 25.882 117.522 25.92 ;
    END
  END b_par_out[129]
  PIN b_par_out[12]
    DIRECTION OUTPUT ;
    USE SIGNAL ;
    PORT
      LAYER M5 ;
        RECT  93.744 25.836 93.768 25.92 ;
    END
  END b_par_out[12]
  PIN b_par_out[130]
    DIRECTION OUTPUT ;
    USE SIGNAL ;
    PORT
      LAYER M5 ;
        RECT  117.744 25.836 117.768 25.92 ;
    END
  END b_par_out[130]
  PIN b_par_out[131]
    DIRECTION OUTPUT ;
    USE SIGNAL ;
    PORT
      LAYER M3 ;
        RECT  117.864 25.882 117.882 25.92 ;
    END
  END b_par_out[131]
  PIN b_par_out[132]
    DIRECTION OUTPUT ;
    USE SIGNAL ;
    PORT
      LAYER M5 ;
        RECT  118.128 25.836 118.152 25.92 ;
    END
  END b_par_out[132]
  PIN b_par_out[133]
    DIRECTION OUTPUT ;
    USE SIGNAL ;
    PORT
      LAYER M3 ;
        RECT  118.368 25.882 118.386 25.92 ;
    END
  END b_par_out[133]
  PIN b_par_out[134]
    DIRECTION OUTPUT ;
    USE SIGNAL ;
    PORT
      LAYER M5 ;
        RECT  118.512 25.836 118.536 25.92 ;
    END
  END b_par_out[134]
  PIN b_par_out[135]
    DIRECTION OUTPUT ;
    USE SIGNAL ;
    PORT
      LAYER M3 ;
        RECT  118.728 25.882 118.746 25.92 ;
    END
  END b_par_out[135]
  PIN b_par_out[136]
    DIRECTION OUTPUT ;
    USE SIGNAL ;
    PORT
      LAYER M5 ;
        RECT  118.896 25.836 118.92 25.92 ;
    END
  END b_par_out[136]
  PIN b_par_out[137]
    DIRECTION OUTPUT ;
    USE SIGNAL ;
    PORT
      LAYER M3 ;
        RECT  119.124 25.882 119.142 25.92 ;
    END
  END b_par_out[137]
  PIN b_par_out[138]
    DIRECTION OUTPUT ;
    USE SIGNAL ;
    PORT
      LAYER M5 ;
        RECT  119.376 25.836 119.4 25.92 ;
    END
  END b_par_out[138]
  PIN b_par_out[139]
    DIRECTION OUTPUT ;
    USE SIGNAL ;
    PORT
      LAYER M3 ;
        RECT  119.52 25.882 119.538 25.92 ;
    END
  END b_par_out[139]
  PIN b_par_out[13]
    DIRECTION OUTPUT ;
    USE SIGNAL ;
    PORT
      LAYER M3 ;
        RECT  93.96 25.882 93.978 25.92 ;
    END
  END b_par_out[13]
  PIN b_par_out[140]
    DIRECTION OUTPUT ;
    USE SIGNAL ;
    PORT
      LAYER M5 ;
        RECT  119.76 25.836 119.784 25.92 ;
    END
  END b_par_out[140]
  PIN b_par_out[141]
    DIRECTION OUTPUT ;
    USE SIGNAL ;
    PORT
      LAYER M3 ;
        RECT  119.88 25.882 119.898 25.92 ;
    END
  END b_par_out[141]
  PIN b_par_out[142]
    DIRECTION OUTPUT ;
    USE SIGNAL ;
    PORT
      LAYER M5 ;
        RECT  120.144 25.836 120.168 25.92 ;
    END
  END b_par_out[142]
  PIN b_par_out[143]
    DIRECTION OUTPUT ;
    USE SIGNAL ;
    PORT
      LAYER M3 ;
        RECT  120.384 25.882 120.402 25.92 ;
    END
  END b_par_out[143]
  PIN b_par_out[144]
    DIRECTION OUTPUT ;
    USE SIGNAL ;
    PORT
      LAYER M5 ;
        RECT  120.528 25.836 120.552 25.92 ;
    END
  END b_par_out[144]
  PIN b_par_out[145]
    DIRECTION OUTPUT ;
    USE SIGNAL ;
    PORT
      LAYER M3 ;
        RECT  120.744 25.882 120.762 25.92 ;
    END
  END b_par_out[145]
  PIN b_par_out[146]
    DIRECTION OUTPUT ;
    USE SIGNAL ;
    PORT
      LAYER M5 ;
        RECT  121.008 25.836 121.032 25.92 ;
    END
  END b_par_out[146]
  PIN b_par_out[147]
    DIRECTION OUTPUT ;
    USE SIGNAL ;
    PORT
      LAYER M3 ;
        RECT  121.14 25.882 121.158 25.92 ;
    END
  END b_par_out[147]
  PIN b_par_out[148]
    DIRECTION OUTPUT ;
    USE SIGNAL ;
    PORT
      LAYER M5 ;
        RECT  121.392 25.836 121.416 25.92 ;
    END
  END b_par_out[148]
  PIN b_par_out[149]
    DIRECTION OUTPUT ;
    USE SIGNAL ;
    PORT
      LAYER M3 ;
        RECT  121.536 25.882 121.554 25.92 ;
    END
  END b_par_out[149]
  PIN b_par_out[14]
    DIRECTION OUTPUT ;
    USE SIGNAL ;
    PORT
      LAYER M5 ;
        RECT  94.128 25.836 94.152 25.92 ;
    END
  END b_par_out[14]
  PIN b_par_out[150]
    DIRECTION OUTPUT ;
    USE SIGNAL ;
    PORT
      LAYER M5 ;
        RECT  121.776 25.836 121.8 25.92 ;
    END
  END b_par_out[150]
  PIN b_par_out[151]
    DIRECTION OUTPUT ;
    USE SIGNAL ;
    PORT
      LAYER M3 ;
        RECT  122.004 25.882 122.022 25.92 ;
    END
  END b_par_out[151]
  PIN b_par_out[152]
    DIRECTION OUTPUT ;
    USE SIGNAL ;
    PORT
      LAYER M5 ;
        RECT  122.16 25.836 122.184 25.92 ;
    END
  END b_par_out[152]
  PIN b_par_out[153]
    DIRECTION OUTPUT ;
    USE SIGNAL ;
    PORT
      LAYER M3 ;
        RECT  122.4 25.882 122.418 25.92 ;
    END
  END b_par_out[153]
  PIN b_par_out[154]
    DIRECTION OUTPUT ;
    USE SIGNAL ;
    PORT
      LAYER M5 ;
        RECT  122.544 25.836 122.568 25.92 ;
    END
  END b_par_out[154]
  PIN b_par_out[155]
    DIRECTION OUTPUT ;
    USE SIGNAL ;
    PORT
      LAYER M3 ;
        RECT  122.76 25.882 122.778 25.92 ;
    END
  END b_par_out[155]
  PIN b_par_out[156]
    DIRECTION OUTPUT ;
    USE SIGNAL ;
    PORT
      LAYER M5 ;
        RECT  123.024 25.836 123.048 25.92 ;
    END
  END b_par_out[156]
  PIN b_par_out[157]
    DIRECTION OUTPUT ;
    USE SIGNAL ;
    PORT
      LAYER M3 ;
        RECT  123.156 25.882 123.174 25.92 ;
    END
  END b_par_out[157]
  PIN b_par_out[158]
    DIRECTION OUTPUT ;
    USE SIGNAL ;
    PORT
      LAYER M5 ;
        RECT  123.408 25.836 123.432 25.92 ;
    END
  END b_par_out[158]
  PIN b_par_out[159]
    DIRECTION OUTPUT ;
    USE SIGNAL ;
    PORT
      LAYER M3 ;
        RECT  123.624 25.882 123.642 25.92 ;
    END
  END b_par_out[159]
  PIN b_par_out[15]
    DIRECTION OUTPUT ;
    USE SIGNAL ;
    PORT
      LAYER M3 ;
        RECT  94.356 25.882 94.374 25.92 ;
    END
  END b_par_out[15]
  PIN b_par_out[160]
    DIRECTION OUTPUT ;
    USE SIGNAL ;
    PORT
      LAYER M5 ;
        RECT  123.792 25.836 123.816 25.92 ;
    END
  END b_par_out[160]
  PIN b_par_out[161]
    DIRECTION OUTPUT ;
    USE SIGNAL ;
    PORT
      LAYER M3 ;
        RECT  124.02 25.882 124.038 25.92 ;
    END
  END b_par_out[161]
  PIN b_par_out[162]
    DIRECTION OUTPUT ;
    USE SIGNAL ;
    PORT
      LAYER M5 ;
        RECT  124.176 25.836 124.2 25.92 ;
    END
  END b_par_out[162]
  PIN b_par_out[163]
    DIRECTION OUTPUT ;
    USE SIGNAL ;
    PORT
      LAYER M3 ;
        RECT  124.416 25.882 124.434 25.92 ;
    END
  END b_par_out[163]
  PIN b_par_out[164]
    DIRECTION OUTPUT ;
    USE SIGNAL ;
    PORT
      LAYER M5 ;
        RECT  124.656 25.836 124.68 25.92 ;
    END
  END b_par_out[164]
  PIN b_par_out[165]
    DIRECTION OUTPUT ;
    USE SIGNAL ;
    PORT
      LAYER M3 ;
        RECT  124.776 25.882 124.794 25.92 ;
    END
  END b_par_out[165]
  PIN b_par_out[166]
    DIRECTION OUTPUT ;
    USE SIGNAL ;
    PORT
      LAYER M5 ;
        RECT  125.04 25.836 125.064 25.92 ;
    END
  END b_par_out[166]
  PIN b_par_out[167]
    DIRECTION OUTPUT ;
    USE SIGNAL ;
    PORT
      LAYER M3 ;
        RECT  125.172 25.882 125.19 25.92 ;
    END
  END b_par_out[167]
  PIN b_par_out[168]
    DIRECTION OUTPUT ;
    USE SIGNAL ;
    PORT
      LAYER M5 ;
        RECT  125.424 25.836 125.448 25.92 ;
    END
  END b_par_out[168]
  PIN b_par_out[169]
    DIRECTION OUTPUT ;
    USE SIGNAL ;
    PORT
      LAYER M3 ;
        RECT  125.64 25.882 125.658 25.92 ;
    END
  END b_par_out[169]
  PIN b_par_out[16]
    DIRECTION OUTPUT ;
    USE SIGNAL ;
    PORT
      LAYER M5 ;
        RECT  94.512 25.836 94.536 25.92 ;
    END
  END b_par_out[16]
  PIN b_par_out[170]
    DIRECTION OUTPUT ;
    USE SIGNAL ;
    PORT
      LAYER M5 ;
        RECT  125.808 25.836 125.832 25.92 ;
    END
  END b_par_out[170]
  PIN b_par_out[171]
    DIRECTION OUTPUT ;
    USE SIGNAL ;
    PORT
      LAYER M3 ;
        RECT  126.036 25.882 126.054 25.92 ;
    END
  END b_par_out[171]
  PIN b_par_out[172]
    DIRECTION OUTPUT ;
    USE SIGNAL ;
    PORT
      LAYER M5 ;
        RECT  126.288 25.836 126.312 25.92 ;
    END
  END b_par_out[172]
  PIN b_par_out[173]
    DIRECTION OUTPUT ;
    USE SIGNAL ;
    PORT
      LAYER M3 ;
        RECT  126.432 25.882 126.45 25.92 ;
    END
  END b_par_out[173]
  PIN b_par_out[174]
    DIRECTION OUTPUT ;
    USE SIGNAL ;
    PORT
      LAYER M5 ;
        RECT  126.672 25.836 126.696 25.92 ;
    END
  END b_par_out[174]
  PIN b_par_out[175]
    DIRECTION OUTPUT ;
    USE SIGNAL ;
    PORT
      LAYER M3 ;
        RECT  126.792 25.882 126.81 25.92 ;
    END
  END b_par_out[175]
  PIN b_par_out[176]
    DIRECTION OUTPUT ;
    USE SIGNAL ;
    PORT
      LAYER M5 ;
        RECT  127.056 25.836 127.08 25.92 ;
    END
  END b_par_out[176]
  PIN b_par_out[177]
    DIRECTION OUTPUT ;
    USE SIGNAL ;
    PORT
      LAYER M3 ;
        RECT  127.296 25.882 127.314 25.92 ;
    END
  END b_par_out[177]
  PIN b_par_out[178]
    DIRECTION OUTPUT ;
    USE SIGNAL ;
    PORT
      LAYER M5 ;
        RECT  127.44 25.836 127.464 25.92 ;
    END
  END b_par_out[178]
  PIN b_par_out[179]
    DIRECTION OUTPUT ;
    USE SIGNAL ;
    PORT
      LAYER M3 ;
        RECT  127.656 25.882 127.674 25.92 ;
    END
  END b_par_out[179]
  PIN b_par_out[17]
    DIRECTION OUTPUT ;
    USE SIGNAL ;
    PORT
      LAYER M3 ;
        RECT  94.752 25.882 94.77 25.92 ;
    END
  END b_par_out[17]
  PIN b_par_out[180]
    DIRECTION OUTPUT ;
    USE SIGNAL ;
    PORT
      LAYER M5 ;
        RECT  127.92 25.836 127.944 25.92 ;
    END
  END b_par_out[180]
  PIN b_par_out[181]
    DIRECTION OUTPUT ;
    USE SIGNAL ;
    PORT
      LAYER M3 ;
        RECT  128.052 25.882 128.07 25.92 ;
    END
  END b_par_out[181]
  PIN b_par_out[182]
    DIRECTION OUTPUT ;
    USE SIGNAL ;
    PORT
      LAYER M5 ;
        RECT  128.304 25.836 128.328 25.92 ;
    END
  END b_par_out[182]
  PIN b_par_out[183]
    DIRECTION OUTPUT ;
    USE SIGNAL ;
    PORT
      LAYER M3 ;
        RECT  128.448 25.882 128.466 25.92 ;
    END
  END b_par_out[183]
  PIN b_par_out[184]
    DIRECTION OUTPUT ;
    USE SIGNAL ;
    PORT
      LAYER M5 ;
        RECT  128.688 25.836 128.712 25.92 ;
    END
  END b_par_out[184]
  PIN b_par_out[185]
    DIRECTION OUTPUT ;
    USE SIGNAL ;
    PORT
      LAYER M3 ;
        RECT  128.916 25.882 128.934 25.92 ;
    END
  END b_par_out[185]
  PIN b_par_out[186]
    DIRECTION OUTPUT ;
    USE SIGNAL ;
    PORT
      LAYER M5 ;
        RECT  129.072 25.836 129.096 25.92 ;
    END
  END b_par_out[186]
  PIN b_par_out[187]
    DIRECTION OUTPUT ;
    USE SIGNAL ;
    PORT
      LAYER M3 ;
        RECT  129.312 25.882 129.33 25.92 ;
    END
  END b_par_out[187]
  PIN b_par_out[188]
    DIRECTION OUTPUT ;
    USE SIGNAL ;
    PORT
      LAYER M5 ;
        RECT  129.456 25.836 129.48 25.92 ;
    END
  END b_par_out[188]
  PIN b_par_out[189]
    DIRECTION OUTPUT ;
    USE SIGNAL ;
    PORT
      LAYER M3 ;
        RECT  129.672 25.882 129.69 25.92 ;
    END
  END b_par_out[189]
  PIN b_par_out[18]
    DIRECTION OUTPUT ;
    USE SIGNAL ;
    PORT
      LAYER M5 ;
        RECT  94.992 25.836 95.016 25.92 ;
    END
  END b_par_out[18]
  PIN b_par_out[190]
    DIRECTION OUTPUT ;
    USE SIGNAL ;
    PORT
      LAYER M5 ;
        RECT  129.936 25.836 129.96 25.92 ;
    END
  END b_par_out[190]
  PIN b_par_out[191]
    DIRECTION OUTPUT ;
    USE SIGNAL ;
    PORT
      LAYER M3 ;
        RECT  130.068 25.882 130.086 25.92 ;
    END
  END b_par_out[191]
  PIN b_par_out[192]
    DIRECTION OUTPUT ;
    USE SIGNAL ;
    PORT
      LAYER M5 ;
        RECT  130.32 25.836 130.344 25.92 ;
    END
  END b_par_out[192]
  PIN b_par_out[193]
    DIRECTION OUTPUT ;
    USE SIGNAL ;
    PORT
      LAYER M3 ;
        RECT  130.536 25.882 130.554 25.92 ;
    END
  END b_par_out[193]
  PIN b_par_out[194]
    DIRECTION OUTPUT ;
    USE SIGNAL ;
    PORT
      LAYER M5 ;
        RECT  130.704 25.836 130.728 25.92 ;
    END
  END b_par_out[194]
  PIN b_par_out[195]
    DIRECTION OUTPUT ;
    USE SIGNAL ;
    PORT
      LAYER M3 ;
        RECT  130.932 25.882 130.95 25.92 ;
    END
  END b_par_out[195]
  PIN b_par_out[196]
    DIRECTION OUTPUT ;
    USE SIGNAL ;
    PORT
      LAYER M5 ;
        RECT  131.088 25.836 131.112 25.92 ;
    END
  END b_par_out[196]
  PIN b_par_out[197]
    DIRECTION OUTPUT ;
    USE SIGNAL ;
    PORT
      LAYER M3 ;
        RECT  131.328 25.882 131.346 25.92 ;
    END
  END b_par_out[197]
  PIN b_par_out[198]
    DIRECTION OUTPUT ;
    USE SIGNAL ;
    PORT
      LAYER M5 ;
        RECT  131.568 25.836 131.592 25.92 ;
    END
  END b_par_out[198]
  PIN b_par_out[199]
    DIRECTION OUTPUT ;
    USE SIGNAL ;
    PORT
      LAYER M3 ;
        RECT  131.688 25.882 131.706 25.92 ;
    END
  END b_par_out[199]
  PIN b_par_out[19]
    DIRECTION OUTPUT ;
    USE SIGNAL ;
    PORT
      LAYER M3 ;
        RECT  95.112 25.882 95.13 25.92 ;
    END
  END b_par_out[19]
  PIN b_par_out[1]
    DIRECTION OUTPUT ;
    USE SIGNAL ;
    PORT
      LAYER M3 ;
        RECT  91.476 25.882 91.494 25.92 ;
    END
  END b_par_out[1]
  PIN b_par_out[200]
    DIRECTION OUTPUT ;
    USE SIGNAL ;
    PORT
      LAYER M5 ;
        RECT  131.952 25.836 131.976 25.92 ;
    END
  END b_par_out[200]
  PIN b_par_out[201]
    DIRECTION OUTPUT ;
    USE SIGNAL ;
    PORT
      LAYER M3 ;
        RECT  132.084 25.882 132.102 25.92 ;
    END
  END b_par_out[201]
  PIN b_par_out[202]
    DIRECTION OUTPUT ;
    USE SIGNAL ;
    PORT
      LAYER M5 ;
        RECT  132.336 25.836 132.36 25.92 ;
    END
  END b_par_out[202]
  PIN b_par_out[203]
    DIRECTION OUTPUT ;
    USE SIGNAL ;
    PORT
      LAYER M3 ;
        RECT  132.552 25.882 132.57 25.92 ;
    END
  END b_par_out[203]
  PIN b_par_out[204]
    DIRECTION OUTPUT ;
    USE SIGNAL ;
    PORT
      LAYER M5 ;
        RECT  132.72 25.836 132.744 25.92 ;
    END
  END b_par_out[204]
  PIN b_par_out[205]
    DIRECTION OUTPUT ;
    USE SIGNAL ;
    PORT
      LAYER M3 ;
        RECT  132.948 25.882 132.966 25.92 ;
    END
  END b_par_out[205]
  PIN b_par_out[206]
    DIRECTION OUTPUT ;
    USE SIGNAL ;
    PORT
      LAYER M5 ;
        RECT  133.2 25.836 133.224 25.92 ;
    END
  END b_par_out[206]
  PIN b_par_out[207]
    DIRECTION OUTPUT ;
    USE SIGNAL ;
    PORT
      LAYER M3 ;
        RECT  133.344 25.882 133.362 25.92 ;
    END
  END b_par_out[207]
  PIN b_par_out[208]
    DIRECTION OUTPUT ;
    USE SIGNAL ;
    PORT
      LAYER M5 ;
        RECT  133.584 25.836 133.608 25.92 ;
    END
  END b_par_out[208]
  PIN b_par_out[209]
    DIRECTION OUTPUT ;
    USE SIGNAL ;
    PORT
      LAYER M3 ;
        RECT  133.704 25.882 133.722 25.92 ;
    END
  END b_par_out[209]
  PIN b_par_out[20]
    DIRECTION OUTPUT ;
    USE SIGNAL ;
    PORT
      LAYER M5 ;
        RECT  95.376 25.836 95.4 25.92 ;
    END
  END b_par_out[20]
  PIN b_par_out[210]
    DIRECTION OUTPUT ;
    USE SIGNAL ;
    PORT
      LAYER M5 ;
        RECT  133.968 25.836 133.992 25.92 ;
    END
  END b_par_out[210]
  PIN b_par_out[211]
    DIRECTION OUTPUT ;
    USE SIGNAL ;
    PORT
      LAYER M3 ;
        RECT  134.208 25.882 134.226 25.92 ;
    END
  END b_par_out[211]
  PIN b_par_out[212]
    DIRECTION OUTPUT ;
    USE SIGNAL ;
    PORT
      LAYER M5 ;
        RECT  134.352 25.836 134.376 25.92 ;
    END
  END b_par_out[212]
  PIN b_par_out[213]
    DIRECTION OUTPUT ;
    USE SIGNAL ;
    PORT
      LAYER M3 ;
        RECT  134.568 25.882 134.586 25.92 ;
    END
  END b_par_out[213]
  PIN b_par_out[214]
    DIRECTION OUTPUT ;
    USE SIGNAL ;
    PORT
      LAYER M5 ;
        RECT  134.736 25.836 134.76 25.92 ;
    END
  END b_par_out[214]
  PIN b_par_out[215]
    DIRECTION OUTPUT ;
    USE SIGNAL ;
    PORT
      LAYER M3 ;
        RECT  134.964 25.882 134.982 25.92 ;
    END
  END b_par_out[215]
  PIN b_par_out[216]
    DIRECTION OUTPUT ;
    USE SIGNAL ;
    PORT
      LAYER M5 ;
        RECT  135.216 25.836 135.24 25.92 ;
    END
  END b_par_out[216]
  PIN b_par_out[217]
    DIRECTION OUTPUT ;
    USE SIGNAL ;
    PORT
      LAYER M3 ;
        RECT  135.36 25.882 135.378 25.92 ;
    END
  END b_par_out[217]
  PIN b_par_out[218]
    DIRECTION OUTPUT ;
    USE SIGNAL ;
    PORT
      LAYER M5 ;
        RECT  135.6 25.836 135.624 25.92 ;
    END
  END b_par_out[218]
  PIN b_par_out[219]
    DIRECTION OUTPUT ;
    USE SIGNAL ;
    PORT
      LAYER M3 ;
        RECT  135.828 25.882 135.846 25.92 ;
    END
  END b_par_out[219]
  PIN b_par_out[21]
    DIRECTION OUTPUT ;
    USE SIGNAL ;
    PORT
      LAYER M3 ;
        RECT  95.508 25.882 95.526 25.92 ;
    END
  END b_par_out[21]
  PIN b_par_out[220]
    DIRECTION OUTPUT ;
    USE SIGNAL ;
    PORT
      LAYER M5 ;
        RECT  135.984 25.836 136.008 25.92 ;
    END
  END b_par_out[220]
  PIN b_par_out[221]
    DIRECTION OUTPUT ;
    USE SIGNAL ;
    PORT
      LAYER M3 ;
        RECT  136.224 25.882 136.242 25.92 ;
    END
  END b_par_out[221]
  PIN b_par_out[222]
    DIRECTION OUTPUT ;
    USE SIGNAL ;
    PORT
      LAYER M5 ;
        RECT  136.368 25.836 136.392 25.92 ;
    END
  END b_par_out[222]
  PIN b_par_out[223]
    DIRECTION OUTPUT ;
    USE SIGNAL ;
    PORT
      LAYER M3 ;
        RECT  136.584 25.882 136.602 25.92 ;
    END
  END b_par_out[223]
  PIN b_par_out[224]
    DIRECTION OUTPUT ;
    USE SIGNAL ;
    PORT
      LAYER M5 ;
        RECT  136.848 25.836 136.872 25.92 ;
    END
  END b_par_out[224]
  PIN b_par_out[225]
    DIRECTION OUTPUT ;
    USE SIGNAL ;
    PORT
      LAYER M3 ;
        RECT  136.98 25.882 136.998 25.92 ;
    END
  END b_par_out[225]
  PIN b_par_out[226]
    DIRECTION OUTPUT ;
    USE SIGNAL ;
    PORT
      LAYER M5 ;
        RECT  137.232 25.836 137.256 25.92 ;
    END
  END b_par_out[226]
  PIN b_par_out[227]
    DIRECTION OUTPUT ;
    USE SIGNAL ;
    PORT
      LAYER M3 ;
        RECT  137.448 25.882 137.466 25.92 ;
    END
  END b_par_out[227]
  PIN b_par_out[228]
    DIRECTION OUTPUT ;
    USE SIGNAL ;
    PORT
      LAYER M5 ;
        RECT  137.616 25.836 137.64 25.92 ;
    END
  END b_par_out[228]
  PIN b_par_out[229]
    DIRECTION OUTPUT ;
    USE SIGNAL ;
    PORT
      LAYER M3 ;
        RECT  137.844 25.882 137.862 25.92 ;
    END
  END b_par_out[229]
  PIN b_par_out[22]
    DIRECTION OUTPUT ;
    USE SIGNAL ;
    PORT
      LAYER M5 ;
        RECT  95.76 25.836 95.784 25.92 ;
    END
  END b_par_out[22]
  PIN b_par_out[230]
    DIRECTION OUTPUT ;
    USE SIGNAL ;
    PORT
      LAYER M5 ;
        RECT  138 25.836 138.024 25.92 ;
    END
  END b_par_out[230]
  PIN b_par_out[231]
    DIRECTION OUTPUT ;
    USE SIGNAL ;
    PORT
      LAYER M3 ;
        RECT  138.24 25.882 138.258 25.92 ;
    END
  END b_par_out[231]
  PIN b_par_out[232]
    DIRECTION OUTPUT ;
    USE SIGNAL ;
    PORT
      LAYER M5 ;
        RECT  138.48 25.836 138.504 25.92 ;
    END
  END b_par_out[232]
  PIN b_par_out[233]
    DIRECTION OUTPUT ;
    USE SIGNAL ;
    PORT
      LAYER M3 ;
        RECT  138.6 25.882 138.618 25.92 ;
    END
  END b_par_out[233]
  PIN b_par_out[234]
    DIRECTION OUTPUT ;
    USE SIGNAL ;
    PORT
      LAYER M5 ;
        RECT  138.864 25.836 138.888 25.92 ;
    END
  END b_par_out[234]
  PIN b_par_out[235]
    DIRECTION OUTPUT ;
    USE SIGNAL ;
    PORT
      LAYER M3 ;
        RECT  138.996 25.882 139.014 25.92 ;
    END
  END b_par_out[235]
  PIN b_par_out[236]
    DIRECTION OUTPUT ;
    USE SIGNAL ;
    PORT
      LAYER M5 ;
        RECT  139.248 25.836 139.272 25.92 ;
    END
  END b_par_out[236]
  PIN b_par_out[237]
    DIRECTION OUTPUT ;
    USE SIGNAL ;
    PORT
      LAYER M3 ;
        RECT  139.464 25.882 139.482 25.92 ;
    END
  END b_par_out[237]
  PIN b_par_out[238]
    DIRECTION OUTPUT ;
    USE SIGNAL ;
    PORT
      LAYER M5 ;
        RECT  139.632 25.836 139.656 25.92 ;
    END
  END b_par_out[238]
  PIN b_par_out[239]
    DIRECTION OUTPUT ;
    USE SIGNAL ;
    PORT
      LAYER M3 ;
        RECT  139.86 25.882 139.878 25.92 ;
    END
  END b_par_out[239]
  PIN b_par_out[23]
    DIRECTION OUTPUT ;
    USE SIGNAL ;
    PORT
      LAYER M3 ;
        RECT  95.976 25.882 95.994 25.92 ;
    END
  END b_par_out[23]
  PIN b_par_out[240]
    DIRECTION OUTPUT ;
    USE SIGNAL ;
    PORT
      LAYER M5 ;
        RECT  140.112 25.836 140.136 25.92 ;
    END
  END b_par_out[240]
  PIN b_par_out[241]
    DIRECTION OUTPUT ;
    USE SIGNAL ;
    PORT
      LAYER M3 ;
        RECT  140.256 25.882 140.274 25.92 ;
    END
  END b_par_out[241]
  PIN b_par_out[242]
    DIRECTION OUTPUT ;
    USE SIGNAL ;
    PORT
      LAYER M5 ;
        RECT  140.496 25.836 140.52 25.92 ;
    END
  END b_par_out[242]
  PIN b_par_out[243]
    DIRECTION OUTPUT ;
    USE SIGNAL ;
    PORT
      LAYER M3 ;
        RECT  140.616 25.882 140.634 25.92 ;
    END
  END b_par_out[243]
  PIN b_par_out[244]
    DIRECTION OUTPUT ;
    USE SIGNAL ;
    PORT
      LAYER M5 ;
        RECT  140.88 25.836 140.904 25.92 ;
    END
  END b_par_out[244]
  PIN b_par_out[245]
    DIRECTION OUTPUT ;
    USE SIGNAL ;
    PORT
      LAYER M3 ;
        RECT  141.12 25.882 141.138 25.92 ;
    END
  END b_par_out[245]
  PIN b_par_out[246]
    DIRECTION OUTPUT ;
    USE SIGNAL ;
    PORT
      LAYER M5 ;
        RECT  141.264 25.836 141.288 25.92 ;
    END
  END b_par_out[246]
  PIN b_par_out[247]
    DIRECTION OUTPUT ;
    USE SIGNAL ;
    PORT
      LAYER M3 ;
        RECT  141.48 25.882 141.498 25.92 ;
    END
  END b_par_out[247]
  PIN b_par_out[248]
    DIRECTION OUTPUT ;
    USE SIGNAL ;
    PORT
      LAYER M5 ;
        RECT  141.648 25.836 141.672 25.92 ;
    END
  END b_par_out[248]
  PIN b_par_out[249]
    DIRECTION OUTPUT ;
    USE SIGNAL ;
    PORT
      LAYER M3 ;
        RECT  141.876 25.882 141.894 25.92 ;
    END
  END b_par_out[249]
  PIN b_par_out[24]
    DIRECTION OUTPUT ;
    USE SIGNAL ;
    PORT
      LAYER M5 ;
        RECT  96.144 25.836 96.168 25.92 ;
    END
  END b_par_out[24]
  PIN b_par_out[250]
    DIRECTION OUTPUT ;
    USE SIGNAL ;
    PORT
      LAYER M5 ;
        RECT  142.128 25.836 142.152 25.92 ;
    END
  END b_par_out[250]
  PIN b_par_out[251]
    DIRECTION OUTPUT ;
    USE SIGNAL ;
    PORT
      LAYER M3 ;
        RECT  142.272 25.882 142.29 25.92 ;
    END
  END b_par_out[251]
  PIN b_par_out[252]
    DIRECTION OUTPUT ;
    USE SIGNAL ;
    PORT
      LAYER M5 ;
        RECT  142.512 25.836 142.536 25.92 ;
    END
  END b_par_out[252]
  PIN b_par_out[253]
    DIRECTION OUTPUT ;
    USE SIGNAL ;
    PORT
      LAYER M3 ;
        RECT  142.74 25.882 142.758 25.92 ;
    END
  END b_par_out[253]
  PIN b_par_out[254]
    DIRECTION OUTPUT ;
    USE SIGNAL ;
    PORT
      LAYER M5 ;
        RECT  142.896 25.836 142.92 25.92 ;
    END
  END b_par_out[254]
  PIN b_par_out[255]
    DIRECTION OUTPUT ;
    USE SIGNAL ;
    PORT
      LAYER M3 ;
        RECT  143.136 25.882 143.154 25.92 ;
    END
  END b_par_out[255]
  PIN b_par_out[25]
    DIRECTION OUTPUT ;
    USE SIGNAL ;
    PORT
      LAYER M3 ;
        RECT  96.372 25.882 96.39 25.92 ;
    END
  END b_par_out[25]
  PIN b_par_out[26]
    DIRECTION OUTPUT ;
    USE SIGNAL ;
    PORT
      LAYER M5 ;
        RECT  96.624 25.836 96.648 25.92 ;
    END
  END b_par_out[26]
  PIN b_par_out[27]
    DIRECTION OUTPUT ;
    USE SIGNAL ;
    PORT
      LAYER M3 ;
        RECT  96.768 25.882 96.786 25.92 ;
    END
  END b_par_out[27]
  PIN b_par_out[28]
    DIRECTION OUTPUT ;
    USE SIGNAL ;
    PORT
      LAYER M5 ;
        RECT  97.008 25.836 97.032 25.92 ;
    END
  END b_par_out[28]
  PIN b_par_out[29]
    DIRECTION OUTPUT ;
    USE SIGNAL ;
    PORT
      LAYER M3 ;
        RECT  97.128 25.882 97.146 25.92 ;
    END
  END b_par_out[29]
  PIN b_par_out[2]
    DIRECTION OUTPUT ;
    USE SIGNAL ;
    PORT
      LAYER M5 ;
        RECT  91.728 25.836 91.752 25.92 ;
    END
  END b_par_out[2]
  PIN b_par_out[30]
    DIRECTION OUTPUT ;
    USE SIGNAL ;
    PORT
      LAYER M5 ;
        RECT  97.392 25.836 97.416 25.92 ;
    END
  END b_par_out[30]
  PIN b_par_out[31]
    DIRECTION OUTPUT ;
    USE SIGNAL ;
    PORT
      LAYER M3 ;
        RECT  97.632 25.882 97.65 25.92 ;
    END
  END b_par_out[31]
  PIN b_par_out[32]
    DIRECTION OUTPUT ;
    USE SIGNAL ;
    PORT
      LAYER M5 ;
        RECT  97.776 25.836 97.8 25.92 ;
    END
  END b_par_out[32]
  PIN b_par_out[33]
    DIRECTION OUTPUT ;
    USE SIGNAL ;
    PORT
      LAYER M3 ;
        RECT  97.992 25.882 98.01 25.92 ;
    END
  END b_par_out[33]
  PIN b_par_out[34]
    DIRECTION OUTPUT ;
    USE SIGNAL ;
    PORT
      LAYER M5 ;
        RECT  98.16 25.836 98.184 25.92 ;
    END
  END b_par_out[34]
  PIN b_par_out[35]
    DIRECTION OUTPUT ;
    USE SIGNAL ;
    PORT
      LAYER M3 ;
        RECT  98.388 25.882 98.406 25.92 ;
    END
  END b_par_out[35]
  PIN b_par_out[36]
    DIRECTION OUTPUT ;
    USE SIGNAL ;
    PORT
      LAYER M5 ;
        RECT  98.64 25.836 98.664 25.92 ;
    END
  END b_par_out[36]
  PIN b_par_out[37]
    DIRECTION OUTPUT ;
    USE SIGNAL ;
    PORT
      LAYER M3 ;
        RECT  98.784 25.882 98.802 25.92 ;
    END
  END b_par_out[37]
  PIN b_par_out[38]
    DIRECTION OUTPUT ;
    USE SIGNAL ;
    PORT
      LAYER M5 ;
        RECT  99.024 25.836 99.048 25.92 ;
    END
  END b_par_out[38]
  PIN b_par_out[39]
    DIRECTION OUTPUT ;
    USE SIGNAL ;
    PORT
      LAYER M3 ;
        RECT  99.252 25.882 99.27 25.92 ;
    END
  END b_par_out[39]
  PIN b_par_out[3]
    DIRECTION OUTPUT ;
    USE SIGNAL ;
    PORT
      LAYER M3 ;
        RECT  91.872 25.882 91.89 25.92 ;
    END
  END b_par_out[3]
  PIN b_par_out[40]
    DIRECTION OUTPUT ;
    USE SIGNAL ;
    PORT
      LAYER M5 ;
        RECT  99.408 25.836 99.432 25.92 ;
    END
  END b_par_out[40]
  PIN b_par_out[41]
    DIRECTION OUTPUT ;
    USE SIGNAL ;
    PORT
      LAYER M3 ;
        RECT  99.648 25.882 99.666 25.92 ;
    END
  END b_par_out[41]
  PIN b_par_out[42]
    DIRECTION OUTPUT ;
    USE SIGNAL ;
    PORT
      LAYER M5 ;
        RECT  99.792 25.836 99.816 25.92 ;
    END
  END b_par_out[42]
  PIN b_par_out[43]
    DIRECTION OUTPUT ;
    USE SIGNAL ;
    PORT
      LAYER M3 ;
        RECT  100.008 25.882 100.026 25.92 ;
    END
  END b_par_out[43]
  PIN b_par_out[44]
    DIRECTION OUTPUT ;
    USE SIGNAL ;
    PORT
      LAYER M5 ;
        RECT  100.272 25.836 100.296 25.92 ;
    END
  END b_par_out[44]
  PIN b_par_out[45]
    DIRECTION OUTPUT ;
    USE SIGNAL ;
    PORT
      LAYER M3 ;
        RECT  100.404 25.882 100.422 25.92 ;
    END
  END b_par_out[45]
  PIN b_par_out[46]
    DIRECTION OUTPUT ;
    USE SIGNAL ;
    PORT
      LAYER M5 ;
        RECT  100.656 25.836 100.68 25.92 ;
    END
  END b_par_out[46]
  PIN b_par_out[47]
    DIRECTION OUTPUT ;
    USE SIGNAL ;
    PORT
      LAYER M3 ;
        RECT  100.8 25.882 100.818 25.92 ;
    END
  END b_par_out[47]
  PIN b_par_out[48]
    DIRECTION OUTPUT ;
    USE SIGNAL ;
    PORT
      LAYER M5 ;
        RECT  101.04 25.836 101.064 25.92 ;
    END
  END b_par_out[48]
  PIN b_par_out[49]
    DIRECTION OUTPUT ;
    USE SIGNAL ;
    PORT
      LAYER M3 ;
        RECT  101.268 25.882 101.286 25.92 ;
    END
  END b_par_out[49]
  PIN b_par_out[4]
    DIRECTION OUTPUT ;
    USE SIGNAL ;
    PORT
      LAYER M5 ;
        RECT  92.112 25.836 92.136 25.92 ;
    END
  END b_par_out[4]
  PIN b_par_out[50]
    DIRECTION OUTPUT ;
    USE SIGNAL ;
    PORT
      LAYER M5 ;
        RECT  101.424 25.836 101.448 25.92 ;
    END
  END b_par_out[50]
  PIN b_par_out[51]
    DIRECTION OUTPUT ;
    USE SIGNAL ;
    PORT
      LAYER M3 ;
        RECT  101.664 25.882 101.682 25.92 ;
    END
  END b_par_out[51]
  PIN b_par_out[52]
    DIRECTION OUTPUT ;
    USE SIGNAL ;
    PORT
      LAYER M5 ;
        RECT  101.904 25.836 101.928 25.92 ;
    END
  END b_par_out[52]
  PIN b_par_out[53]
    DIRECTION OUTPUT ;
    USE SIGNAL ;
    PORT
      LAYER M3 ;
        RECT  102.024 25.882 102.042 25.92 ;
    END
  END b_par_out[53]
  PIN b_par_out[54]
    DIRECTION OUTPUT ;
    USE SIGNAL ;
    PORT
      LAYER M5 ;
        RECT  102.288 25.836 102.312 25.92 ;
    END
  END b_par_out[54]
  PIN b_par_out[55]
    DIRECTION OUTPUT ;
    USE SIGNAL ;
    PORT
      LAYER M3 ;
        RECT  102.42 25.882 102.438 25.92 ;
    END
  END b_par_out[55]
  PIN b_par_out[56]
    DIRECTION OUTPUT ;
    USE SIGNAL ;
    PORT
      LAYER M5 ;
        RECT  102.672 25.836 102.696 25.92 ;
    END
  END b_par_out[56]
  PIN b_par_out[57]
    DIRECTION OUTPUT ;
    USE SIGNAL ;
    PORT
      LAYER M3 ;
        RECT  102.888 25.882 102.906 25.92 ;
    END
  END b_par_out[57]
  PIN b_par_out[58]
    DIRECTION OUTPUT ;
    USE SIGNAL ;
    PORT
      LAYER M5 ;
        RECT  103.056 25.836 103.08 25.92 ;
    END
  END b_par_out[58]
  PIN b_par_out[59]
    DIRECTION OUTPUT ;
    USE SIGNAL ;
    PORT
      LAYER M3 ;
        RECT  103.284 25.882 103.302 25.92 ;
    END
  END b_par_out[59]
  PIN b_par_out[5]
    DIRECTION OUTPUT ;
    USE SIGNAL ;
    PORT
      LAYER M3 ;
        RECT  92.34 25.882 92.358 25.92 ;
    END
  END b_par_out[5]
  PIN b_par_out[60]
    DIRECTION OUTPUT ;
    USE SIGNAL ;
    PORT
      LAYER M5 ;
        RECT  103.536 25.836 103.56 25.92 ;
    END
  END b_par_out[60]
  PIN b_par_out[61]
    DIRECTION OUTPUT ;
    USE SIGNAL ;
    PORT
      LAYER M3 ;
        RECT  103.68 25.882 103.698 25.92 ;
    END
  END b_par_out[61]
  PIN b_par_out[62]
    DIRECTION OUTPUT ;
    USE SIGNAL ;
    PORT
      LAYER M5 ;
        RECT  103.92 25.836 103.944 25.92 ;
    END
  END b_par_out[62]
  PIN b_par_out[63]
    DIRECTION OUTPUT ;
    USE SIGNAL ;
    PORT
      LAYER M3 ;
        RECT  104.04 25.882 104.058 25.92 ;
    END
  END b_par_out[63]
  PIN b_par_out[64]
    DIRECTION OUTPUT ;
    USE SIGNAL ;
    PORT
      LAYER M5 ;
        RECT  104.304 25.836 104.328 25.92 ;
    END
  END b_par_out[64]
  PIN b_par_out[65]
    DIRECTION OUTPUT ;
    USE SIGNAL ;
    PORT
      LAYER M3 ;
        RECT  104.544 25.882 104.562 25.92 ;
    END
  END b_par_out[65]
  PIN b_par_out[66]
    DIRECTION OUTPUT ;
    USE SIGNAL ;
    PORT
      LAYER M5 ;
        RECT  104.688 25.836 104.712 25.92 ;
    END
  END b_par_out[66]
  PIN b_par_out[67]
    DIRECTION OUTPUT ;
    USE SIGNAL ;
    PORT
      LAYER M3 ;
        RECT  104.904 25.882 104.922 25.92 ;
    END
  END b_par_out[67]
  PIN b_par_out[68]
    DIRECTION OUTPUT ;
    USE SIGNAL ;
    PORT
      LAYER M5 ;
        RECT  105.072 25.836 105.096 25.92 ;
    END
  END b_par_out[68]
  PIN b_par_out[69]
    DIRECTION OUTPUT ;
    USE SIGNAL ;
    PORT
      LAYER M3 ;
        RECT  105.3 25.882 105.318 25.92 ;
    END
  END b_par_out[69]
  PIN b_par_out[6]
    DIRECTION OUTPUT ;
    USE SIGNAL ;
    PORT
      LAYER M5 ;
        RECT  92.496 25.836 92.52 25.92 ;
    END
  END b_par_out[6]
  PIN b_par_out[70]
    DIRECTION OUTPUT ;
    USE SIGNAL ;
    PORT
      LAYER M5 ;
        RECT  105.552 25.836 105.576 25.92 ;
    END
  END b_par_out[70]
  PIN b_par_out[71]
    DIRECTION OUTPUT ;
    USE SIGNAL ;
    PORT
      LAYER M3 ;
        RECT  105.696 25.882 105.714 25.92 ;
    END
  END b_par_out[71]
  PIN b_par_out[72]
    DIRECTION OUTPUT ;
    USE SIGNAL ;
    PORT
      LAYER M5 ;
        RECT  105.936 25.836 105.96 25.92 ;
    END
  END b_par_out[72]
  PIN b_par_out[73]
    DIRECTION OUTPUT ;
    USE SIGNAL ;
    PORT
      LAYER M3 ;
        RECT  106.164 25.882 106.182 25.92 ;
    END
  END b_par_out[73]
  PIN b_par_out[74]
    DIRECTION OUTPUT ;
    USE SIGNAL ;
    PORT
      LAYER M5 ;
        RECT  106.32 25.836 106.344 25.92 ;
    END
  END b_par_out[74]
  PIN b_par_out[75]
    DIRECTION OUTPUT ;
    USE SIGNAL ;
    PORT
      LAYER M3 ;
        RECT  106.56 25.882 106.578 25.92 ;
    END
  END b_par_out[75]
  PIN b_par_out[76]
    DIRECTION OUTPUT ;
    USE SIGNAL ;
    PORT
      LAYER M5 ;
        RECT  106.704 25.836 106.728 25.92 ;
    END
  END b_par_out[76]
  PIN b_par_out[77]
    DIRECTION OUTPUT ;
    USE SIGNAL ;
    PORT
      LAYER M3 ;
        RECT  106.92 25.882 106.938 25.92 ;
    END
  END b_par_out[77]
  PIN b_par_out[78]
    DIRECTION OUTPUT ;
    USE SIGNAL ;
    PORT
      LAYER M5 ;
        RECT  107.184 25.836 107.208 25.92 ;
    END
  END b_par_out[78]
  PIN b_par_out[79]
    DIRECTION OUTPUT ;
    USE SIGNAL ;
    PORT
      LAYER M3 ;
        RECT  107.316 25.882 107.334 25.92 ;
    END
  END b_par_out[79]
  PIN b_par_out[7]
    DIRECTION OUTPUT ;
    USE SIGNAL ;
    PORT
      LAYER M3 ;
        RECT  92.736 25.882 92.754 25.92 ;
    END
  END b_par_out[7]
  PIN b_par_out[80]
    DIRECTION OUTPUT ;
    USE SIGNAL ;
    PORT
      LAYER M5 ;
        RECT  107.568 25.836 107.592 25.92 ;
    END
  END b_par_out[80]
  PIN b_par_out[81]
    DIRECTION OUTPUT ;
    USE SIGNAL ;
    PORT
      LAYER M3 ;
        RECT  107.712 25.882 107.73 25.92 ;
    END
  END b_par_out[81]
  PIN b_par_out[82]
    DIRECTION OUTPUT ;
    USE SIGNAL ;
    PORT
      LAYER M5 ;
        RECT  107.952 25.836 107.976 25.92 ;
    END
  END b_par_out[82]
  PIN b_par_out[83]
    DIRECTION OUTPUT ;
    USE SIGNAL ;
    PORT
      LAYER M3 ;
        RECT  108.18 25.882 108.198 25.92 ;
    END
  END b_par_out[83]
  PIN b_par_out[84]
    DIRECTION OUTPUT ;
    USE SIGNAL ;
    PORT
      LAYER M5 ;
        RECT  108.336 25.836 108.36 25.92 ;
    END
  END b_par_out[84]
  PIN b_par_out[85]
    DIRECTION OUTPUT ;
    USE SIGNAL ;
    PORT
      LAYER M3 ;
        RECT  108.576 25.882 108.594 25.92 ;
    END
  END b_par_out[85]
  PIN b_par_out[86]
    DIRECTION OUTPUT ;
    USE SIGNAL ;
    PORT
      LAYER M5 ;
        RECT  108.816 25.836 108.84 25.92 ;
    END
  END b_par_out[86]
  PIN b_par_out[87]
    DIRECTION OUTPUT ;
    USE SIGNAL ;
    PORT
      LAYER M3 ;
        RECT  108.936 25.882 108.954 25.92 ;
    END
  END b_par_out[87]
  PIN b_par_out[88]
    DIRECTION OUTPUT ;
    USE SIGNAL ;
    PORT
      LAYER M5 ;
        RECT  109.2 25.836 109.224 25.92 ;
    END
  END b_par_out[88]
  PIN b_par_out[89]
    DIRECTION OUTPUT ;
    USE SIGNAL ;
    PORT
      LAYER M3 ;
        RECT  109.332 25.882 109.35 25.92 ;
    END
  END b_par_out[89]
  PIN b_par_out[8]
    DIRECTION OUTPUT ;
    USE SIGNAL ;
    PORT
      LAYER M5 ;
        RECT  92.88 25.836 92.904 25.92 ;
    END
  END b_par_out[8]
  PIN b_par_out[90]
    DIRECTION OUTPUT ;
    USE SIGNAL ;
    PORT
      LAYER M5 ;
        RECT  109.584 25.836 109.608 25.92 ;
    END
  END b_par_out[90]
  PIN b_par_out[91]
    DIRECTION OUTPUT ;
    USE SIGNAL ;
    PORT
      LAYER M3 ;
        RECT  109.8 25.882 109.818 25.92 ;
    END
  END b_par_out[91]
  PIN b_par_out[92]
    DIRECTION OUTPUT ;
    USE SIGNAL ;
    PORT
      LAYER M5 ;
        RECT  109.968 25.836 109.992 25.92 ;
    END
  END b_par_out[92]
  PIN b_par_out[93]
    DIRECTION OUTPUT ;
    USE SIGNAL ;
    PORT
      LAYER M3 ;
        RECT  110.196 25.882 110.214 25.92 ;
    END
  END b_par_out[93]
  PIN b_par_out[94]
    DIRECTION OUTPUT ;
    USE SIGNAL ;
    PORT
      LAYER M5 ;
        RECT  110.352 25.836 110.376 25.92 ;
    END
  END b_par_out[94]
  PIN b_par_out[95]
    DIRECTION OUTPUT ;
    USE SIGNAL ;
    PORT
      LAYER M3 ;
        RECT  110.592 25.882 110.61 25.92 ;
    END
  END b_par_out[95]
  PIN b_par_out[96]
    DIRECTION OUTPUT ;
    USE SIGNAL ;
    PORT
      LAYER M5 ;
        RECT  110.832 25.836 110.856 25.92 ;
    END
  END b_par_out[96]
  PIN b_par_out[97]
    DIRECTION OUTPUT ;
    USE SIGNAL ;
    PORT
      LAYER M3 ;
        RECT  110.952 25.882 110.97 25.92 ;
    END
  END b_par_out[97]
  PIN b_par_out[98]
    DIRECTION OUTPUT ;
    USE SIGNAL ;
    PORT
      LAYER M5 ;
        RECT  111.216 25.836 111.24 25.92 ;
    END
  END b_par_out[98]
  PIN b_par_out[99]
    DIRECTION OUTPUT ;
    USE SIGNAL ;
    PORT
      LAYER M3 ;
        RECT  111.456 25.882 111.474 25.92 ;
    END
  END b_par_out[99]
  PIN b_par_out[9]
    DIRECTION OUTPUT ;
    USE SIGNAL ;
    PORT
      LAYER M3 ;
        RECT  93.096 25.882 93.114 25.92 ;
    END
  END b_par_out[9]
  PIN clk
    DIRECTION INPUT ;
    USE SIGNAL ;
    PORT
      LAYER M4 ;
        RECT  0 13.008 0.084 13.032 ;
    END
  END clk
  PIN VDD
    DIRECTION INOUT ;
    USE POWER ;
    PORT
      LAYER M5 ;
        RECT  137.592 2.151 137.712 23.769 ;
        RECT  132.192 2.151 132.312 23.769 ;
        RECT  126.792 2.151 126.912 23.769 ;
        RECT  121.392 2.151 121.512 23.769 ;
        RECT  115.992 2.151 116.112 23.769 ;
        RECT  110.592 2.151 110.712 23.769 ;
        RECT  105.192 2.151 105.312 23.769 ;
        RECT  99.792 2.151 99.912 23.769 ;
        RECT  94.392 2.151 94.512 23.769 ;
        RECT  88.992 2.151 89.112 23.769 ;
        RECT  83.592 2.151 83.712 23.769 ;
        RECT  78.192 2.151 78.312 23.769 ;
        RECT  72.792 2.151 72.912 23.769 ;
        RECT  67.392 2.151 67.512 23.769 ;
        RECT  61.992 2.151 62.112 23.769 ;
        RECT  56.592 2.151 56.712 23.769 ;
        RECT  51.192 2.151 51.312 23.769 ;
        RECT  45.792 2.151 45.912 23.769 ;
        RECT  40.392 2.151 40.512 23.769 ;
        RECT  34.992 2.151 35.112 23.769 ;
        RECT  29.592 2.151 29.712 23.769 ;
        RECT  24.192 2.151 24.312 23.769 ;
        RECT  18.792 2.151 18.912 23.769 ;
        RECT  13.392 2.151 13.512 23.769 ;
        RECT  7.992 2.151 8.112 23.769 ;
        RECT  2.592 2.151 2.712 23.769 ;
    END
  END VDD
  PIN VSS
    DIRECTION INOUT ;
    USE GROUND ;
    PORT
      LAYER M5 ;
        RECT  137.4 2.137 137.52 23.783 ;
        RECT  132 2.137 132.12 23.783 ;
        RECT  126.6 2.137 126.72 23.783 ;
        RECT  121.2 2.137 121.32 23.783 ;
        RECT  115.8 2.137 115.92 23.783 ;
        RECT  110.4 2.137 110.52 23.783 ;
        RECT  105 2.137 105.12 23.783 ;
        RECT  99.6 2.137 99.72 23.783 ;
        RECT  94.2 2.137 94.32 23.783 ;
        RECT  88.8 2.137 88.92 23.783 ;
        RECT  83.4 2.137 83.52 23.783 ;
        RECT  78 2.137 78.12 23.783 ;
        RECT  72.6 2.137 72.72 23.783 ;
        RECT  67.2 2.137 67.32 23.783 ;
        RECT  61.8 2.137 61.92 23.783 ;
        RECT  56.4 2.137 56.52 23.783 ;
        RECT  51 2.137 51.12 23.783 ;
        RECT  45.6 2.137 45.72 23.783 ;
        RECT  40.2 2.137 40.32 23.783 ;
        RECT  34.8 2.137 34.92 23.783 ;
        RECT  29.4 2.137 29.52 23.783 ;
        RECT  24 2.137 24.12 23.783 ;
        RECT  18.6 2.137 18.72 23.783 ;
        RECT  13.2 2.137 13.32 23.783 ;
        RECT  7.8 2.137 7.92 23.783 ;
        RECT  2.4 2.137 2.52 23.783 ;
    END
  END VSS
  OBS
    LAYER RVTN ;
     RECT  2.16 2.16 142.02 2.295 ;
     RECT  2.16 2.565 142.02 2.835 ;
     RECT  2.16 3.105 142.02 3.375 ;
     RECT  2.16 3.645 142.02 3.915 ;
     RECT  2.16 4.185 142.02 4.455 ;
     RECT  2.16 4.725 142.02 4.995 ;
     RECT  2.16 5.265 142.02 5.535 ;
     RECT  2.16 5.805 142.02 6.075 ;
     RECT  2.16 6.345 142.02 6.615 ;
     RECT  2.16 6.885 142.02 7.155 ;
     RECT  2.16 7.425 142.02 7.695 ;
     RECT  2.16 7.965 142.02 8.235 ;
     RECT  2.16 8.505 142.02 8.775 ;
     RECT  2.16 9.045 142.02 9.315 ;
     RECT  2.16 9.585 142.02 9.855 ;
     RECT  2.16 10.125 142.02 10.395 ;
     RECT  2.16 10.665 142.02 10.935 ;
     RECT  2.16 11.205 142.02 11.475 ;
     RECT  2.16 11.745 142.02 12.015 ;
     RECT  2.16 12.285 142.02 12.555 ;
     RECT  2.16 12.825 142.02 13.095 ;
     RECT  2.16 13.365 142.02 13.635 ;
     RECT  2.16 13.905 142.02 14.175 ;
     RECT  2.16 14.445 142.02 14.715 ;
     RECT  2.16 14.985 142.02 15.255 ;
     RECT  2.16 15.525 142.02 15.795 ;
     RECT  2.16 16.065 142.02 16.335 ;
     RECT  2.16 16.605 142.02 16.875 ;
     RECT  2.16 17.145 142.02 17.415 ;
     RECT  2.16 17.685 142.02 17.955 ;
     RECT  2.16 18.225 142.02 18.495 ;
     RECT  2.16 18.765 142.02 19.035 ;
     RECT  2.16 19.305 142.02 19.575 ;
     RECT  2.16 19.845 142.02 20.115 ;
     RECT  2.16 20.385 142.02 20.655 ;
     RECT  2.16 20.925 142.02 21.195 ;
     RECT  2.16 21.465 142.02 21.735 ;
     RECT  2.16 22.005 142.02 22.275 ;
     RECT  2.16 22.545 142.02 22.815 ;
     RECT  2.16 23.085 142.02 23.355 ;
     RECT  2.16 23.625 142.02 23.76 ;
    LAYER RVTP ;
     RECT  2.16 2.295 142.02 2.565 ;
     RECT  2.16 2.835 142.02 3.105 ;
     RECT  2.16 3.375 142.02 3.645 ;
     RECT  2.16 3.915 142.02 4.185 ;
     RECT  2.16 4.455 142.02 4.725 ;
     RECT  2.16 4.995 142.02 5.265 ;
     RECT  2.16 5.535 142.02 5.805 ;
     RECT  2.16 6.075 142.02 6.345 ;
     RECT  2.16 6.615 142.02 6.885 ;
     RECT  2.16 7.155 142.02 7.425 ;
     RECT  2.16 7.695 142.02 7.965 ;
     RECT  2.16 8.235 142.02 8.505 ;
     RECT  2.16 8.775 142.02 9.045 ;
     RECT  2.16 9.315 142.02 9.585 ;
     RECT  2.16 9.855 142.02 10.125 ;
     RECT  2.16 10.395 142.02 10.665 ;
     RECT  2.16 10.935 142.02 11.205 ;
     RECT  2.16 11.475 142.02 11.745 ;
     RECT  2.16 12.015 142.02 12.285 ;
     RECT  2.16 12.555 142.02 12.825 ;
     RECT  2.16 13.095 142.02 13.365 ;
     RECT  2.16 13.635 142.02 13.905 ;
     RECT  2.16 14.175 142.02 14.445 ;
     RECT  2.16 14.715 142.02 14.985 ;
     RECT  2.16 15.255 142.02 15.525 ;
     RECT  2.16 15.795 142.02 16.065 ;
     RECT  2.16 16.335 142.02 16.605 ;
     RECT  2.16 16.875 142.02 17.145 ;
     RECT  2.16 17.415 142.02 17.685 ;
     RECT  2.16 17.955 142.02 18.225 ;
     RECT  2.16 18.495 142.02 18.765 ;
     RECT  2.16 19.035 142.02 19.305 ;
     RECT  2.16 19.575 142.02 19.845 ;
     RECT  2.16 20.115 142.02 20.385 ;
     RECT  2.16 20.655 142.02 20.925 ;
     RECT  2.16 21.195 142.02 21.465 ;
     RECT  2.16 21.735 142.02 22.005 ;
     RECT  2.16 22.275 142.02 22.545 ;
     RECT  2.16 22.815 142.02 23.085 ;
     RECT  2.16 23.355 142.02 23.625 ;
    LAYER M1 ;
     RECT  2.16 2.151 142.02 23.769 ;
    LAYER M2 ;
     RECT  2.16 2.151 22.819 23.769 ;
     RECT  22.819 1.728 22.955 23.769 ;
     RECT  23.611 25.866 23.711 25.884 ;
     RECT  22.955 2.151 24.583 23.769 ;
     RECT  24.583 2.151 25.655 23.814 ;
     RECT  38.371 25.866 38.471 25.884 ;
     RECT  25.655 2.151 39.019 23.769 ;
     RECT  39.019 1.728 39.191 23.769 ;
     RECT  39.191 2.151 39.955 23.769 ;
     RECT  39.955 1.728 40.055 23.769 ;
     RECT  40.055 2.151 42.403 23.769 ;
     RECT  42.403 2.151 42.719 23.814 ;
     RECT  44.059 25.866 44.447 25.884 ;
     RECT  42.719 2.151 45.571 23.769 ;
     RECT  45.571 2.151 45.707 23.85 ;
     RECT  45.679 0.036 45.779 0.054 ;
     RECT  45.707 2.151 52.915 23.769 ;
     RECT  52.915 2.151 53.015 23.994 ;
     RECT  53.015 2.151 56.119 23.769 ;
     RECT  56.515 1.071 56.615 1.089 ;
     RECT  56.119 2.106 56.615 23.769 ;
     RECT  56.515 25.866 56.759 25.884 ;
     RECT  58.927 25.056 59.027 25.074 ;
     RECT  61.807 0.036 61.979 0.054 ;
     RECT  61.807 25.056 61.979 25.074 ;
     RECT  56.615 2.151 62.743 23.769 ;
     RECT  63.751 25.056 63.851 25.074 ;
     RECT  62.743 2.151 64.579 23.85 ;
     RECT  64.579 2.151 64.651 23.886 ;
     RECT  64.687 25.056 64.787 25.074 ;
     RECT  64.651 2.151 66.659 23.922 ;
     RECT  70.339 25.146 70.511 25.164 ;
     RECT  66.659 2.151 72.427 23.769 ;
     RECT  72.427 2.151 72.535 23.814 ;
     RECT  72.535 2.151 72.779 23.922 ;
     RECT  72.779 2.151 73.283 23.814 ;
     RECT  74.371 25.758 74.507 25.776 ;
     RECT  76.387 25.056 76.523 25.074 ;
     RECT  73.283 2.151 77.971 23.769 ;
     RECT  77.899 0.036 78.071 0.054 ;
     RECT  77.971 2.151 78.511 23.85 ;
     RECT  78.511 2.151 78.647 23.994 ;
     RECT  78.907 25.146 79.007 25.164 ;
     RECT  78.647 2.151 79.403 23.814 ;
     RECT  81.787 24.561 82.031 24.579 ;
     RECT  79.403 2.151 82.939 23.769 ;
     RECT  82.939 2.151 83.219 23.814 ;
     RECT  83.219 2.151 84.955 23.769 ;
     RECT  84.955 2.151 85.091 23.958 ;
     RECT  85.091 2.151 86.179 23.814 ;
     RECT  86.503 0.036 86.603 0.054 ;
     RECT  86.179 2.151 86.783 23.922 ;
     RECT  88.195 0.036 88.295 0.054 ;
     RECT  86.783 2.151 91.867 23.769 ;
     RECT  91.867 2.151 91.967 23.814 ;
     RECT  92.335 0.036 92.471 0.054 ;
     RECT  91.967 2.151 94.351 23.769 ;
     RECT  94.351 2.151 94.595 23.922 ;
     RECT  94.595 2.151 95.135 23.886 ;
     RECT  95.135 2.151 98.671 23.769 ;
     RECT  98.671 2.151 99.499 23.85 ;
     RECT  99.499 1.728 99.671 23.85 ;
     RECT  100.795 0.036 100.895 0.054 ;
     RECT  99.671 2.151 102.667 23.769 ;
     RECT  102.883 25.056 103.307 25.074 ;
     RECT  102.667 2.151 103.415 23.814 ;
     RECT  107.599 25.056 107.735 25.074 ;
     RECT  108.103 0.036 108.203 0.054 ;
     RECT  108.571 25.056 108.779 25.074 ;
     RECT  103.415 2.151 110.587 23.769 ;
     RECT  109.795 0.036 110.759 0.054 ;
     RECT  110.587 2.151 112.127 23.814 ;
     RECT  112.127 2.151 114.223 23.769 ;
     RECT  114.619 25.056 114.719 25.074 ;
     RECT  114.223 2.151 115.295 23.922 ;
     RECT  115.771 0.036 115.871 0.054 ;
     RECT  115.295 2.151 115.979 23.85 ;
     RECT  116.167 25.056 116.267 25.074 ;
     RECT  117.787 0.036 117.887 0.054 ;
     RECT  121.135 24.516 122.243 24.534 ;
     RECT  124.699 25.866 124.799 25.884 ;
     RECT  125.167 25.056 125.267 25.074 ;
     RECT  115.979 2.151 126.859 23.769 ;
     RECT  126.787 25.182 126.887 25.2 ;
     RECT  126.859 2.151 127.543 23.814 ;
     RECT  127.543 2.151 127.679 23.994 ;
     RECT  127.679 2.151 130.531 23.769 ;
     RECT  130.531 2.151 131.071 23.814 ;
     RECT  131.071 2.151 131.323 23.958 ;
     RECT  131.323 2.151 131.675 24.039 ;
     RECT  131.675 2.151 131.711 23.958 ;
     RECT  131.935 25.056 132.107 25.074 ;
     RECT  131.863 0.036 132.647 0.054 ;
     RECT  131.711 2.151 133.699 23.769 ;
     RECT  133.699 2.151 133.907 23.994 ;
     RECT  133.907 2.151 135.247 23.769 ;
     RECT  135.247 2.151 135.383 23.922 ;
     RECT  136.579 0.036 137.471 0.054 ;
     RECT  137.443 25.056 138.335 25.074 ;
     RECT  135.383 2.151 139.711 23.769 ;
     RECT  140.251 25.056 140.747 25.074 ;
     RECT  139.711 2.151 141.683 23.814 ;
     RECT  141.683 2.151 142.02 23.769 ;
     RECT  142.02 23.058 142.151 23.724 ;
     RECT  142.02 5.346 142.187 7.38 ;
     RECT  142.187 5.346 142.223 6.264 ;
     RECT  142.151 23.058 142.223 23.616 ;
     RECT  142.187 7.236 142.259 7.38 ;
     RECT  142.223 23.058 142.259 23.454 ;
     RECT  142.223 5.346 142.295 5.796 ;
     RECT  142.02 19.926 142.295 21.024 ;
     RECT  142.295 5.346 142.367 5.364 ;
     RECT  142.259 23.328 142.367 23.454 ;
     RECT  142.259 7.236 142.403 7.254 ;
     RECT  142.367 23.328 142.403 23.346 ;
     RECT  142.02 3.348 142.511 3.942 ;
     RECT  142.02 22.086 142.511 22.104 ;
     RECT  142.511 3.726 142.763 3.942 ;
     RECT  142.295 19.926 142.763 19.944 ;
     RECT  142.763 3.726 143.159 3.744 ;
     RECT  142.295 21.006 143.159 21.024 ;
    LAYER M3 ;
     RECT  45.684 0.012 45.702 0.031 ;
     RECT  46.44 0.012 46.458 0.031 ;
     RECT  45.684 0.031 46.458 0.059 ;
     RECT  56.16 0.012 143.154 0.059 ;
     RECT  44.064 0.012 44.082 0.571 ;
     RECT  44.82 0.012 44.838 0.571 ;
     RECT  22.932 0.012 22.95 1.723 ;
     RECT  23.688 0.012 23.706 1.723 ;
     RECT  24.552 0.012 24.57 1.723 ;
     RECT  25.344 0.012 25.362 1.723 ;
     RECT  26.208 0.012 26.226 1.723 ;
     RECT  26.964 0.012 26.982 1.723 ;
     RECT  27.828 0.012 27.846 1.723 ;
     RECT  28.584 0.012 28.602 1.723 ;
     RECT  29.376 0.012 29.394 1.723 ;
     RECT  30.24 0.012 30.258 1.723 ;
     RECT  30.996 0.012 31.014 1.723 ;
     RECT  31.86 0.012 31.878 1.723 ;
     RECT  32.616 0.012 32.634 1.723 ;
     RECT  33.48 0.012 33.498 1.723 ;
     RECT  34.272 0.012 34.29 1.723 ;
     RECT  35.136 0.012 35.154 1.723 ;
     RECT  35.892 0.012 35.91 1.723 ;
     RECT  36.756 0.012 36.774 1.723 ;
     RECT  37.512 0.012 37.53 1.723 ;
     RECT  38.376 0.012 38.394 1.723 ;
     RECT  39.168 0.012 39.186 1.723 ;
     RECT  40.032 0.012 40.05 1.723 ;
     RECT  40.788 0.012 40.806 1.723 ;
     RECT  41.544 0.012 41.562 1.723 ;
     RECT  42.408 0.012 42.426 1.723 ;
     RECT  43.2 0.012 43.218 1.723 ;
     RECT  44.064 0.571 44.838 1.723 ;
     RECT  45.756 0.059 46.458 1.723 ;
     RECT  47.304 0.012 47.322 1.723 ;
     RECT  48.096 0.012 48.114 1.723 ;
     RECT  48.96 0.012 48.978 1.723 ;
     RECT  49.716 0.012 49.734 1.723 ;
     RECT  50.58 0.012 50.598 1.723 ;
     RECT  51.336 0.012 51.354 1.723 ;
     RECT  52.2 0.012 52.218 1.723 ;
     RECT  52.992 0.012 53.01 1.723 ;
     RECT  53.748 0.012 53.766 1.723 ;
     RECT  54.612 0.012 54.63 1.723 ;
     RECT  55.368 0.012 55.386 1.723 ;
     RECT  56.16 0.059 131.886 1.723 ;
     RECT  132.624 0.059 143.154 1.723 ;
     RECT  22.284 1.723 143.154 2.255 ;
     RECT  2.415 2.143 2.505 2.413 ;
     RECT  7.815 2.143 7.905 2.413 ;
     RECT  13.215 2.143 13.305 2.413 ;
     RECT  18.615 2.143 18.705 2.413 ;
     RECT  22.428 2.255 143.154 2.489 ;
     RECT  22.716 2.489 143.154 3.065 ;
     RECT  39.78 3.065 143.154 3.437 ;
     RECT  22.716 3.065 39.042 3.721 ;
     RECT  39.78 3.437 100.962 3.725 ;
     RECT  101.736 3.437 143.154 3.749 ;
     RECT  22.68 3.721 39.042 3.869 ;
     RECT  101.736 3.749 142.758 3.947 ;
     RECT  23.04 3.869 39.042 3.955 ;
     RECT  39.78 3.725 87.534 3.955 ;
     RECT  23.04 3.955 87.534 4.109 ;
     RECT  39.78 4.109 87.534 4.253 ;
     RECT  88.272 3.725 100.962 4.261 ;
     RECT  101.736 3.947 142.29 4.261 ;
     RECT  23.04 4.109 39.006 4.289 ;
     RECT  23.04 4.289 37.062 4.301 ;
     RECT  88.272 4.261 142.29 4.301 ;
     RECT  45.615 4.253 87.534 4.415 ;
     RECT  85.392 4.415 87.534 4.495 ;
     RECT  88.272 4.301 113.454 4.495 ;
     RECT  114.336 4.301 142.29 4.649 ;
     RECT  39.78 4.253 44.874 4.685 ;
     RECT  45.615 4.415 84.51 4.757 ;
     RECT  45.615 4.757 78.642 4.793 ;
     RECT  85.392 4.495 113.454 4.919 ;
     RECT  61.815 4.793 78.642 4.955 ;
     RECT  85.392 4.919 113.166 4.955 ;
     RECT  115.776 4.649 142.29 4.955 ;
     RECT  90.576 4.955 100.998 4.973 ;
     RECT  114.336 4.649 115.002 5.071 ;
     RECT  45.615 4.793 60.894 5.099 ;
     RECT  74.844 4.955 78.642 5.189 ;
     RECT  101.844 4.955 113.166 5.189 ;
     RECT  115.815 4.955 129.366 5.189 ;
     RECT  61.815 4.955 73.89 5.225 ;
     RECT  74.844 5.189 78.498 5.225 ;
     RECT  79.38 4.757 84.51 5.305 ;
     RECT  85.392 4.955 89.802 5.305 ;
     RECT  101.844 5.189 110.697 5.333 ;
     RECT  130.14 4.955 142.29 5.341 ;
     RECT  97.308 4.973 100.998 5.369 ;
     RECT  79.38 5.305 89.802 5.459 ;
     RECT  79.38 5.459 87.966 5.495 ;
     RECT  79.38 5.495 87.534 5.501 ;
     RECT  99.576 5.369 100.998 5.501 ;
     RECT  130.14 5.341 142.362 5.501 ;
     RECT  74.844 5.225 78.39 5.531 ;
     RECT  79.38 5.501 84.546 5.549 ;
     RECT  97.308 5.369 98.622 5.597 ;
     RECT  139.572 5.501 142.362 5.765 ;
     RECT  139.824 5.765 142.362 6.575 ;
     RECT  139.968 6.575 142.362 7.231 ;
     RECT  139.968 7.231 142.398 19.921 ;
     RECT  139.968 19.921 142.758 20.155 ;
     RECT  139.5 20.155 142.758 20.695 ;
     RECT  130.14 5.501 138.618 20.965 ;
     RECT  139.392 20.695 142.758 20.965 ;
     RECT  130.14 20.965 142.758 21.001 ;
     RECT  124.92 5.189 129.366 21.199 ;
     RECT  130.14 21.001 143.154 21.199 ;
     RECT  111.456 5.189 113.166 21.235 ;
     RECT  113.904 5.071 115.002 21.235 ;
     RECT  74.844 5.531 76.806 21.361 ;
     RECT  99.615 5.501 100.998 21.361 ;
     RECT  101.916 5.333 110.697 21.361 ;
     RECT  111.456 21.235 115.002 21.361 ;
     RECT  85.392 5.501 87.534 21.397 ;
     RECT  74.736 21.361 77.13 21.433 ;
     RECT  78.015 5.531 78.39 21.433 ;
     RECT  61.815 5.225 71.442 21.469 ;
     RECT  72.216 5.225 73.89 21.469 ;
     RECT  74.736 21.433 78.39 21.469 ;
     RECT  85.392 21.397 87.57 21.469 ;
     RECT  115.815 5.189 124.074 21.469 ;
     RECT  124.92 21.199 143.154 21.469 ;
     RECT  61.815 21.469 73.89 21.505 ;
     RECT  79.38 5.549 84.51 21.505 ;
     RECT  85.284 21.469 87.57 21.505 ;
     RECT  61.815 21.505 73.962 21.541 ;
     RECT  74.736 21.469 78.642 21.541 ;
     RECT  79.38 21.505 87.57 21.541 ;
     RECT  88.74 5.459 89.802 21.541 ;
     RECT  90.576 4.973 96.57 21.541 ;
     RECT  97.308 5.597 97.902 21.541 ;
     RECT  61.815 21.541 96.57 21.595 ;
     RECT  97.308 21.541 98.514 21.595 ;
     RECT  45.615 5.099 60.714 21.631 ;
     RECT  99.615 21.361 115.002 21.631 ;
     RECT  115.815 21.469 143.154 21.631 ;
     RECT  45.615 21.631 60.966 21.667 ;
     RECT  61.815 21.595 98.514 21.667 ;
     RECT  45.615 21.667 98.514 21.691 ;
     RECT  99.615 21.631 143.154 21.691 ;
     RECT  39.78 4.685 42.93 22.477 ;
     RECT  43.668 4.685 44.874 22.477 ;
     RECT  37.98 4.289 39.006 22.621 ;
     RECT  39.78 22.477 44.874 22.621 ;
     RECT  37.98 22.621 44.874 22.747 ;
     RECT  45.615 21.691 143.154 22.747 ;
     RECT  23.04 4.301 36.918 22.855 ;
     RECT  37.692 22.747 143.154 22.855 ;
     RECT  23.04 22.855 143.154 22.981 ;
     RECT  22.716 22.981 143.154 23.287 ;
     RECT  2.415 2.413 2.697 23.507 ;
     RECT  7.815 2.413 8.097 23.507 ;
     RECT  13.215 2.413 13.497 23.507 ;
     RECT  18.615 2.413 18.897 23.507 ;
     RECT  22.284 23.287 143.154 23.549 ;
     RECT  22.536 23.549 26.226 23.585 ;
     RECT  26.964 23.549 143.154 23.585 ;
     RECT  26.964 23.585 55.386 23.621 ;
     RECT  26.964 23.621 54.63 23.657 ;
     RECT  32.616 23.657 54.63 23.729 ;
     RECT  2.415 23.507 2.505 23.777 ;
     RECT  7.815 23.507 7.905 23.777 ;
     RECT  13.215 23.507 13.305 23.777 ;
     RECT  18.615 23.507 18.705 23.777 ;
     RECT  22.68 23.585 26.226 23.777 ;
     RECT  32.616 23.729 40.806 23.777 ;
     RECT  41.544 23.729 45.705 23.777 ;
     RECT  41.544 23.777 45.702 23.819 ;
     RECT  26.964 23.657 31.878 23.933 ;
     RECT  32.616 23.777 34.29 23.933 ;
     RECT  35.136 23.777 40.806 23.933 ;
     RECT  46.44 23.729 49.734 23.933 ;
     RECT  50.58 23.729 53.01 23.933 ;
     RECT  52.2 23.933 53.01 23.999 ;
     RECT  26.964 23.933 28.602 24.509 ;
     RECT  41.544 23.819 42.426 24.509 ;
     RECT  22.68 23.777 23.634 25.085 ;
     RECT  29.376 23.933 31.878 25.133 ;
     RECT  48.096 23.933 49.734 25.133 ;
     RECT  24.372 23.777 26.226 25.805 ;
     RECT  27.828 24.509 28.602 25.805 ;
     RECT  29.376 25.133 31.014 25.805 ;
     RECT  32.616 23.933 33.498 25.805 ;
     RECT  35.136 23.933 37.53 25.805 ;
     RECT  38.448 23.933 40.05 25.805 ;
     RECT  43.164 23.819 45.702 25.805 ;
     RECT  46.44 23.933 47.322 25.805 ;
     RECT  48.96 25.133 49.734 25.805 ;
     RECT  50.58 23.933 51.354 25.805 ;
     RECT  22.932 25.085 23.634 25.861 ;
     RECT  38.448 25.805 39.186 25.861 ;
     RECT  22.932 25.861 23.706 25.889 ;
     RECT  38.376 25.861 39.186 25.889 ;
     RECT  44.064 25.805 44.838 25.889 ;
     RECT  22.932 25.889 22.95 25.901 ;
     RECT  23.688 25.889 23.706 25.901 ;
     RECT  24.552 25.805 24.57 25.901 ;
     RECT  25.344 25.805 25.362 25.901 ;
     RECT  26.208 25.805 26.226 25.901 ;
     RECT  26.964 24.509 26.982 25.901 ;
     RECT  27.828 25.805 27.846 25.901 ;
     RECT  28.584 25.805 28.602 25.901 ;
     RECT  29.376 25.805 29.394 25.901 ;
     RECT  30.24 25.805 30.258 25.901 ;
     RECT  30.996 25.805 31.014 25.901 ;
     RECT  31.86 25.133 31.878 25.901 ;
     RECT  32.616 25.805 32.634 25.901 ;
     RECT  33.48 25.805 33.498 25.901 ;
     RECT  34.272 23.933 34.29 25.901 ;
     RECT  35.136 25.805 35.154 25.901 ;
     RECT  35.892 25.805 35.91 25.901 ;
     RECT  36.756 25.805 36.774 25.901 ;
     RECT  37.512 25.805 37.53 25.901 ;
     RECT  38.376 25.889 38.394 25.901 ;
     RECT  39.168 25.889 39.186 25.901 ;
     RECT  40.032 25.805 40.05 25.901 ;
     RECT  40.788 23.933 40.806 25.901 ;
     RECT  41.544 24.509 41.562 25.901 ;
     RECT  42.408 24.509 42.426 25.901 ;
     RECT  43.2 25.805 43.218 25.901 ;
     RECT  44.064 25.889 44.082 25.901 ;
     RECT  44.82 25.889 44.838 25.901 ;
     RECT  45.684 25.805 45.702 25.901 ;
     RECT  46.44 25.805 46.458 25.901 ;
     RECT  47.304 25.805 47.322 25.901 ;
     RECT  48.096 25.133 48.114 25.901 ;
     RECT  48.96 25.805 48.978 25.901 ;
     RECT  49.716 25.805 49.734 25.901 ;
     RECT  50.58 25.805 50.598 25.901 ;
     RECT  51.336 25.805 51.354 25.901 ;
     RECT  52.2 23.999 52.218 25.901 ;
     RECT  52.992 23.999 53.01 25.901 ;
     RECT  53.748 23.729 53.766 25.901 ;
     RECT  54.612 23.729 54.63 25.901 ;
     RECT  55.368 23.621 55.386 25.901 ;
     RECT  56.16 23.585 143.154 25.901 ;
    LAYER M4 ;
     RECT  0.06 13.008 0.227 13.032 ;
     RECT  0.181 4.416 2.408 4.44 ;
     RECT  2.408 2.148 2.512 23.772 ;
     RECT  2.512 2.418 2.704 23.502 ;
     RECT  2.704 4.416 7.808 4.44 ;
     RECT  7.808 2.148 7.912 23.772 ;
     RECT  7.912 2.418 8.104 23.502 ;
     RECT  8.104 4.416 13.208 4.44 ;
     RECT  13.208 2.148 13.312 23.772 ;
     RECT  13.312 2.418 13.504 23.502 ;
     RECT  13.504 4.416 18.608 4.44 ;
     RECT  18.608 2.148 18.712 23.772 ;
     RECT  18.712 2.418 18.904 23.502 ;
     RECT  18.904 4.416 22.669 4.44 ;
     RECT  22.501 25.056 22.709 25.08 ;
     RECT  22.273 1.728 24.008 1.752 ;
     RECT  22.669 3.84 24.008 4.44 ;
     RECT  24.008 1.728 24.112 23.772 ;
     RECT  24.112 1.728 24.304 23.502 ;
     RECT  24.304 3.84 24.689 4.44 ;
     RECT  23.245 25.776 25.877 25.8 ;
     RECT  24.689 3.936 26.305 4.44 ;
     RECT  26.533 23.376 26.777 23.4 ;
     RECT  27.397 24.48 27.605 24.504 ;
     RECT  26.305 3.84 27.925 4.44 ;
     RECT  28.165 25.776 28.397 25.8 ;
     RECT  28.997 23.904 29.081 23.928 ;
     RECT  24.304 1.728 29.408 1.752 ;
     RECT  27.925 3.408 29.408 4.44 ;
     RECT  29.408 1.728 29.512 23.772 ;
     RECT  29.512 1.728 29.704 23.502 ;
     RECT  29.704 3.408 30.305 4.44 ;
     RECT  29.797 25.776 30.737 25.8 ;
     RECT  31.381 25.104 31.475 25.128 ;
     RECT  30.305 3.552 31.633 4.44 ;
     RECT  31.813 22.752 31.961 22.776 ;
     RECT  33.061 25.776 33.221 25.8 ;
     RECT  31.633 3.408 33.757 4.44 ;
     RECT  32.293 23.904 34.193 23.928 ;
     RECT  34.652 23.376 34.765 23.772 ;
     RECT  29.704 1.728 34.808 1.752 ;
     RECT  33.757 3.312 34.808 4.44 ;
     RECT  34.765 22.752 34.808 23.772 ;
     RECT  34.808 1.728 34.912 23.772 ;
     RECT  34.912 1.728 35.104 23.502 ;
     RECT  35.461 25.776 37.145 25.8 ;
     RECT  37.957 23.904 38.189 23.928 ;
     RECT  38.684 23.376 38.771 23.4 ;
     RECT  35.104 3.312 38.905 4.44 ;
     RECT  38.905 2.832 38.989 4.44 ;
     RECT  39.589 25.776 39.845 25.8 ;
     RECT  35.104 1.728 40.208 1.752 ;
     RECT  38.989 3.312 40.208 4.44 ;
     RECT  40.208 1.728 40.345 23.772 ;
     RECT  40.345 1.728 40.504 23.928 ;
     RECT  40.504 23.904 41.609 23.928 ;
     RECT  41.957 24.48 42.041 24.504 ;
     RECT  40.504 3.12 43.585 4.44 ;
     RECT  40.504 1.728 43.669 1.752 ;
     RECT  43.585 3.12 43.676 4.68 ;
     RECT  43.676 2.832 43.763 4.68 ;
     RECT  44.485 0.576 44.569 0.6 ;
     RECT  42.853 25.776 45.325 25.8 ;
     RECT  45.205 1.728 45.608 1.752 ;
     RECT  43.763 3.12 45.608 4.68 ;
     RECT  45.608 1.728 45.712 23.772 ;
     RECT  45.712 1.728 45.904 23.736 ;
     RECT  45.904 3.024 46.829 4.68 ;
     RECT  45.904 23.712 46.901 23.736 ;
     RECT  46.885 25.776 47.009 25.8 ;
     RECT  47.653 23.904 47.765 23.928 ;
     RECT  48.445 25.104 48.563 25.128 ;
     RECT  46.829 3.888 49.165 4.68 ;
     RECT  49.285 25.776 49.565 25.8 ;
     RECT  45.904 1.728 51.008 1.752 ;
     RECT  49.165 3.408 51.008 4.68 ;
     RECT  50.149 23.376 51.008 23.4 ;
     RECT  50.917 25.776 51.185 25.8 ;
     RECT  51.008 1.728 51.304 23.772 ;
     RECT  51.304 3.408 51.365 4.68 ;
     RECT  51.365 3.84 52.621 4.68 ;
     RECT  51.749 23.904 53.021 23.928 ;
     RECT  52.621 3.84 53.377 4.728 ;
     RECT  53.377 3.408 53.957 4.728 ;
     RECT  53.957 3.84 54.997 4.728 ;
     RECT  54.997 3.552 55.813 4.728 ;
     RECT  51.304 1.728 56.293 1.752 ;
     RECT  55.813 2.736 56.293 4.728 ;
     RECT  56.293 1.728 56.408 4.728 ;
     RECT  53.413 23.376 56.408 23.4 ;
     RECT  56.185 24.528 56.408 24.552 ;
     RECT  56.408 1.728 56.512 24.552 ;
     RECT  56.512 1.728 56.704 23.502 ;
     RECT  56.704 22.656 57.017 23.4 ;
     RECT  56.512 24.528 57.203 24.552 ;
     RECT  56.704 3.12 58.093 4.728 ;
     RECT  56.704 1.728 58.117 2.088 ;
     RECT  58.093 3.12 58.117 4.968 ;
     RECT  57.017 23.376 58.133 23.4 ;
     RECT  58.405 23.712 58.673 23.736 ;
     RECT  58.789 23.952 58.961 23.976 ;
     RECT  59.173 21.552 59.285 21.576 ;
     RECT  59.209 22.8 59.293 22.824 ;
     RECT  59.525 25.056 59.609 25.08 ;
     RECT  58.117 1.728 59.644 4.968 ;
     RECT  60.505 23.376 61.081 23.4 ;
     RECT  60.029 24.48 61.301 24.504 ;
     RECT  61.081 23.376 61.541 23.448 ;
     RECT  61.541 23.136 61.573 23.448 ;
     RECT  59.644 3.12 61.621 4.968 ;
     RECT  61.621 3.12 61.669 5.064 ;
     RECT  60.805 21.648 61.669 21.672 ;
     RECT  59.644 1.728 61.808 1.752 ;
     RECT  61.669 2.784 61.808 5.064 ;
     RECT  61.669 21.504 61.808 21.672 ;
     RECT  61.573 23.04 61.808 23.448 ;
     RECT  61.808 1.728 61.912 23.772 ;
     RECT  61.669 25.776 62.099 25.8 ;
     RECT  61.912 1.728 62.104 23.502 ;
     RECT  62.104 21.504 62.129 22.824 ;
     RECT  62.129 22.224 62.425 22.824 ;
     RECT  62.437 25.056 62.525 25.08 ;
     RECT  62.425 22.224 62.669 22.248 ;
     RECT  62.821 24.48 63.029 24.504 ;
     RECT  62.104 1.728 63.173 5.064 ;
     RECT  63.173 1.728 63.289 4.968 ;
     RECT  63.205 21.648 63.605 21.672 ;
     RECT  63.457 23.376 63.685 23.4 ;
     RECT  63.289 3.12 64.001 4.968 ;
     RECT  64.001 3.216 64.213 4.968 ;
     RECT  63.685 23.376 64.453 23.928 ;
     RECT  64.213 3.216 64.597 5.112 ;
     RECT  64.597 3.216 64.613 5.16 ;
     RECT  64.613 3.312 64.684 5.16 ;
     RECT  64.453 23.376 64.721 23.976 ;
     RECT  64.837 21.648 64.973 21.672 ;
     RECT  64.684 3.312 65.045 5.112 ;
     RECT  64.721 23.376 65.113 23.4 ;
     RECT  63.289 1.728 65.413 1.752 ;
     RECT  65.317 22.176 65.549 22.2 ;
     RECT  65.113 23.328 65.701 23.4 ;
     RECT  65.701 23.328 65.833 23.928 ;
     RECT  65.413 1.728 65.837 2.28 ;
     RECT  65.833 22.8 66.035 23.928 ;
     RECT  66.035 23.376 66.089 23.928 ;
     RECT  66.089 23.376 66.131 23.4 ;
     RECT  65.837 1.728 66.169 1.8 ;
     RECT  66.373 25.104 66.515 25.128 ;
     RECT  65.045 3.312 66.877 5.064 ;
     RECT  66.169 1.728 67.208 1.752 ;
     RECT  66.877 3.312 67.208 5.16 ;
     RECT  66.853 21.648 67.208 21.672 ;
     RECT  67.021 22.8 67.208 22.824 ;
     RECT  67.208 1.728 67.301 23.772 ;
     RECT  67.301 1.728 67.385 23.928 ;
     RECT  67.385 1.728 67.504 23.502 ;
     RECT  67.504 3.408 67.709 5.4 ;
     RECT  67.504 21.648 67.734 23.448 ;
     RECT  67.504 1.728 67.781 1.8 ;
     RECT  67.709 3.408 68.177 5.112 ;
     RECT  67.734 21.648 68.365 23.4 ;
     RECT  67.781 1.728 68.857 1.752 ;
     RECT  68.485 24.48 68.965 24.504 ;
     RECT  68.857 1.104 69.011 1.752 ;
     RECT  68.965 24.48 69.049 24.552 ;
     RECT  68.365 21.648 69.221 22.248 ;
     RECT  68.177 3.84 69.253 5.112 ;
     RECT  69.221 21.648 69.293 21.672 ;
     RECT  68.365 23.376 69.337 23.4 ;
     RECT  69.253 3.408 69.361 5.112 ;
     RECT  69.361 3.312 69.437 5.112 ;
     RECT  69.011 1.728 69.493 1.752 ;
     RECT  69.437 3.312 69.493 5.064 ;
     RECT  69.349 23.712 69.545 23.736 ;
     RECT  69.493 1.728 69.797 5.064 ;
     RECT  69.733 25.776 69.869 25.8 ;
     RECT  70.117 25.056 70.577 25.08 ;
     RECT  69.797 3.312 70.645 5.064 ;
     RECT  70.577 24.48 70.661 25.08 ;
     RECT  70.661 25.056 71.065 25.08 ;
     RECT  70.613 23.376 71.365 23.4 ;
     RECT  71.365 23.376 71.452 23.976 ;
     RECT  71.341 21.984 71.521 22.008 ;
     RECT  70.645 3.312 71.629 5.112 ;
     RECT  69.797 1.728 71.729 1.752 ;
     RECT  71.629 3.312 71.729 5.16 ;
     RECT  71.521 21.744 71.749 22.008 ;
     RECT  71.729 1.728 71.881 1.848 ;
     RECT  71.729 2.832 71.881 5.16 ;
     RECT  71.452 23.376 72.565 23.928 ;
     RECT  71.881 1.728 72.608 5.16 ;
     RECT  71.749 21.744 72.608 22.152 ;
     RECT  72.565 23.376 72.608 24.552 ;
     RECT  72.608 1.728 72.712 24.552 ;
     RECT  72.712 1.728 72.904 23.502 ;
     RECT  72.925 0.096 73.043 0.12 ;
     RECT  72.904 23.376 73.117 23.4 ;
     RECT  72.904 3.216 73.276 5.16 ;
     RECT  72.712 24.528 73.427 24.552 ;
     RECT  72.904 21.552 74.117 21.576 ;
     RECT  74.245 25.776 74.368 25.8 ;
     RECT  74.368 25.728 74.369 25.8 ;
     RECT  74.369 25.728 74.513 25.752 ;
     RECT  74.588 23.376 74.675 23.4 ;
     RECT  75.193 22.8 75.277 22.824 ;
     RECT  73.276 3.216 75.836 5.064 ;
     RECT  72.904 1.728 75.985 1.752 ;
     RECT  75.836 3.216 75.985 5.16 ;
     RECT  75.985 1.728 76.307 5.16 ;
     RECT  76.307 3.216 76.355 5.16 ;
     RECT  75.877 23.376 76.381 23.4 ;
     RECT  76.381 22.848 76.525 23.4 ;
     RECT  76.525 22.8 76.645 23.4 ;
     RECT  75.013 24.48 76.645 24.504 ;
     RECT  76.645 22.8 76.781 24.504 ;
     RECT  76.781 24.48 77.141 24.504 ;
     RECT  76.307 1.728 77.893 1.752 ;
     RECT  77.893 1.728 78.008 1.848 ;
     RECT  76.355 3.216 78.008 5.112 ;
     RECT  77.893 21.696 78.008 21.72 ;
     RECT  76.781 22.8 78.008 23.4 ;
     RECT  78.008 1.728 78.277 23.772 ;
     RECT  78.277 1.728 78.304 23.928 ;
     RECT  78.304 22.8 78.545 23.928 ;
     RECT  78.304 21.696 78.689 21.72 ;
     RECT  77.509 25.056 78.941 25.08 ;
     RECT  79.045 25.776 79.157 25.8 ;
     RECT  78.545 22.8 79.273 23.4 ;
     RECT  79.273 22.8 79.589 22.824 ;
     RECT  78.304 1.728 79.868 1.752 ;
     RECT  78.304 3.216 79.868 4.968 ;
     RECT  79.868 1.728 79.955 4.968 ;
     RECT  79.868 24.528 79.955 24.552 ;
     RECT  79.525 21.648 80.057 21.672 ;
     RECT  80.261 23.904 80.485 23.928 ;
     RECT  80.485 23.376 80.579 23.928 ;
     RECT  80.579 23.904 80.921 23.928 ;
     RECT  79.955 3.216 81.445 4.968 ;
     RECT  81.157 25.056 81.497 25.08 ;
     RECT  81.445 3.216 81.532 5.16 ;
     RECT  81.532 3.216 81.533 3.336 ;
     RECT  81.532 4.416 81.533 5.16 ;
     RECT  79.955 1.728 81.817 1.752 ;
     RECT  81.541 24.48 81.821 24.504 ;
     RECT  80.233 22.176 81.925 22.2 ;
     RECT  81.817 1.728 81.971 1.8 ;
     RECT  81.925 22.08 81.989 22.2 ;
     RECT  81.989 22.08 82.073 22.824 ;
     RECT  82.073 22.08 82.217 22.104 ;
     RECT  81.533 4.416 82.597 4.968 ;
     RECT  81.533 3.312 82.609 3.336 ;
     RECT  82.597 4.416 82.609 5.544 ;
     RECT  82.609 0.096 82.835 0.12 ;
     RECT  82.789 24.48 83.009 24.504 ;
     RECT  83.173 21.648 83.269 21.672 ;
     RECT  81.971 1.728 83.408 1.752 ;
     RECT  82.609 3.312 83.408 5.544 ;
     RECT  83.269 21.648 83.408 22.248 ;
     RECT  82.141 23.376 83.408 23.448 ;
     RECT  83.408 1.728 83.704 23.772 ;
     RECT  82.309 25.776 84.053 25.8 ;
     RECT  83.704 23.376 84.421 23.772 ;
     RECT  83.704 3.36 84.557 5.544 ;
     RECT  83.704 22.224 84.593 22.248 ;
     RECT  84.557 3.36 84.737 5.496 ;
     RECT  84.805 22.128 84.892 22.152 ;
     RECT  84.737 4.752 85.097 5.496 ;
     RECT  84.421 23.376 85.097 23.928 ;
     RECT  84.737 3.36 85.237 3.768 ;
     RECT  85.157 25.056 85.241 25.08 ;
     RECT  85.097 23.376 85.321 23.4 ;
     RECT  83.704 1.728 85.489 1.752 ;
     RECT  85.489 1.728 85.619 2.28 ;
     RECT  85.573 21.648 85.957 21.672 ;
     RECT  85.957 21.6 86.105 21.672 ;
     RECT  86.353 22.8 86.437 22.824 ;
     RECT  86.105 21.6 86.465 21.624 ;
     RECT  85.237 3.312 86.645 3.768 ;
     RECT  86.389 23.952 86.821 23.976 ;
     RECT  86.645 3.312 86.825 3.72 ;
     RECT  87.181 25.776 87.265 25.8 ;
     RECT  87.541 22.8 87.653 22.824 ;
     RECT  86.821 23.904 87.829 23.976 ;
     RECT  86.825 3.36 87.925 3.72 ;
     RECT  87.829 23.376 88.069 23.976 ;
     RECT  85.097 4.752 88.117 5.256 ;
     RECT  87.925 2.832 88.261 3.72 ;
     RECT  88.117 4.752 88.261 5.688 ;
     RECT  88.069 23.376 88.301 24.504 ;
     RECT  88.301 23.376 88.499 23.976 ;
     RECT  85.619 1.728 88.685 1.752 ;
     RECT  88.261 2.832 88.685 5.688 ;
     RECT  88.685 1.728 88.808 5.688 ;
     RECT  88.693 21.504 88.808 21.528 ;
     RECT  88.499 23.376 88.808 23.772 ;
     RECT  88.693 25.776 88.883 25.8 ;
     RECT  88.808 1.728 89.104 23.772 ;
     RECT  89.104 21.648 89.489 22.248 ;
     RECT  89.489 22.224 89.561 22.248 ;
     RECT  89.104 23.376 89.66 23.772 ;
     RECT  89.104 1.728 89.677 2.28 ;
     RECT  89.66 23.376 89.747 23.976 ;
     RECT  89.104 3.264 90.313 5.256 ;
     RECT  90.313 2.832 90.397 5.256 ;
     RECT  89.747 23.376 90.433 23.4 ;
     RECT  90.085 25.056 90.469 25.08 ;
     RECT  90.469 25.008 90.497 25.08 ;
     RECT  89.677 1.728 90.533 1.8 ;
     RECT  90.497 25.008 90.569 25.032 ;
     RECT  91.465 22.8 91.613 22.824 ;
     RECT  90.533 1.728 91.621 1.752 ;
     RECT  91.621 1.728 91.676 2.232 ;
     RECT  90.397 3.264 92.101 5.256 ;
     RECT  92.101 3.264 92.261 5.4 ;
     RECT  90.853 24.48 92.261 24.504 ;
     RECT  92.261 3.312 92.549 5.4 ;
     RECT  91.676 23.376 92.828 23.4 ;
     RECT  91.676 1.728 92.915 2.28 ;
     RECT  92.828 23.376 92.915 23.976 ;
     RECT  92.915 23.376 93.121 23.4 ;
     RECT  92.549 3.312 93.373 5.256 ;
     RECT  92.465 21.648 93.725 21.672 ;
     RECT  93.121 22.848 94.049 23.4 ;
     RECT  94.049 22.8 94.117 23.4 ;
     RECT  92.915 1.728 94.208 1.752 ;
     RECT  93.373 2.832 94.208 5.256 ;
     RECT  93.725 21.6 94.208 21.672 ;
     RECT  94.117 22.8 94.208 23.928 ;
     RECT  94.208 1.728 94.504 23.928 ;
     RECT  94.504 22.8 95.185 23.928 ;
     RECT  95.185 23.376 95.501 23.928 ;
     RECT  95.501 23.376 95.581 23.4 ;
     RECT  94.504 1.728 95.669 1.752 ;
     RECT  95.669 1.728 95.701 2.28 ;
     RECT  94.504 3.408 95.701 5.256 ;
     RECT  95.701 1.728 95.825 5.256 ;
     RECT  95.749 24.48 95.933 24.504 ;
     RECT  95.825 3.312 96.041 5.256 ;
     RECT  95.825 1.728 96.179 2.28 ;
     RECT  96.469 22.8 96.553 22.824 ;
     RECT  96.133 21.648 96.613 21.672 ;
     RECT  96.613 21.6 96.905 21.672 ;
     RECT  96.041 3.312 97.009 3.912 ;
     RECT  96.041 4.896 97.009 5.256 ;
     RECT  96.905 21.648 97.381 21.672 ;
     RECT  97.009 3.312 97.429 5.256 ;
     RECT  97.381 21.648 97.589 22.2 ;
     RECT  97.589 21.648 97.661 21.672 ;
     RECT  96.685 23.376 97.916 23.4 ;
     RECT  97.916 22.8 98.003 23.4 ;
     RECT  98.003 22.896 98.021 23.4 ;
     RECT  98.021 23.376 98.233 23.4 ;
     RECT  97.429 3.216 98.437 5.256 ;
     RECT  98.437 3.216 98.485 5.352 ;
     RECT  98.485 2.784 98.593 5.352 ;
     RECT  97.765 24.48 98.629 24.504 ;
     RECT  96.179 1.728 98.693 1.752 ;
     RECT  98.593 2.784 98.693 5.592 ;
     RECT  98.629 24.48 99.137 25.08 ;
     RECT  98.233 23.376 99.253 23.448 ;
     RECT  99.253 23.376 99.397 23.496 ;
     RECT  98.693 1.728 99.608 5.592 ;
     RECT  98.557 21.696 99.608 21.72 ;
     RECT  99.397 23.376 99.608 23.928 ;
     RECT  99.608 1.728 99.904 23.928 ;
     RECT  99.137 25.056 100.109 25.08 ;
     RECT  99.904 23.376 100.115 23.928 ;
     RECT  100.021 0.096 100.307 0.12 ;
     RECT  100.22 24.528 100.307 24.552 ;
     RECT  100.115 23.376 100.325 23.448 ;
     RECT  99.904 1.728 100.739 5.592 ;
     RECT  100.739 2.736 100.865 5.592 ;
     RECT  100.325 23.376 101.153 23.4 ;
     RECT  100.865 2.736 101.356 5.256 ;
     RECT  99.904 22.224 101.513 22.248 ;
     RECT  101.393 23.904 101.981 23.928 ;
     RECT  100.739 1.728 102.337 1.752 ;
     RECT  101.356 3.312 102.337 5.256 ;
     RECT  102.337 1.728 102.467 5.256 ;
     RECT  102.277 24.528 102.521 24.552 ;
     RECT  102.661 25.056 102.773 25.08 ;
     RECT  102.467 1.728 103.097 1.8 ;
     RECT  103.045 23.904 103.133 23.928 ;
     RECT  102.467 3.216 103.139 5.256 ;
     RECT  102.985 22.8 103.525 22.824 ;
     RECT  103.139 3.312 103.853 5.256 ;
     RECT  103.525 22.8 104.256 23.4 ;
     RECT  104.256 22.8 104.677 23.448 ;
     RECT  103.853 3.408 104.821 5.256 ;
     RECT  103.909 24.48 104.821 24.504 ;
     RECT  103.097 1.728 105.008 1.752 ;
     RECT  104.821 3.312 105.008 5.256 ;
     RECT  104.677 22.032 105.008 23.448 ;
     RECT  104.821 24.48 105.008 24.552 ;
     RECT  105.008 1.728 105.107 24.552 ;
     RECT  105.107 1.728 105.112 24.504 ;
     RECT  105.112 1.728 105.304 23.502 ;
     RECT  105.304 22.032 105.473 22.056 ;
     RECT  105.112 24.48 105.689 24.504 ;
     RECT  105.304 23.376 106.013 23.4 ;
     RECT  105.304 3.6 106.265 5.256 ;
     RECT  106.265 3.696 106.373 5.256 ;
     RECT  106.268 25.104 106.685 25.128 ;
     RECT  106.685 24.48 106.769 25.128 ;
     RECT  105.304 1.728 106.837 1.752 ;
     RECT  106.373 3.84 106.837 5.256 ;
     RECT  106.837 3.84 106.921 5.352 ;
     RECT  106.837 1.728 107.201 2.712 ;
     RECT  106.769 25.104 107.219 25.128 ;
     RECT  107.089 23.376 107.377 23.4 ;
     RECT  106.921 3.84 107.669 5.256 ;
     RECT  107.377 22.8 107.821 23.4 ;
     RECT  107.669 3.84 108.037 5.16 ;
     RECT  107.201 1.728 108.277 1.752 ;
     RECT  107.941 24.48 108.281 24.504 ;
     RECT  107.821 23.376 108.325 23.4 ;
     RECT  108.037 3.408 108.565 5.16 ;
     RECT  108.325 23.376 108.569 23.976 ;
     RECT  108.277 1.728 108.701 2.232 ;
     RECT  108.565 3.36 108.701 5.16 ;
     RECT  108.701 1.728 108.785 5.16 ;
     RECT  108.569 23.376 109.141 23.4 ;
     RECT  108.805 21.648 109.189 21.672 ;
     RECT  108.785 1.728 109.235 2.28 ;
     RECT  109.189 21.552 109.433 21.672 ;
     RECT  109.141 22.8 109.573 23.4 ;
     RECT  109.573 22.8 109.861 23.928 ;
     RECT  108.785 3.36 109.969 5.16 ;
     RECT  109.861 22.8 110.003 24.696 ;
     RECT  110.003 22.8 110.245 23.928 ;
     RECT  110.245 25.776 110.387 25.8 ;
     RECT  109.235 1.728 110.408 1.752 ;
     RECT  109.969 3.36 110.408 5.208 ;
     RECT  110.245 22.032 110.408 23.928 ;
     RECT  110.408 1.728 110.704 23.928 ;
     RECT  110.704 1.728 110.873 5.208 ;
     RECT  110.704 22.032 111.413 22.056 ;
     RECT  110.873 1.728 111.635 2.28 ;
     RECT  110.704 23.376 111.635 23.928 ;
     RECT  111.635 23.856 111.737 23.928 ;
     RECT  110.873 3.312 112.453 5.208 ;
     RECT  111.635 1.728 112.837 1.752 ;
     RECT  112.837 1.152 112.979 1.752 ;
     RECT  112.837 25.056 113.033 25.08 ;
     RECT  111.737 23.904 113.425 23.928 ;
     RECT  113.425 23.424 113.569 23.928 ;
     RECT  112.453 3.216 113.573 5.208 ;
     RECT  113.573 3.312 113.651 5.208 ;
     RECT  113.569 23.376 114.437 23.928 ;
     RECT  114.437 23.376 114.556 23.496 ;
     RECT  113.605 25.776 114.941 25.8 ;
     RECT  113.651 3.36 115.477 5.208 ;
     RECT  112.979 1.728 115.808 1.752 ;
     RECT  115.477 3.36 115.808 5.496 ;
     RECT  115.237 22.224 115.808 22.248 ;
     RECT  114.556 23.376 115.808 23.4 ;
     RECT  115.717 24.528 115.808 24.552 ;
     RECT  115.808 1.728 116.104 24.552 ;
     RECT  116.104 23.376 116.165 24.552 ;
     RECT  116.165 23.376 116.317 23.592 ;
     RECT  116.485 25.056 116.569 25.08 ;
     RECT  116.104 1.728 117.244 1.752 ;
     RECT  117.244 1.728 117.353 1.8 ;
     RECT  116.104 3.696 117.397 5.496 ;
     RECT  116.104 21.648 117.461 21.672 ;
     RECT  117.637 22.8 117.721 22.824 ;
     RECT  117.169 23.952 117.733 23.976 ;
     RECT  117.397 3.312 118.001 5.496 ;
     RECT  117.733 23.904 118.001 23.976 ;
     RECT  118.001 23.952 118.069 23.976 ;
     RECT  118.069 23.952 118.163 24.552 ;
     RECT  118.163 23.952 118.547 23.976 ;
     RECT  118.885 25.776 119.009 25.8 ;
     RECT  118.001 3.408 119.145 5.496 ;
     RECT  119.145 3.744 119.333 5.496 ;
     RECT  119.113 22.896 119.509 22.92 ;
     RECT  119.365 23.904 119.509 23.928 ;
     RECT  119.509 22.8 119.593 23.928 ;
     RECT  120.013 25.056 120.179 25.08 ;
     RECT  119.333 3.936 120.481 5.496 ;
     RECT  117.353 1.728 120.997 1.752 ;
     RECT  119.593 22.8 120.997 22.824 ;
     RECT  119.593 23.904 120.997 23.928 ;
     RECT  120.481 3.456 121.093 5.496 ;
     RECT  121.093 3.408 121.201 5.496 ;
     RECT  120.997 1.728 121.208 1.992 ;
     RECT  121.201 3.312 121.208 5.496 ;
     RECT  120.997 22.8 121.208 23.928 ;
     RECT  121.208 1.728 121.504 23.928 ;
     RECT  121.504 23.856 121.733 23.928 ;
     RECT  121.504 3.312 122.533 3.432 ;
     RECT  121.504 4.464 122.533 5.496 ;
     RECT  121.733 23.856 122.605 24.504 ;
     RECT  122.605 23.376 122.753 24.504 ;
     RECT  122.753 23.376 123.113 23.928 ;
     RECT  121.504 1.728 123.397 1.752 ;
     RECT  123.397 25.056 123.509 25.08 ;
     RECT  123.113 23.376 123.683 23.4 ;
     RECT  123.397 1.104 123.827 1.752 ;
     RECT  123.781 24.48 124.157 24.504 ;
     RECT  124.165 21.648 124.409 21.672 ;
     RECT  124.645 23.904 125.237 23.928 ;
     RECT  125.413 24.48 125.885 24.504 ;
     RECT  123.827 1.728 126.608 1.752 ;
     RECT  122.533 3.312 126.608 5.496 ;
     RECT  125.797 23.376 126.608 23.4 ;
     RECT  126.661 25.104 126.785 25.128 ;
     RECT  126.608 1.728 126.904 23.772 ;
     RECT  126.904 22.32 127.043 22.824 ;
     RECT  126.904 3.312 127.073 5.496 ;
     RECT  127.043 22.32 127.091 22.344 ;
     RECT  127.429 23.904 128.293 23.928 ;
     RECT  128.293 23.904 128.677 23.976 ;
     RECT  128.677 23.472 128.753 23.976 ;
     RECT  128.753 23.376 129.041 23.976 ;
     RECT  129.041 23.376 129.125 24.504 ;
     RECT  129.125 23.376 129.997 23.928 ;
     RECT  130.301 25.776 130.385 25.8 ;
     RECT  129.997 23.376 130.573 23.4 ;
     RECT  130.693 25.056 131.069 25.08 ;
     RECT  131.077 23.952 131.357 23.976 ;
     RECT  131.525 21.648 131.749 21.672 ;
     RECT  127.073 3.36 131.797 5.496 ;
     RECT  131.749 25.776 131.987 25.8 ;
     RECT  126.904 1.728 132.008 1.752 ;
     RECT  131.797 3.36 132.008 5.592 ;
     RECT  131.749 21.648 132.008 22.152 ;
     RECT  131.677 23.376 132.008 23.928 ;
     RECT  132.008 1.728 132.304 23.928 ;
     RECT  132.304 23.376 132.373 23.928 ;
     RECT  132.304 3.36 132.401 5.592 ;
     RECT  132.304 1.728 132.761 2.28 ;
     RECT  132.373 23.376 132.797 23.4 ;
     RECT  133.181 24.48 133.573 24.504 ;
     RECT  132.761 2.256 133.619 2.28 ;
     RECT  133.573 23.904 133.733 24.504 ;
     RECT  133.733 24.432 134.453 24.504 ;
     RECT  132.401 3.36 134.705 5.496 ;
     RECT  134.953 22.8 135.101 22.824 ;
     RECT  134.453 24.48 135.317 24.504 ;
     RECT  134.705 3.36 135.745 3.384 ;
     RECT  134.705 4.512 135.745 5.496 ;
     RECT  135.589 23.904 136.019 23.976 ;
     RECT  135.745 3.36 136.165 5.496 ;
     RECT  136.817 25.776 136.901 25.8 ;
     RECT  136.357 21.696 137.221 21.72 ;
     RECT  133.957 1.728 137.293 1.752 ;
     RECT  137.293 1.104 137.408 1.752 ;
     RECT  136.165 3.312 137.408 5.496 ;
     RECT  137.221 21.504 137.408 21.72 ;
     RECT  136.141 23.376 137.408 23.4 ;
     RECT  137.408 1.104 137.605 23.772 ;
     RECT  137.605 1.104 137.651 23.976 ;
     RECT  137.651 1.728 137.704 23.976 ;
     RECT  137.704 21.648 137.729 21.72 ;
     RECT  137.704 23.376 137.843 23.976 ;
     RECT  137.989 24.48 138.125 24.504 ;
     RECT  137.729 21.648 138.853 21.672 ;
     RECT  137.704 3.312 138.881 5.496 ;
     RECT  138.853 21.648 139.133 22.2 ;
     RECT  138.841 25.776 139.283 25.8 ;
     RECT  137.843 23.376 139.309 23.4 ;
     RECT  138.881 3.408 139.561 5.496 ;
     RECT  137.704 1.728 139.58 1.752 ;
     RECT  139.309 22.8 139.633 23.4 ;
     RECT  139.525 21.552 139.745 21.576 ;
     RECT  139.561 3.408 139.765 5.736 ;
     RECT  139.765 3.408 139.853 6.024 ;
     RECT  139.916 3.36 140.003 3.384 ;
     RECT  139.853 4.512 140.099 5.736 ;
     RECT  139.633 22.8 140.147 23.976 ;
     RECT  140.147 22.8 140.579 23.4 ;
     RECT  140.099 4.512 140.681 5.496 ;
     RECT  139.58 1.728 140.821 2.28 ;
     RECT  140.821 1.68 140.915 2.28 ;
     RECT  140.461 21.456 140.929 21.48 ;
     RECT  140.681 4.512 141.077 5.112 ;
     RECT  140.579 22.8 141.113 23.352 ;
     RECT  140.929 21.168 141.26 21.48 ;
     RECT  140.915 1.728 141.299 2.28 ;
     RECT  141.26 21.168 141.347 21.672 ;
     RECT  141.113 22.8 141.361 22.824 ;
     RECT  141.281 19.92 141.365 19.944 ;
     RECT  141.347 21.168 141.437 21.384 ;
     RECT  141.437 21.36 141.509 21.384 ;
     RECT  141.077 5.088 141.617 5.112 ;
     RECT  141.505 24.528 141.683 24.552 ;
     RECT  141.299 1.728 141.689 1.752 ;
     RECT  141.361 22.704 142.44 22.824 ;
     RECT  142.44 0.096 142.561 0.12 ;
     RECT  142.44 22.704 142.561 23.352 ;
     RECT  141.937 1.68 142.931 1.704 ;
     RECT  142.561 22.704 142.931 22.728 ;
    LAYER M5 ;
     RECT  22.512 0.016 142.92 0.611 ;
     RECT  45.264 0.611 142.92 1.715 ;
     RECT  22.512 0.611 43.656 1.763 ;
     RECT  45.264 1.715 141.672 1.763 ;
     RECT  65.424 1.763 67.752 1.811 ;
     RECT  81.936 1.763 81.96 1.811 ;
     RECT  88.704 1.763 90.504 1.811 ;
     RECT  102.432 1.763 103.08 1.811 ;
     RECT  117.264 1.763 117.288 1.811 ;
     RECT  71.76 1.763 72.912 1.859 ;
     RECT  77.904 1.763 78.312 1.859 ;
     RECT  121.008 1.763 121.512 2.003 ;
     RECT  56.304 1.763 59.592 2.099 ;
     RECT  2.4 2.137 2.52 2.151 ;
     RECT  7.8 2.137 7.92 2.151 ;
     RECT  13.2 2.137 13.32 2.151 ;
     RECT  18.6 2.137 18.72 2.151 ;
     RECT  76.272 1.763 76.296 2.291 ;
     RECT  79.92 1.763 79.944 2.291 ;
     RECT  85.584 1.763 85.608 2.291 ;
     RECT  91.632 1.763 92.904 2.291 ;
     RECT  95.712 1.763 96.168 2.291 ;
     RECT  108.288 1.763 109.224 2.291 ;
     RECT  110.4 1.763 111.624 2.291 ;
     RECT  132 1.763 133.608 2.291 ;
     RECT  139.632 1.763 141.288 2.291 ;
     RECT  56.304 2.099 56.712 2.725 ;
     RECT  98.736 1.763 100.728 2.725 ;
     RECT  61.8 1.763 63.24 2.773 ;
     RECT  98.736 2.725 101.304 2.773 ;
     RECT  71.904 1.859 72.912 2.821 ;
     RECT  88.704 1.811 89.64 2.821 ;
     RECT  94.2 1.763 94.512 2.821 ;
     RECT  110.4 2.291 110.856 2.915 ;
     RECT  43.728 2.821 43.752 3.155 ;
     RECT  102.432 1.811 102.456 3.205 ;
     RECT  87.936 2.821 90.36 3.253 ;
     RECT  61.68 2.773 63.24 3.301 ;
     RECT  78 1.859 78.312 3.301 ;
     RECT  91.632 2.291 92.232 3.301 ;
     RECT  93.408 2.821 94.512 3.301 ;
     RECT  95.712 2.291 95.736 3.301 ;
     RECT  97.44 3.205 97.464 3.301 ;
     RECT  98.496 2.773 101.304 3.301 ;
     RECT  105 1.763 105.312 3.301 ;
     RECT  137.4 1.763 137.712 3.301 ;
     RECT  38.928 2.821 38.952 3.347 ;
     RECT  65.424 1.811 65.448 3.349 ;
     RECT  66.48 1.811 67.512 3.349 ;
     RECT  83.4 1.763 83.712 3.349 ;
     RECT  85.248 3.301 85.272 3.349 ;
     RECT  115.8 1.763 116.112 3.349 ;
     RECT  132 2.291 132.312 3.349 ;
     RECT  64.368 3.205 64.392 3.397 ;
     RECT  65.424 3.349 67.512 3.397 ;
     RECT  69.504 1.763 69.528 3.397 ;
     RECT  71.76 2.821 72.912 3.397 ;
     RECT  74.64 3.301 74.664 3.397 ;
     RECT  76.032 3.205 76.056 3.397 ;
     RECT  91.632 3.301 94.512 3.397 ;
     RECT  95.712 3.301 101.304 3.397 ;
     RECT  102.432 3.205 103.128 3.397 ;
     RECT  104.832 3.301 105.312 3.397 ;
     RECT  108.288 2.291 108.744 3.397 ;
     RECT  110.4 2.915 110.712 3.397 ;
     RECT  113.616 3.301 113.64 3.397 ;
     RECT  121.2 2.003 121.512 3.397 ;
     RECT  64.368 3.397 67.704 3.491 ;
     RECT  132 3.349 132.456 3.589 ;
     RECT  60.912 3.301 63.24 3.685 ;
     RECT  64.368 3.491 66.024 3.685 ;
     RECT  115.104 3.349 116.112 3.685 ;
     RECT  115.104 3.685 116.28 3.733 ;
     RECT  117.408 3.301 117.432 3.733 ;
     RECT  126.6 1.763 126.912 3.733 ;
     RECT  139.968 3.349 139.992 3.733 ;
     RECT  121.104 3.397 121.512 3.829 ;
     RECT  136.176 3.301 136.2 3.829 ;
     RECT  137.4 3.301 138.024 3.829 ;
     RECT  106.848 1.763 106.872 3.877 ;
     RECT  108.048 3.397 108.744 3.877 ;
     RECT  110.16 3.397 110.712 3.877 ;
     RECT  111.744 3.301 111.768 3.877 ;
     RECT  113.616 3.397 113.784 3.877 ;
     RECT  114.96 3.733 116.28 3.877 ;
     RECT  129.6 3.349 129.624 3.877 ;
     RECT  131.328 3.589 132.456 3.877 ;
     RECT  71.232 3.397 72.912 3.925 ;
     RECT  74.64 3.397 76.056 3.925 ;
     RECT  78 3.301 79.272 3.925 ;
     RECT  113.616 3.877 116.28 3.925 ;
     RECT  117.408 3.733 117.672 3.925 ;
     RECT  74.64 3.925 79.272 3.971 ;
     RECT  119.088 3.397 119.112 3.971 ;
     RECT  34.8 1.763 35.112 3.973 ;
     RECT  123.648 3.733 123.672 3.973 ;
     RECT  55.824 2.725 56.712 4.019 ;
     RECT  70.848 3.925 73.08 4.117 ;
     RECT  91.632 3.397 101.304 4.117 ;
     RECT  34.704 3.973 35.112 4.259 ;
     RECT  60.912 3.685 66.024 4.261 ;
     RECT  80.544 3.925 80.568 4.261 ;
     RECT  82.032 3.301 82.056 4.261 ;
     RECT  31.344 3.925 31.368 4.355 ;
     RECT  106.848 3.877 108.744 4.405 ;
     RECT  122.544 3.733 122.568 4.405 ;
     RECT  136.176 3.829 138.024 4.453 ;
     RECT  139.296 3.733 139.992 4.453 ;
     RECT  67.008 3.491 67.704 4.501 ;
     RECT  69.264 3.397 69.528 4.501 ;
     RECT  80.544 4.261 82.056 4.501 ;
     RECT  83.4 3.349 85.272 4.501 ;
     RECT  120.624 3.829 121.512 4.501 ;
     RECT  122.544 4.405 122.664 4.501 ;
     RECT  129.6 3.877 132.456 4.501 ;
     RECT  128.784 4.501 132.456 4.549 ;
     RECT  136.176 4.453 139.992 4.549 ;
     RECT  58.128 2.099 59.592 4.595 ;
     RECT  102.432 3.397 105.312 4.595 ;
     RECT  110.16 3.877 111.768 4.595 ;
     RECT  44.16 3.541 44.184 4.643 ;
     RECT  58.128 4.595 59.256 4.643 ;
     RECT  58.944 4.643 59.256 4.787 ;
     RECT  91.584 4.117 101.304 4.787 ;
     RECT  136.176 4.549 140.088 4.789 ;
     RECT  67.008 4.501 69.528 4.835 ;
     RECT  60.576 4.261 66.024 4.883 ;
     RECT  70.848 4.117 74.184 4.883 ;
     RECT  123.648 3.973 123.768 4.883 ;
     RECT  128.016 4.549 132.456 4.883 ;
     RECT  120.624 4.501 122.664 4.885 ;
     RECT  123.648 4.883 123.672 4.885 ;
     RECT  103.056 4.595 105.312 4.931 ;
     RECT  70.848 4.883 73.224 5.077 ;
     RECT  103.152 4.931 105.312 5.077 ;
     RECT  119.52 5.029 119.544 5.077 ;
     RECT  136.176 4.789 140.424 5.077 ;
     RECT  67.008 4.835 69.288 5.171 ;
     RECT  70.656 5.077 73.224 5.171 ;
     RECT  75.216 3.971 79.272 5.171 ;
     RECT  80.544 4.501 85.272 5.171 ;
     RECT  87.936 3.253 90.408 5.171 ;
     RECT  91.584 4.787 100.824 5.171 ;
     RECT  128.016 4.883 132.312 5.171 ;
     RECT  120.624 4.885 123.672 5.219 ;
     RECT  122.544 5.219 123.672 5.267 ;
     RECT  113.616 3.925 117.672 5.315 ;
     RECT  106.848 4.405 109.176 5.363 ;
     RECT  128.016 5.171 130.536 5.459 ;
     RECT  0.192 4.405 0.216 13.043 ;
     RECT  136.176 5.077 140.568 19.909 ;
     RECT  59.232 4.787 59.256 21.541 ;
     RECT  70.656 5.171 73.08 21.541 ;
     RECT  107.136 5.363 109.176 21.541 ;
     RECT  110.16 4.595 111.144 21.541 ;
     RECT  82.032 5.171 85.272 21.589 ;
     RECT  86.4 3.349 86.424 21.589 ;
     RECT  60.576 4.883 62.376 21.637 ;
     RECT  63.504 4.883 66.024 21.637 ;
     RECT  67.056 5.171 69.288 21.637 ;
     RECT  76.56 5.171 79.272 21.637 ;
     RECT  113.616 5.315 116.28 21.637 ;
     RECT  117.648 5.315 117.672 21.637 ;
     RECT  122.64 5.267 123.672 21.637 ;
     RECT  131.712 5.171 132.312 21.637 ;
     RECT  136.176 19.909 141.336 21.683 ;
     RECT  82.032 21.589 86.424 22.069 ;
     RECT  126.6 3.733 127.032 22.309 ;
     RECT  56.4 4.019 56.712 22.645 ;
     RECT  136.176 21.683 140.568 22.789 ;
     RECT  142.896 22.693 142.92 22.789 ;
     RECT  59.184 21.541 59.256 22.835 ;
     RECT  60.576 21.637 69.288 22.835 ;
     RECT  75.216 5.171 75.24 22.835 ;
     RECT  81.936 22.069 86.424 22.835 ;
     RECT  92.112 5.171 100.824 22.835 ;
     RECT  103.152 5.077 105.624 22.835 ;
     RECT  113.616 21.637 117.672 22.835 ;
     RECT  119.52 5.077 119.64 22.835 ;
     RECT  120.624 5.219 121.512 22.835 ;
     RECT  34.8 4.259 35.112 23.365 ;
     RECT  51 1.763 51.312 23.365 ;
     RECT  56.4 22.645 56.808 23.365 ;
     RECT  70.656 21.541 73.8 23.365 ;
     RECT  76.56 21.637 79.56 23.365 ;
     RECT  92.112 22.835 94.512 23.365 ;
     RECT  95.52 22.835 100.824 23.365 ;
     RECT  103.536 22.835 105.624 23.365 ;
     RECT  107.136 21.541 111.144 23.365 ;
     RECT  126.6 22.309 127.08 23.365 ;
     RECT  131.568 21.637 132.312 23.365 ;
     RECT  60.576 22.835 62.112 23.411 ;
     RECT  63.216 22.835 69.288 23.411 ;
     RECT  70.656 23.365 74.664 23.411 ;
     RECT  75.888 23.365 79.56 23.411 ;
     RECT  87.984 5.171 90.408 23.411 ;
     RECT  107.136 23.365 111.624 23.411 ;
     RECT  122.64 21.637 124.2 23.411 ;
     RECT  128.784 5.459 130.536 23.411 ;
     RECT  81.936 22.835 85.992 23.459 ;
     RECT  95.52 23.365 101.064 23.459 ;
     RECT  128.784 23.411 129.96 23.461 ;
     RECT  99.264 23.459 101.064 23.507 ;
     RECT  45.6 1.763 45.912 23.701 ;
     RECT  53.424 23.365 57.96 23.701 ;
     RECT  59.184 22.835 59.208 23.701 ;
     RECT  2.4 2.151 2.712 23.769 ;
     RECT  7.8 2.151 8.112 23.769 ;
     RECT  13.2 2.151 13.512 23.769 ;
     RECT  18.6 2.151 18.912 23.769 ;
     RECT  24 1.763 24.312 23.769 ;
     RECT  29.4 1.763 29.712 23.769 ;
     RECT  34.704 23.365 35.112 23.769 ;
     RECT  2.4 23.769 2.52 23.783 ;
     RECT  7.8 23.769 7.92 23.783 ;
     RECT  13.2 23.769 13.32 23.783 ;
     RECT  18.6 23.769 18.72 23.783 ;
     RECT  24 23.769 24.12 23.783 ;
     RECT  29.4 23.769 29.52 23.783 ;
     RECT  34.704 23.769 34.92 23.783 ;
     RECT  40.2 1.763 40.512 23.783 ;
     RECT  45.6 23.701 46.152 23.783 ;
     RECT  50.16 23.365 51.312 23.783 ;
     RECT  60.816 23.411 62.112 23.783 ;
     RECT  83.184 23.459 85.992 23.783 ;
     RECT  91.728 23.365 94.512 23.845 ;
     RECT  34.704 23.783 34.728 23.893 ;
     RECT  38.736 23.365 38.76 23.893 ;
     RECT  40.368 23.783 40.512 23.893 ;
     RECT  53.424 23.701 59.208 23.893 ;
     RECT  79.536 23.411 79.56 23.893 ;
     RECT  80.544 5.171 80.568 23.893 ;
     RECT  84.432 23.783 85.992 23.893 ;
     RECT  91.728 23.845 94.536 23.893 ;
     RECT  95.52 23.459 97.416 23.893 ;
     RECT  99.408 23.507 101.064 23.893 ;
     RECT  103.536 23.365 105.96 23.893 ;
     RECT  107.568 23.411 111.624 23.893 ;
     RECT  113.616 22.835 116.904 23.893 ;
     RECT  119.52 22.835 119.544 23.893 ;
     RECT  121.008 22.835 121.512 23.893 ;
     RECT  124.176 23.411 124.2 23.893 ;
     RECT  125.808 23.365 127.08 23.893 ;
     RECT  128.688 23.461 129.96 23.893 ;
     RECT  131.568 23.365 132.744 23.893 ;
     RECT  136.176 22.789 142.92 23.893 ;
     RECT  84.432 23.893 86.856 23.941 ;
     RECT  87.984 23.411 89.736 23.941 ;
     RECT  107.568 23.893 117.768 23.941 ;
     RECT  119.376 23.893 121.512 23.941 ;
     RECT  131.568 23.893 133.608 23.941 ;
     RECT  131.088 23.941 133.608 24.421 ;
     RECT  26.544 23.365 26.568 24.469 ;
     RECT  40.368 23.893 41.256 24.469 ;
     RECT  51.792 23.893 59.208 24.469 ;
     RECT  60.816 23.783 61.704 24.469 ;
     RECT  63.216 23.411 68.136 24.469 ;
     RECT  69.36 23.701 69.384 24.469 ;
     RECT  71.376 23.411 74.664 24.469 ;
     RECT  75.888 23.411 76.68 24.469 ;
     RECT  77.904 23.411 78.312 24.469 ;
     RECT  79.536 23.893 80.712 24.469 ;
     RECT  81.936 23.459 81.96 24.469 ;
     RECT  83.184 23.783 83.304 24.469 ;
     RECT  91.728 23.893 97.416 24.469 ;
     RECT  99.408 23.893 101.928 24.469 ;
     RECT  103.056 23.893 105.96 24.469 ;
     RECT  107.568 23.941 121.512 24.469 ;
     RECT  123.024 23.411 123.048 24.469 ;
     RECT  124.176 23.893 129.96 24.469 ;
     RECT  131.088 24.421 134.376 24.469 ;
     RECT  135.6 23.893 142.92 24.469 ;
     RECT  90.864 24.469 101.928 24.517 ;
     RECT  103.056 24.469 129.96 24.517 ;
     RECT  84.432 23.941 89.736 24.997 ;
     RECT  90.864 24.517 129.96 24.997 ;
     RECT  51.792 24.469 61.704 25.045 ;
     RECT  62.832 24.469 69.384 25.045 ;
     RECT  70.608 24.469 78.312 25.045 ;
     RECT  79.536 24.469 83.304 25.045 ;
     RECT  84.432 24.997 129.96 25.045 ;
     RECT  131.088 24.469 142.92 25.045 ;
     RECT  32.304 23.893 32.328 25.093 ;
     RECT  47.664 23.893 47.688 25.093 ;
     RECT  22.512 25.045 22.536 25.765 ;
     RECT  26.544 24.469 27.432 25.765 ;
     RECT  29.04 23.893 29.064 25.765 ;
     RECT  31.44 25.093 32.328 25.765 ;
     RECT  33.936 23.893 34.728 25.765 ;
     RECT  37.968 23.893 38.76 25.765 ;
     RECT  40.368 24.469 42.024 25.765 ;
     RECT  46.128 23.783 46.152 25.765 ;
     RECT  47.664 25.093 48.552 25.765 ;
     RECT  50.16 23.783 50.184 25.765 ;
     RECT  51.792 25.045 83.304 25.765 ;
     RECT  84.432 25.045 142.92 25.765 ;
     RECT  22.512 25.765 142.92 25.872 ;
  END
END ot_s81_hc_ctrn_par_w
END LIBRARY
